VERSION 5.8 ;
BUSBITCHARS "[]" ;
DIVIDERCHAR "/" ;
UNITS
    DATABASE MICRONS 1000 ;
END UNITS

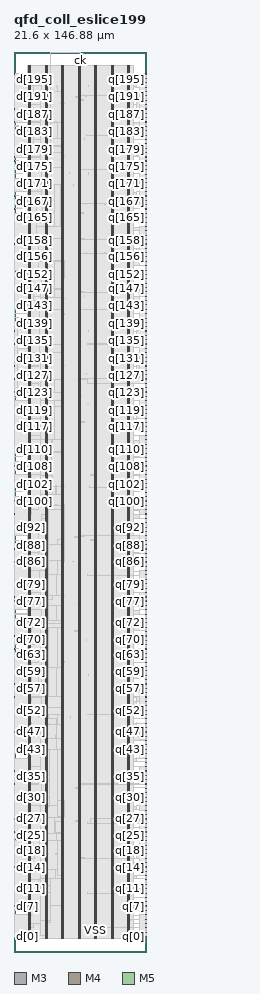
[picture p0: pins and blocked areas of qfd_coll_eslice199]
MACRO qfd_coll_eslice199
  FOREIGN qfd_coll_eslice199 0 0 ;
  CLASS BLOCK ;
  SIZE 21.6 BY 146.88 ;
  PIN ck
    DIRECTION INPUT ;
    USE SIGNAL ;
    PORT
      LAYER M3 ;
        RECT  10.8 146.842 10.818 146.88 ;
    END
    PORT
      LAYER M3 ;
        RECT  10.8 146.731 10.818 146.861 ;
    END
  END ck
  PIN d[0]
    DIRECTION INPUT ;
    USE SIGNAL ;
    PORT
      LAYER M4 ;
        RECT  0 2.496 0.084 2.52 ;
    END
  END d[0]
  PIN d[100]
    DIRECTION INPUT ;
    USE SIGNAL ;
    PORT
      LAYER M4 ;
        RECT  0 73.584 0.084 73.608 ;
    END
  END d[100]
  PIN d[101]
    DIRECTION INPUT ;
    USE SIGNAL ;
    PORT
      LAYER M4 ;
        RECT  0 74.304 0.084 74.328 ;
    END
  END d[101]
  PIN d[102]
    DIRECTION INPUT ;
    USE SIGNAL ;
    PORT
      LAYER M4 ;
        RECT  0 75.024 0.084 75.048 ;
    END
  END d[102]
  PIN d[103]
    DIRECTION INPUT ;
    USE SIGNAL ;
    PORT
      LAYER M4 ;
        RECT  0 75.744 0.084 75.768 ;
    END
  END d[103]
  PIN d[104]
    DIRECTION INPUT ;
    USE SIGNAL ;
    PORT
      LAYER M4 ;
        RECT  0 76.464 0.084 76.488 ;
    END
  END d[104]
  PIN d[105]
    DIRECTION INPUT ;
    USE SIGNAL ;
    PORT
      LAYER M4 ;
        RECT  0 77.136 0.084 77.16 ;
    END
  END d[105]
  PIN d[106]
    DIRECTION INPUT ;
    USE SIGNAL ;
    PORT
      LAYER M4 ;
        RECT  0 77.856 0.084 77.88 ;
    END
  END d[106]
  PIN d[107]
    DIRECTION INPUT ;
    USE SIGNAL ;
    PORT
      LAYER M4 ;
        RECT  0 78.576 0.084 78.6 ;
    END
  END d[107]
  PIN d[108]
    DIRECTION INPUT ;
    USE SIGNAL ;
    PORT
      LAYER M4 ;
        RECT  0 79.296 0.084 79.32 ;
    END
  END d[108]
  PIN d[109]
    DIRECTION INPUT ;
    USE SIGNAL ;
    PORT
      LAYER M4 ;
        RECT  0 80.016 0.084 80.04 ;
    END
  END d[109]
  PIN d[10]
    DIRECTION INPUT ;
    USE SIGNAL ;
    PORT
      LAYER M4 ;
        RECT  0 9.6 0.084 9.624 ;
    END
  END d[10]
  PIN d[110]
    DIRECTION INPUT ;
    USE SIGNAL ;
    PORT
      LAYER M4 ;
        RECT  0 80.688 0.084 80.712 ;
    END
  END d[110]
  PIN d[111]
    DIRECTION INPUT ;
    USE SIGNAL ;
    PORT
      LAYER M4 ;
        RECT  0 81.408 0.084 81.432 ;
    END
  END d[111]
  PIN d[112]
    DIRECTION INPUT ;
    USE SIGNAL ;
    PORT
      LAYER M4 ;
        RECT  0 82.128 0.084 82.152 ;
    END
  END d[112]
  PIN d[113]
    DIRECTION INPUT ;
    USE SIGNAL ;
    PORT
      LAYER M4 ;
        RECT  0 82.848 0.084 82.872 ;
    END
  END d[113]
  PIN d[114]
    DIRECTION INPUT ;
    USE SIGNAL ;
    PORT
      LAYER M4 ;
        RECT  0 83.568 0.084 83.592 ;
    END
  END d[114]
  PIN d[115]
    DIRECTION INPUT ;
    USE SIGNAL ;
    PORT
      LAYER M4 ;
        RECT  0 84.24 0.084 84.264 ;
    END
  END d[115]
  PIN d[116]
    DIRECTION INPUT ;
    USE SIGNAL ;
    PORT
      LAYER M4 ;
        RECT  0 84.96 0.084 84.984 ;
    END
  END d[116]
  PIN d[117]
    DIRECTION INPUT ;
    USE SIGNAL ;
    PORT
      LAYER M4 ;
        RECT  0 85.68 0.084 85.704 ;
    END
  END d[117]
  PIN d[118]
    DIRECTION INPUT ;
    USE SIGNAL ;
    PORT
      LAYER M4 ;
        RECT  0 86.4 0.084 86.424 ;
    END
  END d[118]
  PIN d[119]
    DIRECTION INPUT ;
    USE SIGNAL ;
    PORT
      LAYER M4 ;
        RECT  0 87.12 0.084 87.144 ;
    END
  END d[119]
  PIN d[11]
    DIRECTION INPUT ;
    USE SIGNAL ;
    PORT
      LAYER M4 ;
        RECT  0 10.32 0.084 10.344 ;
    END
  END d[11]
  PIN d[120]
    DIRECTION INPUT ;
    USE SIGNAL ;
    PORT
      LAYER M4 ;
        RECT  0 87.84 0.084 87.864 ;
    END
  END d[120]
  PIN d[121]
    DIRECTION INPUT ;
    USE SIGNAL ;
    PORT
      LAYER M4 ;
        RECT  0 88.512 0.084 88.536 ;
    END
  END d[121]
  PIN d[122]
    DIRECTION INPUT ;
    USE SIGNAL ;
    PORT
      LAYER M4 ;
        RECT  0 89.232 0.084 89.256 ;
    END
  END d[122]
  PIN d[123]
    DIRECTION INPUT ;
    USE SIGNAL ;
    PORT
      LAYER M4 ;
        RECT  0 89.952 0.084 89.976 ;
    END
  END d[123]
  PIN d[124]
    DIRECTION INPUT ;
    USE SIGNAL ;
    PORT
      LAYER M4 ;
        RECT  0 90.672 0.084 90.696 ;
    END
  END d[124]
  PIN d[125]
    DIRECTION INPUT ;
    USE SIGNAL ;
    PORT
      LAYER M4 ;
        RECT  0 91.392 0.084 91.416 ;
    END
  END d[125]
  PIN d[126]
    DIRECTION INPUT ;
    USE SIGNAL ;
    PORT
      LAYER M4 ;
        RECT  0 92.064 0.084 92.088 ;
    END
  END d[126]
  PIN d[127]
    DIRECTION INPUT ;
    USE SIGNAL ;
    PORT
      LAYER M4 ;
        RECT  0 92.784 0.084 92.808 ;
    END
  END d[127]
  PIN d[128]
    DIRECTION INPUT ;
    USE SIGNAL ;
    PORT
      LAYER M4 ;
        RECT  0 93.504 0.084 93.528 ;
    END
  END d[128]
  PIN d[129]
    DIRECTION INPUT ;
    USE SIGNAL ;
    PORT
      LAYER M4 ;
        RECT  0 94.224 0.084 94.248 ;
    END
  END d[129]
  PIN d[12]
    DIRECTION INPUT ;
    USE SIGNAL ;
    PORT
      LAYER M4 ;
        RECT  0 11.04 0.084 11.064 ;
    END
  END d[12]
  PIN d[130]
    DIRECTION INPUT ;
    USE SIGNAL ;
    PORT
      LAYER M4 ;
        RECT  0 94.944 0.084 94.968 ;
    END
  END d[130]
  PIN d[131]
    DIRECTION INPUT ;
    USE SIGNAL ;
    PORT
      LAYER M4 ;
        RECT  0 95.616 0.084 95.64 ;
    END
  END d[131]
  PIN d[132]
    DIRECTION INPUT ;
    USE SIGNAL ;
    PORT
      LAYER M4 ;
        RECT  0 96.336 0.084 96.36 ;
    END
  END d[132]
  PIN d[133]
    DIRECTION INPUT ;
    USE SIGNAL ;
    PORT
      LAYER M4 ;
        RECT  0 97.056 0.084 97.08 ;
    END
  END d[133]
  PIN d[134]
    DIRECTION INPUT ;
    USE SIGNAL ;
    PORT
      LAYER M4 ;
        RECT  0 97.776 0.084 97.8 ;
    END
  END d[134]
  PIN d[135]
    DIRECTION INPUT ;
    USE SIGNAL ;
    PORT
      LAYER M4 ;
        RECT  0 98.496 0.084 98.52 ;
    END
  END d[135]
  PIN d[136]
    DIRECTION INPUT ;
    USE SIGNAL ;
    PORT
      LAYER M4 ;
        RECT  0 99.216 0.084 99.24 ;
    END
  END d[136]
  PIN d[137]
    DIRECTION INPUT ;
    USE SIGNAL ;
    PORT
      LAYER M4 ;
        RECT  0 99.888 0.084 99.912 ;
    END
  END d[137]
  PIN d[138]
    DIRECTION INPUT ;
    USE SIGNAL ;
    PORT
      LAYER M4 ;
        RECT  0 100.608 0.084 100.632 ;
    END
  END d[138]
  PIN d[139]
    DIRECTION INPUT ;
    USE SIGNAL ;
    PORT
      LAYER M4 ;
        RECT  0 101.328 0.084 101.352 ;
    END
  END d[139]
  PIN d[13]
    DIRECTION INPUT ;
    USE SIGNAL ;
    PORT
      LAYER M4 ;
        RECT  0 11.76 0.084 11.784 ;
    END
  END d[13]
  PIN d[140]
    DIRECTION INPUT ;
    USE SIGNAL ;
    PORT
      LAYER M4 ;
        RECT  0 102.048 0.084 102.072 ;
    END
  END d[140]
  PIN d[141]
    DIRECTION INPUT ;
    USE SIGNAL ;
    PORT
      LAYER M4 ;
        RECT  0 102.768 0.084 102.792 ;
    END
  END d[141]
  PIN d[142]
    DIRECTION INPUT ;
    USE SIGNAL ;
    PORT
      LAYER M4 ;
        RECT  0 103.44 0.084 103.464 ;
    END
  END d[142]
  PIN d[143]
    DIRECTION INPUT ;
    USE SIGNAL ;
    PORT
      LAYER M4 ;
        RECT  0 104.16 0.084 104.184 ;
    END
  END d[143]
  PIN d[144]
    DIRECTION INPUT ;
    USE SIGNAL ;
    PORT
      LAYER M4 ;
        RECT  0 104.88 0.084 104.904 ;
    END
  END d[144]
  PIN d[145]
    DIRECTION INPUT ;
    USE SIGNAL ;
    PORT
      LAYER M4 ;
        RECT  0 105.6 0.084 105.624 ;
    END
  END d[145]
  PIN d[146]
    DIRECTION INPUT ;
    USE SIGNAL ;
    PORT
      LAYER M4 ;
        RECT  0 106.32 0.084 106.344 ;
    END
  END d[146]
  PIN d[147]
    DIRECTION INPUT ;
    USE SIGNAL ;
    PORT
      LAYER M4 ;
        RECT  0 106.992 0.084 107.016 ;
    END
  END d[147]
  PIN d[148]
    DIRECTION INPUT ;
    USE SIGNAL ;
    PORT
      LAYER M4 ;
        RECT  0 107.712 0.084 107.736 ;
    END
  END d[148]
  PIN d[149]
    DIRECTION INPUT ;
    USE SIGNAL ;
    PORT
      LAYER M4 ;
        RECT  0 108.432 0.084 108.456 ;
    END
  END d[149]
  PIN d[14]
    DIRECTION INPUT ;
    USE SIGNAL ;
    PORT
      LAYER M4 ;
        RECT  0 12.48 0.084 12.504 ;
    END
  END d[14]
  PIN d[150]
    DIRECTION INPUT ;
    USE SIGNAL ;
    PORT
      LAYER M4 ;
        RECT  0 109.152 0.084 109.176 ;
    END
  END d[150]
  PIN d[151]
    DIRECTION INPUT ;
    USE SIGNAL ;
    PORT
      LAYER M4 ;
        RECT  0 109.872 0.084 109.896 ;
    END
  END d[151]
  PIN d[152]
    DIRECTION INPUT ;
    USE SIGNAL ;
    PORT
      LAYER M4 ;
        RECT  0 110.592 0.084 110.616 ;
    END
  END d[152]
  PIN d[153]
    DIRECTION INPUT ;
    USE SIGNAL ;
    PORT
      LAYER M4 ;
        RECT  0 111.264 0.084 111.288 ;
    END
  END d[153]
  PIN d[154]
    DIRECTION INPUT ;
    USE SIGNAL ;
    PORT
      LAYER M4 ;
        RECT  0 111.984 0.084 112.008 ;
    END
  END d[154]
  PIN d[155]
    DIRECTION INPUT ;
    USE SIGNAL ;
    PORT
      LAYER M4 ;
        RECT  0 112.704 0.084 112.728 ;
    END
  END d[155]
  PIN d[156]
    DIRECTION INPUT ;
    USE SIGNAL ;
    PORT
      LAYER M4 ;
        RECT  0 113.424 0.084 113.448 ;
    END
  END d[156]
  PIN d[157]
    DIRECTION INPUT ;
    USE SIGNAL ;
    PORT
      LAYER M4 ;
        RECT  0 114.144 0.084 114.168 ;
    END
  END d[157]
  PIN d[158]
    DIRECTION INPUT ;
    USE SIGNAL ;
    PORT
      LAYER M4 ;
        RECT  0 114.816 0.084 114.84 ;
    END
  END d[158]
  PIN d[159]
    DIRECTION INPUT ;
    USE SIGNAL ;
    PORT
      LAYER M4 ;
        RECT  0 115.536 0.084 115.56 ;
    END
  END d[159]
  PIN d[15]
    DIRECTION INPUT ;
    USE SIGNAL ;
    PORT
      LAYER M4 ;
        RECT  0 13.152 0.084 13.176 ;
    END
  END d[15]
  PIN d[160]
    DIRECTION INPUT ;
    USE SIGNAL ;
    PORT
      LAYER M4 ;
        RECT  0 116.256 0.084 116.28 ;
    END
  END d[160]
  PIN d[161]
    DIRECTION INPUT ;
    USE SIGNAL ;
    PORT
      LAYER M4 ;
        RECT  0 116.976 0.084 117 ;
    END
  END d[161]
  PIN d[162]
    DIRECTION INPUT ;
    USE SIGNAL ;
    PORT
      LAYER M4 ;
        RECT  0 117.696 0.084 117.72 ;
    END
  END d[162]
  PIN d[163]
    DIRECTION INPUT ;
    USE SIGNAL ;
    PORT
      LAYER M4 ;
        RECT  0 118.368 0.084 118.392 ;
    END
  END d[163]
  PIN d[164]
    DIRECTION INPUT ;
    USE SIGNAL ;
    PORT
      LAYER M4 ;
        RECT  0 119.088 0.084 119.112 ;
    END
  END d[164]
  PIN d[165]
    DIRECTION INPUT ;
    USE SIGNAL ;
    PORT
      LAYER M4 ;
        RECT  0 119.808 0.084 119.832 ;
    END
  END d[165]
  PIN d[166]
    DIRECTION INPUT ;
    USE SIGNAL ;
    PORT
      LAYER M4 ;
        RECT  0 120.528 0.084 120.552 ;
    END
  END d[166]
  PIN d[167]
    DIRECTION INPUT ;
    USE SIGNAL ;
    PORT
      LAYER M4 ;
        RECT  0 121.248 0.084 121.272 ;
    END
  END d[167]
  PIN d[168]
    DIRECTION INPUT ;
    USE SIGNAL ;
    PORT
      LAYER M4 ;
        RECT  0 121.968 0.084 121.992 ;
    END
  END d[168]
  PIN d[169]
    DIRECTION INPUT ;
    USE SIGNAL ;
    PORT
      LAYER M4 ;
        RECT  0 122.64 0.084 122.664 ;
    END
  END d[169]
  PIN d[16]
    DIRECTION INPUT ;
    USE SIGNAL ;
    PORT
      LAYER M4 ;
        RECT  0 13.872 0.084 13.896 ;
    END
  END d[16]
  PIN d[170]
    DIRECTION INPUT ;
    USE SIGNAL ;
    PORT
      LAYER M4 ;
        RECT  0 123.36 0.084 123.384 ;
    END
  END d[170]
  PIN d[171]
    DIRECTION INPUT ;
    USE SIGNAL ;
    PORT
      LAYER M4 ;
        RECT  0 124.08 0.084 124.104 ;
    END
  END d[171]
  PIN d[172]
    DIRECTION INPUT ;
    USE SIGNAL ;
    PORT
      LAYER M4 ;
        RECT  0 124.8 0.084 124.824 ;
    END
  END d[172]
  PIN d[173]
    DIRECTION INPUT ;
    USE SIGNAL ;
    PORT
      LAYER M4 ;
        RECT  0 125.52 0.084 125.544 ;
    END
  END d[173]
  PIN d[174]
    DIRECTION INPUT ;
    USE SIGNAL ;
    PORT
      LAYER M4 ;
        RECT  0 126.192 0.084 126.216 ;
    END
  END d[174]
  PIN d[175]
    DIRECTION INPUT ;
    USE SIGNAL ;
    PORT
      LAYER M4 ;
        RECT  0 126.912 0.084 126.936 ;
    END
  END d[175]
  PIN d[176]
    DIRECTION INPUT ;
    USE SIGNAL ;
    PORT
      LAYER M4 ;
        RECT  0 127.632 0.084 127.656 ;
    END
  END d[176]
  PIN d[177]
    DIRECTION INPUT ;
    USE SIGNAL ;
    PORT
      LAYER M4 ;
        RECT  0 128.352 0.084 128.376 ;
    END
  END d[177]
  PIN d[178]
    DIRECTION INPUT ;
    USE SIGNAL ;
    PORT
      LAYER M4 ;
        RECT  0 129.072 0.084 129.096 ;
    END
  END d[178]
  PIN d[179]
    DIRECTION INPUT ;
    USE SIGNAL ;
    PORT
      LAYER M4 ;
        RECT  0 129.744 0.084 129.768 ;
    END
  END d[179]
  PIN d[17]
    DIRECTION INPUT ;
    USE SIGNAL ;
    PORT
      LAYER M4 ;
        RECT  0 14.592 0.084 14.616 ;
    END
  END d[17]
  PIN d[180]
    DIRECTION INPUT ;
    USE SIGNAL ;
    PORT
      LAYER M4 ;
        RECT  0 130.464 0.084 130.488 ;
    END
  END d[180]
  PIN d[181]
    DIRECTION INPUT ;
    USE SIGNAL ;
    PORT
      LAYER M4 ;
        RECT  0 131.184 0.084 131.208 ;
    END
  END d[181]
  PIN d[182]
    DIRECTION INPUT ;
    USE SIGNAL ;
    PORT
      LAYER M4 ;
        RECT  0 131.904 0.084 131.928 ;
    END
  END d[182]
  PIN d[183]
    DIRECTION INPUT ;
    USE SIGNAL ;
    PORT
      LAYER M4 ;
        RECT  0 132.624 0.084 132.648 ;
    END
  END d[183]
  PIN d[184]
    DIRECTION INPUT ;
    USE SIGNAL ;
    PORT
      LAYER M4 ;
        RECT  0 133.296 0.084 133.32 ;
    END
  END d[184]
  PIN d[185]
    DIRECTION INPUT ;
    USE SIGNAL ;
    PORT
      LAYER M4 ;
        RECT  0 134.016 0.084 134.04 ;
    END
  END d[185]
  PIN d[186]
    DIRECTION INPUT ;
    USE SIGNAL ;
    PORT
      LAYER M4 ;
        RECT  0 134.736 0.084 134.76 ;
    END
  END d[186]
  PIN d[187]
    DIRECTION INPUT ;
    USE SIGNAL ;
    PORT
      LAYER M4 ;
        RECT  0 135.456 0.084 135.48 ;
    END
  END d[187]
  PIN d[188]
    DIRECTION INPUT ;
    USE SIGNAL ;
    PORT
      LAYER M4 ;
        RECT  0 136.176 0.084 136.2 ;
    END
  END d[188]
  PIN d[189]
    DIRECTION INPUT ;
    USE SIGNAL ;
    PORT
      LAYER M4 ;
        RECT  0 136.896 0.084 136.92 ;
    END
  END d[189]
  PIN d[18]
    DIRECTION INPUT ;
    USE SIGNAL ;
    PORT
      LAYER M4 ;
        RECT  0 15.312 0.084 15.336 ;
    END
  END d[18]
  PIN d[190]
    DIRECTION INPUT ;
    USE SIGNAL ;
    PORT
      LAYER M4 ;
        RECT  0 137.568 0.084 137.592 ;
    END
  END d[190]
  PIN d[191]
    DIRECTION INPUT ;
    USE SIGNAL ;
    PORT
      LAYER M4 ;
        RECT  0 138.288 0.084 138.312 ;
    END
  END d[191]
  PIN d[192]
    DIRECTION INPUT ;
    USE SIGNAL ;
    PORT
      LAYER M4 ;
        RECT  0 139.008 0.084 139.032 ;
    END
  END d[192]
  PIN d[193]
    DIRECTION INPUT ;
    USE SIGNAL ;
    PORT
      LAYER M4 ;
        RECT  0 139.728 0.084 139.752 ;
    END
  END d[193]
  PIN d[194]
    DIRECTION INPUT ;
    USE SIGNAL ;
    PORT
      LAYER M4 ;
        RECT  0 140.448 0.084 140.472 ;
    END
  END d[194]
  PIN d[195]
    DIRECTION INPUT ;
    USE SIGNAL ;
    PORT
      LAYER M4 ;
        RECT  0 141.12 0.084 141.144 ;
    END
  END d[195]
  PIN d[196]
    DIRECTION INPUT ;
    USE SIGNAL ;
    PORT
      LAYER M4 ;
        RECT  0 141.84 0.084 141.864 ;
    END
  END d[196]
  PIN d[197]
    DIRECTION INPUT ;
    USE SIGNAL ;
    PORT
      LAYER M4 ;
        RECT  0 142.56 0.084 142.584 ;
    END
  END d[197]
  PIN d[198]
    DIRECTION INPUT ;
    USE SIGNAL ;
    PORT
      LAYER M4 ;
        RECT  0 143.28 0.084 143.304 ;
    END
  END d[198]
  PIN d[19]
    DIRECTION INPUT ;
    USE SIGNAL ;
    PORT
      LAYER M4 ;
        RECT  0 16.032 0.084 16.056 ;
    END
  END d[19]
  PIN d[1]
    DIRECTION INPUT ;
    USE SIGNAL ;
    PORT
      LAYER M4 ;
        RECT  0 3.216 0.084 3.24 ;
    END
  END d[1]
  PIN d[20]
    DIRECTION INPUT ;
    USE SIGNAL ;
    PORT
      LAYER M4 ;
        RECT  0 16.704 0.084 16.728 ;
    END
  END d[20]
  PIN d[21]
    DIRECTION INPUT ;
    USE SIGNAL ;
    PORT
      LAYER M4 ;
        RECT  0 17.424 0.084 17.448 ;
    END
  END d[21]
  PIN d[22]
    DIRECTION INPUT ;
    USE SIGNAL ;
    PORT
      LAYER M4 ;
        RECT  0 18.144 0.084 18.168 ;
    END
  END d[22]
  PIN d[23]
    DIRECTION INPUT ;
    USE SIGNAL ;
    PORT
      LAYER M4 ;
        RECT  0 18.864 0.084 18.888 ;
    END
  END d[23]
  PIN d[24]
    DIRECTION INPUT ;
    USE SIGNAL ;
    PORT
      LAYER M4 ;
        RECT  0 19.584 0.084 19.608 ;
    END
  END d[24]
  PIN d[25]
    DIRECTION INPUT ;
    USE SIGNAL ;
    PORT
      LAYER M4 ;
        RECT  0 20.256 0.084 20.28 ;
    END
  END d[25]
  PIN d[26]
    DIRECTION INPUT ;
    USE SIGNAL ;
    PORT
      LAYER M4 ;
        RECT  0 20.976 0.084 21 ;
    END
  END d[26]
  PIN d[27]
    DIRECTION INPUT ;
    USE SIGNAL ;
    PORT
      LAYER M4 ;
        RECT  0 21.696 0.084 21.72 ;
    END
  END d[27]
  PIN d[28]
    DIRECTION INPUT ;
    USE SIGNAL ;
    PORT
      LAYER M4 ;
        RECT  0 22.416 0.084 22.44 ;
    END
  END d[28]
  PIN d[29]
    DIRECTION INPUT ;
    USE SIGNAL ;
    PORT
      LAYER M4 ;
        RECT  0 23.136 0.084 23.16 ;
    END
  END d[29]
  PIN d[2]
    DIRECTION INPUT ;
    USE SIGNAL ;
    PORT
      LAYER M4 ;
        RECT  0 3.936 0.084 3.96 ;
    END
  END d[2]
  PIN d[30]
    DIRECTION INPUT ;
    USE SIGNAL ;
    PORT
      LAYER M4 ;
        RECT  0 23.856 0.084 23.88 ;
    END
  END d[30]
  PIN d[31]
    DIRECTION INPUT ;
    USE SIGNAL ;
    PORT
      LAYER M4 ;
        RECT  0 24.528 0.084 24.552 ;
    END
  END d[31]
  PIN d[32]
    DIRECTION INPUT ;
    USE SIGNAL ;
    PORT
      LAYER M4 ;
        RECT  0 25.248 0.084 25.272 ;
    END
  END d[32]
  PIN d[33]
    DIRECTION INPUT ;
    USE SIGNAL ;
    PORT
      LAYER M4 ;
        RECT  0 25.968 0.084 25.992 ;
    END
  END d[33]
  PIN d[34]
    DIRECTION INPUT ;
    USE SIGNAL ;
    PORT
      LAYER M4 ;
        RECT  0 26.688 0.084 26.712 ;
    END
  END d[34]
  PIN d[35]
    DIRECTION INPUT ;
    USE SIGNAL ;
    PORT
      LAYER M4 ;
        RECT  0 27.408 0.084 27.432 ;
    END
  END d[35]
  PIN d[36]
    DIRECTION INPUT ;
    USE SIGNAL ;
    PORT
      LAYER M4 ;
        RECT  0 28.08 0.084 28.104 ;
    END
  END d[36]
  PIN d[37]
    DIRECTION INPUT ;
    USE SIGNAL ;
    PORT
      LAYER M4 ;
        RECT  0 28.8 0.084 28.824 ;
    END
  END d[37]
  PIN d[38]
    DIRECTION INPUT ;
    USE SIGNAL ;
    PORT
      LAYER M4 ;
        RECT  0 29.52 0.084 29.544 ;
    END
  END d[38]
  PIN d[39]
    DIRECTION INPUT ;
    USE SIGNAL ;
    PORT
      LAYER M4 ;
        RECT  0 30.24 0.084 30.264 ;
    END
  END d[39]
  PIN d[3]
    DIRECTION INPUT ;
    USE SIGNAL ;
    PORT
      LAYER M4 ;
        RECT  0 4.656 0.084 4.68 ;
    END
  END d[3]
  PIN d[40]
    DIRECTION INPUT ;
    USE SIGNAL ;
    PORT
      LAYER M4 ;
        RECT  0 30.96 0.084 30.984 ;
    END
  END d[40]
  PIN d[41]
    DIRECTION INPUT ;
    USE SIGNAL ;
    PORT
      LAYER M4 ;
        RECT  0 31.632 0.084 31.656 ;
    END
  END d[41]
  PIN d[42]
    DIRECTION INPUT ;
    USE SIGNAL ;
    PORT
      LAYER M4 ;
        RECT  0 32.352 0.084 32.376 ;
    END
  END d[42]
  PIN d[43]
    DIRECTION INPUT ;
    USE SIGNAL ;
    PORT
      LAYER M4 ;
        RECT  0 33.072 0.084 33.096 ;
    END
  END d[43]
  PIN d[44]
    DIRECTION INPUT ;
    USE SIGNAL ;
    PORT
      LAYER M4 ;
        RECT  0 33.792 0.084 33.816 ;
    END
  END d[44]
  PIN d[45]
    DIRECTION INPUT ;
    USE SIGNAL ;
    PORT
      LAYER M4 ;
        RECT  0 34.512 0.084 34.536 ;
    END
  END d[45]
  PIN d[46]
    DIRECTION INPUT ;
    USE SIGNAL ;
    PORT
      LAYER M4 ;
        RECT  0 35.184 0.084 35.208 ;
    END
  END d[46]
  PIN d[47]
    DIRECTION INPUT ;
    USE SIGNAL ;
    PORT
      LAYER M4 ;
        RECT  0 35.904 0.084 35.928 ;
    END
  END d[47]
  PIN d[48]
    DIRECTION INPUT ;
    USE SIGNAL ;
    PORT
      LAYER M4 ;
        RECT  0 36.624 0.084 36.648 ;
    END
  END d[48]
  PIN d[49]
    DIRECTION INPUT ;
    USE SIGNAL ;
    PORT
      LAYER M4 ;
        RECT  0 37.344 0.084 37.368 ;
    END
  END d[49]
  PIN d[4]
    DIRECTION INPUT ;
    USE SIGNAL ;
    PORT
      LAYER M4 ;
        RECT  0 5.328 0.084 5.352 ;
    END
  END d[4]
  PIN d[50]
    DIRECTION INPUT ;
    USE SIGNAL ;
    PORT
      LAYER M4 ;
        RECT  0 38.064 0.084 38.088 ;
    END
  END d[50]
  PIN d[51]
    DIRECTION INPUT ;
    USE SIGNAL ;
    PORT
      LAYER M4 ;
        RECT  0 38.784 0.084 38.808 ;
    END
  END d[51]
  PIN d[52]
    DIRECTION INPUT ;
    USE SIGNAL ;
    PORT
      LAYER M4 ;
        RECT  0 39.456 0.084 39.48 ;
    END
  END d[52]
  PIN d[53]
    DIRECTION INPUT ;
    USE SIGNAL ;
    PORT
      LAYER M4 ;
        RECT  0 40.176 0.084 40.2 ;
    END
  END d[53]
  PIN d[54]
    DIRECTION INPUT ;
    USE SIGNAL ;
    PORT
      LAYER M4 ;
        RECT  0 40.896 0.084 40.92 ;
    END
  END d[54]
  PIN d[55]
    DIRECTION INPUT ;
    USE SIGNAL ;
    PORT
      LAYER M4 ;
        RECT  0 41.616 0.084 41.64 ;
    END
  END d[55]
  PIN d[56]
    DIRECTION INPUT ;
    USE SIGNAL ;
    PORT
      LAYER M4 ;
        RECT  0 42.336 0.084 42.36 ;
    END
  END d[56]
  PIN d[57]
    DIRECTION INPUT ;
    USE SIGNAL ;
    PORT
      LAYER M4 ;
        RECT  0 43.008 0.084 43.032 ;
    END
  END d[57]
  PIN d[58]
    DIRECTION INPUT ;
    USE SIGNAL ;
    PORT
      LAYER M4 ;
        RECT  0 43.728 0.084 43.752 ;
    END
  END d[58]
  PIN d[59]
    DIRECTION INPUT ;
    USE SIGNAL ;
    PORT
      LAYER M4 ;
        RECT  0 44.448 0.084 44.472 ;
    END
  END d[59]
  PIN d[5]
    DIRECTION INPUT ;
    USE SIGNAL ;
    PORT
      LAYER M4 ;
        RECT  0 6.048 0.084 6.072 ;
    END
  END d[5]
  PIN d[60]
    DIRECTION INPUT ;
    USE SIGNAL ;
    PORT
      LAYER M4 ;
        RECT  0 45.168 0.084 45.192 ;
    END
  END d[60]
  PIN d[61]
    DIRECTION INPUT ;
    USE SIGNAL ;
    PORT
      LAYER M4 ;
        RECT  0 45.888 0.084 45.912 ;
    END
  END d[61]
  PIN d[62]
    DIRECTION INPUT ;
    USE SIGNAL ;
    PORT
      LAYER M4 ;
        RECT  0 46.56 0.084 46.584 ;
    END
  END d[62]
  PIN d[63]
    DIRECTION INPUT ;
    USE SIGNAL ;
    PORT
      LAYER M4 ;
        RECT  0 47.28 0.084 47.304 ;
    END
  END d[63]
  PIN d[64]
    DIRECTION INPUT ;
    USE SIGNAL ;
    PORT
      LAYER M4 ;
        RECT  0 48 0.084 48.024 ;
    END
  END d[64]
  PIN d[65]
    DIRECTION INPUT ;
    USE SIGNAL ;
    PORT
      LAYER M4 ;
        RECT  0 48.72 0.084 48.744 ;
    END
  END d[65]
  PIN d[66]
    DIRECTION INPUT ;
    USE SIGNAL ;
    PORT
      LAYER M4 ;
        RECT  0 49.44 0.084 49.464 ;
    END
  END d[66]
  PIN d[67]
    DIRECTION INPUT ;
    USE SIGNAL ;
    PORT
      LAYER M4 ;
        RECT  0 50.16 0.084 50.184 ;
    END
  END d[67]
  PIN d[68]
    DIRECTION INPUT ;
    USE SIGNAL ;
    PORT
      LAYER M4 ;
        RECT  0 50.832 0.084 50.856 ;
    END
  END d[68]
  PIN d[69]
    DIRECTION INPUT ;
    USE SIGNAL ;
    PORT
      LAYER M4 ;
        RECT  0 51.552 0.084 51.576 ;
    END
  END d[69]
  PIN d[6]
    DIRECTION INPUT ;
    USE SIGNAL ;
    PORT
      LAYER M4 ;
        RECT  0 6.768 0.084 6.792 ;
    END
  END d[6]
  PIN d[70]
    DIRECTION INPUT ;
    USE SIGNAL ;
    PORT
      LAYER M4 ;
        RECT  0 52.272 0.084 52.296 ;
    END
  END d[70]
  PIN d[71]
    DIRECTION INPUT ;
    USE SIGNAL ;
    PORT
      LAYER M4 ;
        RECT  0 52.992 0.084 53.016 ;
    END
  END d[71]
  PIN d[72]
    DIRECTION INPUT ;
    USE SIGNAL ;
    PORT
      LAYER M4 ;
        RECT  0 53.712 0.084 53.736 ;
    END
  END d[72]
  PIN d[73]
    DIRECTION INPUT ;
    USE SIGNAL ;
    PORT
      LAYER M4 ;
        RECT  0 54.384 0.084 54.408 ;
    END
  END d[73]
  PIN d[74]
    DIRECTION INPUT ;
    USE SIGNAL ;
    PORT
      LAYER M4 ;
        RECT  0 55.104 0.084 55.128 ;
    END
  END d[74]
  PIN d[75]
    DIRECTION INPUT ;
    USE SIGNAL ;
    PORT
      LAYER M4 ;
        RECT  0 55.824 0.084 55.848 ;
    END
  END d[75]
  PIN d[76]
    DIRECTION INPUT ;
    USE SIGNAL ;
    PORT
      LAYER M4 ;
        RECT  0 56.544 0.084 56.568 ;
    END
  END d[76]
  PIN d[77]
    DIRECTION INPUT ;
    USE SIGNAL ;
    PORT
      LAYER M4 ;
        RECT  0 57.264 0.084 57.288 ;
    END
  END d[77]
  PIN d[78]
    DIRECTION INPUT ;
    USE SIGNAL ;
    PORT
      LAYER M4 ;
        RECT  0 57.936 0.084 57.96 ;
    END
  END d[78]
  PIN d[79]
    DIRECTION INPUT ;
    USE SIGNAL ;
    PORT
      LAYER M4 ;
        RECT  0 58.656 0.084 58.68 ;
    END
  END d[79]
  PIN d[7]
    DIRECTION INPUT ;
    USE SIGNAL ;
    PORT
      LAYER M4 ;
        RECT  0 7.488 0.084 7.512 ;
    END
  END d[7]
  PIN d[80]
    DIRECTION INPUT ;
    USE SIGNAL ;
    PORT
      LAYER M4 ;
        RECT  0 59.376 0.084 59.4 ;
    END
  END d[80]
  PIN d[81]
    DIRECTION INPUT ;
    USE SIGNAL ;
    PORT
      LAYER M4 ;
        RECT  0 60.096 0.084 60.12 ;
    END
  END d[81]
  PIN d[82]
    DIRECTION INPUT ;
    USE SIGNAL ;
    PORT
      LAYER M4 ;
        RECT  0 60.816 0.084 60.84 ;
    END
  END d[82]
  PIN d[83]
    DIRECTION INPUT ;
    USE SIGNAL ;
    PORT
      LAYER M4 ;
        RECT  0 61.536 0.084 61.56 ;
    END
  END d[83]
  PIN d[84]
    DIRECTION INPUT ;
    USE SIGNAL ;
    PORT
      LAYER M4 ;
        RECT  0 62.208 0.084 62.232 ;
    END
  END d[84]
  PIN d[85]
    DIRECTION INPUT ;
    USE SIGNAL ;
    PORT
      LAYER M4 ;
        RECT  0 62.928 0.084 62.952 ;
    END
  END d[85]
  PIN d[86]
    DIRECTION INPUT ;
    USE SIGNAL ;
    PORT
      LAYER M4 ;
        RECT  0 63.648 0.084 63.672 ;
    END
  END d[86]
  PIN d[87]
    DIRECTION INPUT ;
    USE SIGNAL ;
    PORT
      LAYER M4 ;
        RECT  0 64.368 0.084 64.392 ;
    END
  END d[87]
  PIN d[88]
    DIRECTION INPUT ;
    USE SIGNAL ;
    PORT
      LAYER M4 ;
        RECT  0 65.088 0.084 65.112 ;
    END
  END d[88]
  PIN d[89]
    DIRECTION INPUT ;
    USE SIGNAL ;
    PORT
      LAYER M4 ;
        RECT  0 65.76 0.084 65.784 ;
    END
  END d[89]
  PIN d[8]
    DIRECTION INPUT ;
    USE SIGNAL ;
    PORT
      LAYER M4 ;
        RECT  0 8.208 0.084 8.232 ;
    END
  END d[8]
  PIN d[90]
    DIRECTION INPUT ;
    USE SIGNAL ;
    PORT
      LAYER M4 ;
        RECT  0 66.48 0.084 66.504 ;
    END
  END d[90]
  PIN d[91]
    DIRECTION INPUT ;
    USE SIGNAL ;
    PORT
      LAYER M4 ;
        RECT  0 67.2 0.084 67.224 ;
    END
  END d[91]
  PIN d[92]
    DIRECTION INPUT ;
    USE SIGNAL ;
    PORT
      LAYER M4 ;
        RECT  0 67.92 0.084 67.944 ;
    END
  END d[92]
  PIN d[93]
    DIRECTION INPUT ;
    USE SIGNAL ;
    PORT
      LAYER M4 ;
        RECT  0 68.64 0.084 68.664 ;
    END
  END d[93]
  PIN d[94]
    DIRECTION INPUT ;
    USE SIGNAL ;
    PORT
      LAYER M4 ;
        RECT  0 69.312 0.084 69.336 ;
    END
  END d[94]
  PIN d[95]
    DIRECTION INPUT ;
    USE SIGNAL ;
    PORT
      LAYER M4 ;
        RECT  0 70.032 0.084 70.056 ;
    END
  END d[95]
  PIN d[96]
    DIRECTION INPUT ;
    USE SIGNAL ;
    PORT
      LAYER M4 ;
        RECT  0 70.752 0.084 70.776 ;
    END
  END d[96]
  PIN d[97]
    DIRECTION INPUT ;
    USE SIGNAL ;
    PORT
      LAYER M4 ;
        RECT  0 71.472 0.084 71.496 ;
    END
  END d[97]
  PIN d[98]
    DIRECTION INPUT ;
    USE SIGNAL ;
    PORT
      LAYER M4 ;
        RECT  0 72.192 0.084 72.216 ;
    END
  END d[98]
  PIN d[99]
    DIRECTION INPUT ;
    USE SIGNAL ;
    PORT
      LAYER M4 ;
        RECT  0 72.912 0.084 72.936 ;
    END
  END d[99]
  PIN d[9]
    DIRECTION INPUT ;
    USE SIGNAL ;
    PORT
      LAYER M4 ;
        RECT  0 8.88 0.084 8.904 ;
    END
  END d[9]
  PIN q[0]
    DIRECTION OUTPUT ;
    USE SIGNAL ;
    PORT
      LAYER M4 ;
        RECT  21.516 2.496 21.6 2.52 ;
    END
  END q[0]
  PIN q[100]
    DIRECTION OUTPUT ;
    USE SIGNAL ;
    PORT
      LAYER M4 ;
        RECT  21.516 73.584 21.6 73.608 ;
    END
  END q[100]
  PIN q[101]
    DIRECTION OUTPUT ;
    USE SIGNAL ;
    PORT
      LAYER M4 ;
        RECT  21.516 74.304 21.6 74.328 ;
    END
  END q[101]
  PIN q[102]
    DIRECTION OUTPUT ;
    USE SIGNAL ;
    PORT
      LAYER M4 ;
        RECT  21.516 75.024 21.6 75.048 ;
    END
  END q[102]
  PIN q[103]
    DIRECTION OUTPUT ;
    USE SIGNAL ;
    PORT
      LAYER M4 ;
        RECT  21.516 75.744 21.6 75.768 ;
    END
  END q[103]
  PIN q[104]
    DIRECTION OUTPUT ;
    USE SIGNAL ;
    PORT
      LAYER M4 ;
        RECT  21.516 76.464 21.6 76.488 ;
    END
  END q[104]
  PIN q[105]
    DIRECTION OUTPUT ;
    USE SIGNAL ;
    PORT
      LAYER M4 ;
        RECT  21.516 77.136 21.6 77.16 ;
    END
  END q[105]
  PIN q[106]
    DIRECTION OUTPUT ;
    USE SIGNAL ;
    PORT
      LAYER M4 ;
        RECT  21.516 77.856 21.6 77.88 ;
    END
  END q[106]
  PIN q[107]
    DIRECTION OUTPUT ;
    USE SIGNAL ;
    PORT
      LAYER M4 ;
        RECT  21.516 78.576 21.6 78.6 ;
    END
  END q[107]
  PIN q[108]
    DIRECTION OUTPUT ;
    USE SIGNAL ;
    PORT
      LAYER M4 ;
        RECT  21.516 79.296 21.6 79.32 ;
    END
  END q[108]
  PIN q[109]
    DIRECTION OUTPUT ;
    USE SIGNAL ;
    PORT
      LAYER M4 ;
        RECT  21.516 80.016 21.6 80.04 ;
    END
  END q[109]
  PIN q[10]
    DIRECTION OUTPUT ;
    USE SIGNAL ;
    PORT
      LAYER M4 ;
        RECT  21.516 9.6 21.6 9.624 ;
    END
  END q[10]
  PIN q[110]
    DIRECTION OUTPUT ;
    USE SIGNAL ;
    PORT
      LAYER M4 ;
        RECT  21.516 80.688 21.6 80.712 ;
    END
  END q[110]
  PIN q[111]
    DIRECTION OUTPUT ;
    USE SIGNAL ;
    PORT
      LAYER M4 ;
        RECT  21.516 81.408 21.6 81.432 ;
    END
  END q[111]
  PIN q[112]
    DIRECTION OUTPUT ;
    USE SIGNAL ;
    PORT
      LAYER M4 ;
        RECT  21.516 82.128 21.6 82.152 ;
    END
  END q[112]
  PIN q[113]
    DIRECTION OUTPUT ;
    USE SIGNAL ;
    PORT
      LAYER M4 ;
        RECT  21.516 82.848 21.6 82.872 ;
    END
  END q[113]
  PIN q[114]
    DIRECTION OUTPUT ;
    USE SIGNAL ;
    PORT
      LAYER M4 ;
        RECT  21.516 83.568 21.6 83.592 ;
    END
  END q[114]
  PIN q[115]
    DIRECTION OUTPUT ;
    USE SIGNAL ;
    PORT
      LAYER M4 ;
        RECT  21.516 84.24 21.6 84.264 ;
    END
  END q[115]
  PIN q[116]
    DIRECTION OUTPUT ;
    USE SIGNAL ;
    PORT
      LAYER M4 ;
        RECT  21.516 84.96 21.6 84.984 ;
    END
  END q[116]
  PIN q[117]
    DIRECTION OUTPUT ;
    USE SIGNAL ;
    PORT
      LAYER M4 ;
        RECT  21.516 85.68 21.6 85.704 ;
    END
  END q[117]
  PIN q[118]
    DIRECTION OUTPUT ;
    USE SIGNAL ;
    PORT
      LAYER M4 ;
        RECT  21.516 86.4 21.6 86.424 ;
    END
  END q[118]
  PIN q[119]
    DIRECTION OUTPUT ;
    USE SIGNAL ;
    PORT
      LAYER M4 ;
        RECT  21.516 87.12 21.6 87.144 ;
    END
  END q[119]
  PIN q[11]
    DIRECTION OUTPUT ;
    USE SIGNAL ;
    PORT
      LAYER M4 ;
        RECT  21.516 10.32 21.6 10.344 ;
    END
  END q[11]
  PIN q[120]
    DIRECTION OUTPUT ;
    USE SIGNAL ;
    PORT
      LAYER M4 ;
        RECT  21.516 87.84 21.6 87.864 ;
    END
  END q[120]
  PIN q[121]
    DIRECTION OUTPUT ;
    USE SIGNAL ;
    PORT
      LAYER M4 ;
        RECT  21.516 88.512 21.6 88.536 ;
    END
  END q[121]
  PIN q[122]
    DIRECTION OUTPUT ;
    USE SIGNAL ;
    PORT
      LAYER M4 ;
        RECT  21.516 89.232 21.6 89.256 ;
    END
  END q[122]
  PIN q[123]
    DIRECTION OUTPUT ;
    USE SIGNAL ;
    PORT
      LAYER M4 ;
        RECT  21.516 89.952 21.6 89.976 ;
    END
  END q[123]
  PIN q[124]
    DIRECTION OUTPUT ;
    USE SIGNAL ;
    PORT
      LAYER M4 ;
        RECT  21.516 90.672 21.6 90.696 ;
    END
  END q[124]
  PIN q[125]
    DIRECTION OUTPUT ;
    USE SIGNAL ;
    PORT
      LAYER M4 ;
        RECT  21.516 91.392 21.6 91.416 ;
    END
  END q[125]
  PIN q[126]
    DIRECTION OUTPUT ;
    USE SIGNAL ;
    PORT
      LAYER M4 ;
        RECT  21.516 92.064 21.6 92.088 ;
    END
  END q[126]
  PIN q[127]
    DIRECTION OUTPUT ;
    USE SIGNAL ;
    PORT
      LAYER M4 ;
        RECT  21.516 92.784 21.6 92.808 ;
    END
  END q[127]
  PIN q[128]
    DIRECTION OUTPUT ;
    USE SIGNAL ;
    PORT
      LAYER M4 ;
        RECT  21.516 93.504 21.6 93.528 ;
    END
  END q[128]
  PIN q[129]
    DIRECTION OUTPUT ;
    USE SIGNAL ;
    PORT
      LAYER M4 ;
        RECT  21.516 94.224 21.6 94.248 ;
    END
  END q[129]
  PIN q[12]
    DIRECTION OUTPUT ;
    USE SIGNAL ;
    PORT
      LAYER M4 ;
        RECT  21.516 11.04 21.6 11.064 ;
    END
  END q[12]
  PIN q[130]
    DIRECTION OUTPUT ;
    USE SIGNAL ;
    PORT
      LAYER M4 ;
        RECT  21.516 94.944 21.6 94.968 ;
    END
  END q[130]
  PIN q[131]
    DIRECTION OUTPUT ;
    USE SIGNAL ;
    PORT
      LAYER M4 ;
        RECT  21.516 95.616 21.6 95.64 ;
    END
  END q[131]
  PIN q[132]
    DIRECTION OUTPUT ;
    USE SIGNAL ;
    PORT
      LAYER M4 ;
        RECT  21.516 96.336 21.6 96.36 ;
    END
  END q[132]
  PIN q[133]
    DIRECTION OUTPUT ;
    USE SIGNAL ;
    PORT
      LAYER M4 ;
        RECT  21.516 97.056 21.6 97.08 ;
    END
  END q[133]
  PIN q[134]
    DIRECTION OUTPUT ;
    USE SIGNAL ;
    PORT
      LAYER M4 ;
        RECT  21.516 97.776 21.6 97.8 ;
    END
  END q[134]
  PIN q[135]
    DIRECTION OUTPUT ;
    USE SIGNAL ;
    PORT
      LAYER M4 ;
        RECT  21.516 98.496 21.6 98.52 ;
    END
  END q[135]
  PIN q[136]
    DIRECTION OUTPUT ;
    USE SIGNAL ;
    PORT
      LAYER M4 ;
        RECT  21.516 99.216 21.6 99.24 ;
    END
  END q[136]
  PIN q[137]
    DIRECTION OUTPUT ;
    USE SIGNAL ;
    PORT
      LAYER M4 ;
        RECT  21.516 99.888 21.6 99.912 ;
    END
  END q[137]
  PIN q[138]
    DIRECTION OUTPUT ;
    USE SIGNAL ;
    PORT
      LAYER M4 ;
        RECT  21.516 100.608 21.6 100.632 ;
    END
  END q[138]
  PIN q[139]
    DIRECTION OUTPUT ;
    USE SIGNAL ;
    PORT
      LAYER M4 ;
        RECT  21.516 101.328 21.6 101.352 ;
    END
  END q[139]
  PIN q[13]
    DIRECTION OUTPUT ;
    USE SIGNAL ;
    PORT
      LAYER M4 ;
        RECT  21.516 11.76 21.6 11.784 ;
    END
  END q[13]
  PIN q[140]
    DIRECTION OUTPUT ;
    USE SIGNAL ;
    PORT
      LAYER M4 ;
        RECT  21.516 102.048 21.6 102.072 ;
    END
  END q[140]
  PIN q[141]
    DIRECTION OUTPUT ;
    USE SIGNAL ;
    PORT
      LAYER M4 ;
        RECT  21.516 102.768 21.6 102.792 ;
    END
  END q[141]
  PIN q[142]
    DIRECTION OUTPUT ;
    USE SIGNAL ;
    PORT
      LAYER M4 ;
        RECT  21.516 103.44 21.6 103.464 ;
    END
  END q[142]
  PIN q[143]
    DIRECTION OUTPUT ;
    USE SIGNAL ;
    PORT
      LAYER M4 ;
        RECT  21.516 104.16 21.6 104.184 ;
    END
  END q[143]
  PIN q[144]
    DIRECTION OUTPUT ;
    USE SIGNAL ;
    PORT
      LAYER M4 ;
        RECT  21.516 104.88 21.6 104.904 ;
    END
  END q[144]
  PIN q[145]
    DIRECTION OUTPUT ;
    USE SIGNAL ;
    PORT
      LAYER M4 ;
        RECT  21.516 105.6 21.6 105.624 ;
    END
  END q[145]
  PIN q[146]
    DIRECTION OUTPUT ;
    USE SIGNAL ;
    PORT
      LAYER M4 ;
        RECT  21.516 106.32 21.6 106.344 ;
    END
  END q[146]
  PIN q[147]
    DIRECTION OUTPUT ;
    USE SIGNAL ;
    PORT
      LAYER M4 ;
        RECT  21.516 106.992 21.6 107.016 ;
    END
  END q[147]
  PIN q[148]
    DIRECTION OUTPUT ;
    USE SIGNAL ;
    PORT
      LAYER M4 ;
        RECT  21.516 107.712 21.6 107.736 ;
    END
  END q[148]
  PIN q[149]
    DIRECTION OUTPUT ;
    USE SIGNAL ;
    PORT
      LAYER M4 ;
        RECT  21.516 108.432 21.6 108.456 ;
    END
  END q[149]
  PIN q[14]
    DIRECTION OUTPUT ;
    USE SIGNAL ;
    PORT
      LAYER M4 ;
        RECT  21.516 12.48 21.6 12.504 ;
    END
  END q[14]
  PIN q[150]
    DIRECTION OUTPUT ;
    USE SIGNAL ;
    PORT
      LAYER M4 ;
        RECT  21.516 109.152 21.6 109.176 ;
    END
  END q[150]
  PIN q[151]
    DIRECTION OUTPUT ;
    USE SIGNAL ;
    PORT
      LAYER M4 ;
        RECT  21.516 109.872 21.6 109.896 ;
    END
  END q[151]
  PIN q[152]
    DIRECTION OUTPUT ;
    USE SIGNAL ;
    PORT
      LAYER M4 ;
        RECT  21.516 110.592 21.6 110.616 ;
    END
  END q[152]
  PIN q[153]
    DIRECTION OUTPUT ;
    USE SIGNAL ;
    PORT
      LAYER M4 ;
        RECT  21.516 111.264 21.6 111.288 ;
    END
  END q[153]
  PIN q[154]
    DIRECTION OUTPUT ;
    USE SIGNAL ;
    PORT
      LAYER M4 ;
        RECT  21.516 111.984 21.6 112.008 ;
    END
  END q[154]
  PIN q[155]
    DIRECTION OUTPUT ;
    USE SIGNAL ;
    PORT
      LAYER M4 ;
        RECT  21.516 112.704 21.6 112.728 ;
    END
  END q[155]
  PIN q[156]
    DIRECTION OUTPUT ;
    USE SIGNAL ;
    PORT
      LAYER M4 ;
        RECT  21.516 113.424 21.6 113.448 ;
    END
  END q[156]
  PIN q[157]
    DIRECTION OUTPUT ;
    USE SIGNAL ;
    PORT
      LAYER M4 ;
        RECT  21.516 114.144 21.6 114.168 ;
    END
  END q[157]
  PIN q[158]
    DIRECTION OUTPUT ;
    USE SIGNAL ;
    PORT
      LAYER M4 ;
        RECT  21.516 114.816 21.6 114.84 ;
    END
  END q[158]
  PIN q[159]
    DIRECTION OUTPUT ;
    USE SIGNAL ;
    PORT
      LAYER M4 ;
        RECT  21.516 115.536 21.6 115.56 ;
    END
  END q[159]
  PIN q[15]
    DIRECTION OUTPUT ;
    USE SIGNAL ;
    PORT
      LAYER M4 ;
        RECT  21.516 13.152 21.6 13.176 ;
    END
  END q[15]
  PIN q[160]
    DIRECTION OUTPUT ;
    USE SIGNAL ;
    PORT
      LAYER M4 ;
        RECT  21.516 116.256 21.6 116.28 ;
    END
  END q[160]
  PIN q[161]
    DIRECTION OUTPUT ;
    USE SIGNAL ;
    PORT
      LAYER M4 ;
        RECT  21.516 116.976 21.6 117 ;
    END
  END q[161]
  PIN q[162]
    DIRECTION OUTPUT ;
    USE SIGNAL ;
    PORT
      LAYER M4 ;
        RECT  21.516 117.696 21.6 117.72 ;
    END
  END q[162]
  PIN q[163]
    DIRECTION OUTPUT ;
    USE SIGNAL ;
    PORT
      LAYER M4 ;
        RECT  21.516 118.368 21.6 118.392 ;
    END
  END q[163]
  PIN q[164]
    DIRECTION OUTPUT ;
    USE SIGNAL ;
    PORT
      LAYER M4 ;
        RECT  21.516 119.088 21.6 119.112 ;
    END
  END q[164]
  PIN q[165]
    DIRECTION OUTPUT ;
    USE SIGNAL ;
    PORT
      LAYER M4 ;
        RECT  21.516 119.808 21.6 119.832 ;
    END
  END q[165]
  PIN q[166]
    DIRECTION OUTPUT ;
    USE SIGNAL ;
    PORT
      LAYER M4 ;
        RECT  21.516 120.528 21.6 120.552 ;
    END
  END q[166]
  PIN q[167]
    DIRECTION OUTPUT ;
    USE SIGNAL ;
    PORT
      LAYER M4 ;
        RECT  21.516 121.248 21.6 121.272 ;
    END
  END q[167]
  PIN q[168]
    DIRECTION OUTPUT ;
    USE SIGNAL ;
    PORT
      LAYER M4 ;
        RECT  21.516 121.968 21.6 121.992 ;
    END
  END q[168]
  PIN q[169]
    DIRECTION OUTPUT ;
    USE SIGNAL ;
    PORT
      LAYER M4 ;
        RECT  21.516 122.64 21.6 122.664 ;
    END
  END q[169]
  PIN q[16]
    DIRECTION OUTPUT ;
    USE SIGNAL ;
    PORT
      LAYER M4 ;
        RECT  21.516 13.872 21.6 13.896 ;
    END
  END q[16]
  PIN q[170]
    DIRECTION OUTPUT ;
    USE SIGNAL ;
    PORT
      LAYER M4 ;
        RECT  21.516 123.36 21.6 123.384 ;
    END
  END q[170]
  PIN q[171]
    DIRECTION OUTPUT ;
    USE SIGNAL ;
    PORT
      LAYER M4 ;
        RECT  21.516 124.08 21.6 124.104 ;
    END
  END q[171]
  PIN q[172]
    DIRECTION OUTPUT ;
    USE SIGNAL ;
    PORT
      LAYER M4 ;
        RECT  21.516 124.8 21.6 124.824 ;
    END
  END q[172]
  PIN q[173]
    DIRECTION OUTPUT ;
    USE SIGNAL ;
    PORT
      LAYER M4 ;
        RECT  21.516 125.52 21.6 125.544 ;
    END
  END q[173]
  PIN q[174]
    DIRECTION OUTPUT ;
    USE SIGNAL ;
    PORT
      LAYER M4 ;
        RECT  21.516 126.192 21.6 126.216 ;
    END
  END q[174]
  PIN q[175]
    DIRECTION OUTPUT ;
    USE SIGNAL ;
    PORT
      LAYER M4 ;
        RECT  21.516 126.912 21.6 126.936 ;
    END
  END q[175]
  PIN q[176]
    DIRECTION OUTPUT ;
    USE SIGNAL ;
    PORT
      LAYER M4 ;
        RECT  21.516 127.632 21.6 127.656 ;
    END
  END q[176]
  PIN q[177]
    DIRECTION OUTPUT ;
    USE SIGNAL ;
    PORT
      LAYER M4 ;
        RECT  21.516 128.352 21.6 128.376 ;
    END
  END q[177]
  PIN q[178]
    DIRECTION OUTPUT ;
    USE SIGNAL ;
    PORT
      LAYER M4 ;
        RECT  21.516 129.072 21.6 129.096 ;
    END
  END q[178]
  PIN q[179]
    DIRECTION OUTPUT ;
    USE SIGNAL ;
    PORT
      LAYER M4 ;
        RECT  21.516 129.744 21.6 129.768 ;
    END
  END q[179]
  PIN q[17]
    DIRECTION OUTPUT ;
    USE SIGNAL ;
    PORT
      LAYER M4 ;
        RECT  21.516 14.592 21.6 14.616 ;
    END
  END q[17]
  PIN q[180]
    DIRECTION OUTPUT ;
    USE SIGNAL ;
    PORT
      LAYER M4 ;
        RECT  21.516 130.464 21.6 130.488 ;
    END
  END q[180]
  PIN q[181]
    DIRECTION OUTPUT ;
    USE SIGNAL ;
    PORT
      LAYER M4 ;
        RECT  21.516 131.184 21.6 131.208 ;
    END
  END q[181]
  PIN q[182]
    DIRECTION OUTPUT ;
    USE SIGNAL ;
    PORT
      LAYER M4 ;
        RECT  21.516 131.904 21.6 131.928 ;
    END
  END q[182]
  PIN q[183]
    DIRECTION OUTPUT ;
    USE SIGNAL ;
    PORT
      LAYER M4 ;
        RECT  21.516 132.624 21.6 132.648 ;
    END
  END q[183]
  PIN q[184]
    DIRECTION OUTPUT ;
    USE SIGNAL ;
    PORT
      LAYER M4 ;
        RECT  21.516 133.296 21.6 133.32 ;
    END
  END q[184]
  PIN q[185]
    DIRECTION OUTPUT ;
    USE SIGNAL ;
    PORT
      LAYER M4 ;
        RECT  21.516 134.016 21.6 134.04 ;
    END
  END q[185]
  PIN q[186]
    DIRECTION OUTPUT ;
    USE SIGNAL ;
    PORT
      LAYER M4 ;
        RECT  21.516 134.736 21.6 134.76 ;
    END
  END q[186]
  PIN q[187]
    DIRECTION OUTPUT ;
    USE SIGNAL ;
    PORT
      LAYER M4 ;
        RECT  21.516 135.456 21.6 135.48 ;
    END
  END q[187]
  PIN q[188]
    DIRECTION OUTPUT ;
    USE SIGNAL ;
    PORT
      LAYER M4 ;
        RECT  21.516 136.176 21.6 136.2 ;
    END
  END q[188]
  PIN q[189]
    DIRECTION OUTPUT ;
    USE SIGNAL ;
    PORT
      LAYER M4 ;
        RECT  21.516 136.896 21.6 136.92 ;
    END
  END q[189]
  PIN q[18]
    DIRECTION OUTPUT ;
    USE SIGNAL ;
    PORT
      LAYER M4 ;
        RECT  21.516 15.312 21.6 15.336 ;
    END
  END q[18]
  PIN q[190]
    DIRECTION OUTPUT ;
    USE SIGNAL ;
    PORT
      LAYER M4 ;
        RECT  21.516 137.568 21.6 137.592 ;
    END
  END q[190]
  PIN q[191]
    DIRECTION OUTPUT ;
    USE SIGNAL ;
    PORT
      LAYER M4 ;
        RECT  21.516 138.288 21.6 138.312 ;
    END
  END q[191]
  PIN q[192]
    DIRECTION OUTPUT ;
    USE SIGNAL ;
    PORT
      LAYER M4 ;
        RECT  21.516 139.008 21.6 139.032 ;
    END
  END q[192]
  PIN q[193]
    DIRECTION OUTPUT ;
    USE SIGNAL ;
    PORT
      LAYER M4 ;
        RECT  21.516 139.728 21.6 139.752 ;
    END
  END q[193]
  PIN q[194]
    DIRECTION OUTPUT ;
    USE SIGNAL ;
    PORT
      LAYER M4 ;
        RECT  21.516 140.448 21.6 140.472 ;
    END
  END q[194]
  PIN q[195]
    DIRECTION OUTPUT ;
    USE SIGNAL ;
    PORT
      LAYER M4 ;
        RECT  21.516 141.12 21.6 141.144 ;
    END
  END q[195]
  PIN q[196]
    DIRECTION OUTPUT ;
    USE SIGNAL ;
    PORT
      LAYER M4 ;
        RECT  21.516 141.84 21.6 141.864 ;
    END
  END q[196]
  PIN q[197]
    DIRECTION OUTPUT ;
    USE SIGNAL ;
    PORT
      LAYER M4 ;
        RECT  21.516 142.56 21.6 142.584 ;
    END
  END q[197]
  PIN q[198]
    DIRECTION OUTPUT ;
    USE SIGNAL ;
    PORT
      LAYER M4 ;
        RECT  21.516 143.28 21.6 143.304 ;
    END
  END q[198]
  PIN q[19]
    DIRECTION OUTPUT ;
    USE SIGNAL ;
    PORT
      LAYER M4 ;
        RECT  21.516 16.032 21.6 16.056 ;
    END
  END q[19]
  PIN q[1]
    DIRECTION OUTPUT ;
    USE SIGNAL ;
    PORT
      LAYER M4 ;
        RECT  21.516 3.216 21.6 3.24 ;
    END
  END q[1]
  PIN q[20]
    DIRECTION OUTPUT ;
    USE SIGNAL ;
    PORT
      LAYER M4 ;
        RECT  21.516 16.704 21.6 16.728 ;
    END
  END q[20]
  PIN q[21]
    DIRECTION OUTPUT ;
    USE SIGNAL ;
    PORT
      LAYER M4 ;
        RECT  21.516 17.424 21.6 17.448 ;
    END
  END q[21]
  PIN q[22]
    DIRECTION OUTPUT ;
    USE SIGNAL ;
    PORT
      LAYER M4 ;
        RECT  21.516 18.144 21.6 18.168 ;
    END
  END q[22]
  PIN q[23]
    DIRECTION OUTPUT ;
    USE SIGNAL ;
    PORT
      LAYER M4 ;
        RECT  21.516 18.864 21.6 18.888 ;
    END
  END q[23]
  PIN q[24]
    DIRECTION OUTPUT ;
    USE SIGNAL ;
    PORT
      LAYER M4 ;
        RECT  21.516 19.584 21.6 19.608 ;
    END
  END q[24]
  PIN q[25]
    DIRECTION OUTPUT ;
    USE SIGNAL ;
    PORT
      LAYER M4 ;
        RECT  21.516 20.256 21.6 20.28 ;
    END
  END q[25]
  PIN q[26]
    DIRECTION OUTPUT ;
    USE SIGNAL ;
    PORT
      LAYER M4 ;
        RECT  21.516 20.976 21.6 21 ;
    END
  END q[26]
  PIN q[27]
    DIRECTION OUTPUT ;
    USE SIGNAL ;
    PORT
      LAYER M4 ;
        RECT  21.516 21.696 21.6 21.72 ;
    END
  END q[27]
  PIN q[28]
    DIRECTION OUTPUT ;
    USE SIGNAL ;
    PORT
      LAYER M4 ;
        RECT  21.516 22.416 21.6 22.44 ;
    END
  END q[28]
  PIN q[29]
    DIRECTION OUTPUT ;
    USE SIGNAL ;
    PORT
      LAYER M4 ;
        RECT  21.516 23.136 21.6 23.16 ;
    END
  END q[29]
  PIN q[2]
    DIRECTION OUTPUT ;
    USE SIGNAL ;
    PORT
      LAYER M4 ;
        RECT  21.516 3.936 21.6 3.96 ;
    END
  END q[2]
  PIN q[30]
    DIRECTION OUTPUT ;
    USE SIGNAL ;
    PORT
      LAYER M4 ;
        RECT  21.516 23.856 21.6 23.88 ;
    END
  END q[30]
  PIN q[31]
    DIRECTION OUTPUT ;
    USE SIGNAL ;
    PORT
      LAYER M4 ;
        RECT  21.516 24.528 21.6 24.552 ;
    END
  END q[31]
  PIN q[32]
    DIRECTION OUTPUT ;
    USE SIGNAL ;
    PORT
      LAYER M4 ;
        RECT  21.516 25.248 21.6 25.272 ;
    END
  END q[32]
  PIN q[33]
    DIRECTION OUTPUT ;
    USE SIGNAL ;
    PORT
      LAYER M4 ;
        RECT  21.516 25.968 21.6 25.992 ;
    END
  END q[33]
  PIN q[34]
    DIRECTION OUTPUT ;
    USE SIGNAL ;
    PORT
      LAYER M4 ;
        RECT  21.516 26.688 21.6 26.712 ;
    END
  END q[34]
  PIN q[35]
    DIRECTION OUTPUT ;
    USE SIGNAL ;
    PORT
      LAYER M4 ;
        RECT  21.516 27.408 21.6 27.432 ;
    END
  END q[35]
  PIN q[36]
    DIRECTION OUTPUT ;
    USE SIGNAL ;
    PORT
      LAYER M4 ;
        RECT  21.516 28.08 21.6 28.104 ;
    END
  END q[36]
  PIN q[37]
    DIRECTION OUTPUT ;
    USE SIGNAL ;
    PORT
      LAYER M4 ;
        RECT  21.516 28.8 21.6 28.824 ;
    END
  END q[37]
  PIN q[38]
    DIRECTION OUTPUT ;
    USE SIGNAL ;
    PORT
      LAYER M4 ;
        RECT  21.516 29.52 21.6 29.544 ;
    END
  END q[38]
  PIN q[39]
    DIRECTION OUTPUT ;
    USE SIGNAL ;
    PORT
      LAYER M4 ;
        RECT  21.516 30.24 21.6 30.264 ;
    END
  END q[39]
  PIN q[3]
    DIRECTION OUTPUT ;
    USE SIGNAL ;
    PORT
      LAYER M4 ;
        RECT  21.516 4.656 21.6 4.68 ;
    END
  END q[3]
  PIN q[40]
    DIRECTION OUTPUT ;
    USE SIGNAL ;
    PORT
      LAYER M4 ;
        RECT  21.516 30.96 21.6 30.984 ;
    END
  END q[40]
  PIN q[41]
    DIRECTION OUTPUT ;
    USE SIGNAL ;
    PORT
      LAYER M4 ;
        RECT  21.516 31.632 21.6 31.656 ;
    END
  END q[41]
  PIN q[42]
    DIRECTION OUTPUT ;
    USE SIGNAL ;
    PORT
      LAYER M4 ;
        RECT  21.516 32.352 21.6 32.376 ;
    END
  END q[42]
  PIN q[43]
    DIRECTION OUTPUT ;
    USE SIGNAL ;
    PORT
      LAYER M4 ;
        RECT  21.516 33.072 21.6 33.096 ;
    END
  END q[43]
  PIN q[44]
    DIRECTION OUTPUT ;
    USE SIGNAL ;
    PORT
      LAYER M4 ;
        RECT  21.516 33.792 21.6 33.816 ;
    END
  END q[44]
  PIN q[45]
    DIRECTION OUTPUT ;
    USE SIGNAL ;
    PORT
      LAYER M4 ;
        RECT  21.516 34.512 21.6 34.536 ;
    END
  END q[45]
  PIN q[46]
    DIRECTION OUTPUT ;
    USE SIGNAL ;
    PORT
      LAYER M4 ;
        RECT  21.516 35.184 21.6 35.208 ;
    END
  END q[46]
  PIN q[47]
    DIRECTION OUTPUT ;
    USE SIGNAL ;
    PORT
      LAYER M4 ;
        RECT  21.516 35.904 21.6 35.928 ;
    END
  END q[47]
  PIN q[48]
    DIRECTION OUTPUT ;
    USE SIGNAL ;
    PORT
      LAYER M4 ;
        RECT  21.516 36.624 21.6 36.648 ;
    END
  END q[48]
  PIN q[49]
    DIRECTION OUTPUT ;
    USE SIGNAL ;
    PORT
      LAYER M4 ;
        RECT  21.516 37.344 21.6 37.368 ;
    END
  END q[49]
  PIN q[4]
    DIRECTION OUTPUT ;
    USE SIGNAL ;
    PORT
      LAYER M4 ;
        RECT  21.516 5.328 21.6 5.352 ;
    END
  END q[4]
  PIN q[50]
    DIRECTION OUTPUT ;
    USE SIGNAL ;
    PORT
      LAYER M4 ;
        RECT  21.516 38.064 21.6 38.088 ;
    END
  END q[50]
  PIN q[51]
    DIRECTION OUTPUT ;
    USE SIGNAL ;
    PORT
      LAYER M4 ;
        RECT  21.516 38.784 21.6 38.808 ;
    END
  END q[51]
  PIN q[52]
    DIRECTION OUTPUT ;
    USE SIGNAL ;
    PORT
      LAYER M4 ;
        RECT  21.516 39.456 21.6 39.48 ;
    END
  END q[52]
  PIN q[53]
    DIRECTION OUTPUT ;
    USE SIGNAL ;
    PORT
      LAYER M4 ;
        RECT  21.516 40.176 21.6 40.2 ;
    END
  END q[53]
  PIN q[54]
    DIRECTION OUTPUT ;
    USE SIGNAL ;
    PORT
      LAYER M4 ;
        RECT  21.516 40.896 21.6 40.92 ;
    END
  END q[54]
  PIN q[55]
    DIRECTION OUTPUT ;
    USE SIGNAL ;
    PORT
      LAYER M4 ;
        RECT  21.516 41.616 21.6 41.64 ;
    END
  END q[55]
  PIN q[56]
    DIRECTION OUTPUT ;
    USE SIGNAL ;
    PORT
      LAYER M4 ;
        RECT  21.516 42.336 21.6 42.36 ;
    END
  END q[56]
  PIN q[57]
    DIRECTION OUTPUT ;
    USE SIGNAL ;
    PORT
      LAYER M4 ;
        RECT  21.516 43.008 21.6 43.032 ;
    END
  END q[57]
  PIN q[58]
    DIRECTION OUTPUT ;
    USE SIGNAL ;
    PORT
      LAYER M4 ;
        RECT  21.516 43.728 21.6 43.752 ;
    END
  END q[58]
  PIN q[59]
    DIRECTION OUTPUT ;
    USE SIGNAL ;
    PORT
      LAYER M4 ;
        RECT  21.516 44.448 21.6 44.472 ;
    END
  END q[59]
  PIN q[5]
    DIRECTION OUTPUT ;
    USE SIGNAL ;
    PORT
      LAYER M4 ;
        RECT  21.516 6.048 21.6 6.072 ;
    END
  END q[5]
  PIN q[60]
    DIRECTION OUTPUT ;
    USE SIGNAL ;
    PORT
      LAYER M4 ;
        RECT  21.516 45.168 21.6 45.192 ;
    END
  END q[60]
  PIN q[61]
    DIRECTION OUTPUT ;
    USE SIGNAL ;
    PORT
      LAYER M4 ;
        RECT  21.516 45.888 21.6 45.912 ;
    END
  END q[61]
  PIN q[62]
    DIRECTION OUTPUT ;
    USE SIGNAL ;
    PORT
      LAYER M4 ;
        RECT  21.516 46.56 21.6 46.584 ;
    END
  END q[62]
  PIN q[63]
    DIRECTION OUTPUT ;
    USE SIGNAL ;
    PORT
      LAYER M4 ;
        RECT  21.516 47.28 21.6 47.304 ;
    END
  END q[63]
  PIN q[64]
    DIRECTION OUTPUT ;
    USE SIGNAL ;
    PORT
      LAYER M4 ;
        RECT  21.516 48 21.6 48.024 ;
    END
  END q[64]
  PIN q[65]
    DIRECTION OUTPUT ;
    USE SIGNAL ;
    PORT
      LAYER M4 ;
        RECT  21.516 48.72 21.6 48.744 ;
    END
  END q[65]
  PIN q[66]
    DIRECTION OUTPUT ;
    USE SIGNAL ;
    PORT
      LAYER M4 ;
        RECT  21.516 49.44 21.6 49.464 ;
    END
  END q[66]
  PIN q[67]
    DIRECTION OUTPUT ;
    USE SIGNAL ;
    PORT
      LAYER M4 ;
        RECT  21.516 50.16 21.6 50.184 ;
    END
  END q[67]
  PIN q[68]
    DIRECTION OUTPUT ;
    USE SIGNAL ;
    PORT
      LAYER M4 ;
        RECT  21.516 50.832 21.6 50.856 ;
    END
  END q[68]
  PIN q[69]
    DIRECTION OUTPUT ;
    USE SIGNAL ;
    PORT
      LAYER M4 ;
        RECT  21.516 51.552 21.6 51.576 ;
    END
  END q[69]
  PIN q[6]
    DIRECTION OUTPUT ;
    USE SIGNAL ;
    PORT
      LAYER M4 ;
        RECT  21.516 6.768 21.6 6.792 ;
    END
  END q[6]
  PIN q[70]
    DIRECTION OUTPUT ;
    USE SIGNAL ;
    PORT
      LAYER M4 ;
        RECT  21.516 52.272 21.6 52.296 ;
    END
  END q[70]
  PIN q[71]
    DIRECTION OUTPUT ;
    USE SIGNAL ;
    PORT
      LAYER M4 ;
        RECT  21.516 52.992 21.6 53.016 ;
    END
  END q[71]
  PIN q[72]
    DIRECTION OUTPUT ;
    USE SIGNAL ;
    PORT
      LAYER M4 ;
        RECT  21.516 53.712 21.6 53.736 ;
    END
  END q[72]
  PIN q[73]
    DIRECTION OUTPUT ;
    USE SIGNAL ;
    PORT
      LAYER M4 ;
        RECT  21.516 54.384 21.6 54.408 ;
    END
  END q[73]
  PIN q[74]
    DIRECTION OUTPUT ;
    USE SIGNAL ;
    PORT
      LAYER M4 ;
        RECT  21.516 55.104 21.6 55.128 ;
    END
  END q[74]
  PIN q[75]
    DIRECTION OUTPUT ;
    USE SIGNAL ;
    PORT
      LAYER M4 ;
        RECT  21.516 55.824 21.6 55.848 ;
    END
  END q[75]
  PIN q[76]
    DIRECTION OUTPUT ;
    USE SIGNAL ;
    PORT
      LAYER M4 ;
        RECT  21.516 56.544 21.6 56.568 ;
    END
  END q[76]
  PIN q[77]
    DIRECTION OUTPUT ;
    USE SIGNAL ;
    PORT
      LAYER M4 ;
        RECT  21.516 57.264 21.6 57.288 ;
    END
  END q[77]
  PIN q[78]
    DIRECTION OUTPUT ;
    USE SIGNAL ;
    PORT
      LAYER M4 ;
        RECT  21.516 57.936 21.6 57.96 ;
    END
  END q[78]
  PIN q[79]
    DIRECTION OUTPUT ;
    USE SIGNAL ;
    PORT
      LAYER M4 ;
        RECT  21.516 58.656 21.6 58.68 ;
    END
  END q[79]
  PIN q[7]
    DIRECTION OUTPUT ;
    USE SIGNAL ;
    PORT
      LAYER M4 ;
        RECT  21.516 7.488 21.6 7.512 ;
    END
  END q[7]
  PIN q[80]
    DIRECTION OUTPUT ;
    USE SIGNAL ;
    PORT
      LAYER M4 ;
        RECT  21.516 59.376 21.6 59.4 ;
    END
  END q[80]
  PIN q[81]
    DIRECTION OUTPUT ;
    USE SIGNAL ;
    PORT
      LAYER M4 ;
        RECT  21.516 60.096 21.6 60.12 ;
    END
  END q[81]
  PIN q[82]
    DIRECTION OUTPUT ;
    USE SIGNAL ;
    PORT
      LAYER M4 ;
        RECT  21.516 60.816 21.6 60.84 ;
    END
  END q[82]
  PIN q[83]
    DIRECTION OUTPUT ;
    USE SIGNAL ;
    PORT
      LAYER M4 ;
        RECT  21.516 61.536 21.6 61.56 ;
    END
  END q[83]
  PIN q[84]
    DIRECTION OUTPUT ;
    USE SIGNAL ;
    PORT
      LAYER M4 ;
        RECT  21.516 62.208 21.6 62.232 ;
    END
  END q[84]
  PIN q[85]
    DIRECTION OUTPUT ;
    USE SIGNAL ;
    PORT
      LAYER M4 ;
        RECT  21.516 62.928 21.6 62.952 ;
    END
  END q[85]
  PIN q[86]
    DIRECTION OUTPUT ;
    USE SIGNAL ;
    PORT
      LAYER M4 ;
        RECT  21.516 63.648 21.6 63.672 ;
    END
  END q[86]
  PIN q[87]
    DIRECTION OUTPUT ;
    USE SIGNAL ;
    PORT
      LAYER M4 ;
        RECT  21.516 64.368 21.6 64.392 ;
    END
  END q[87]
  PIN q[88]
    DIRECTION OUTPUT ;
    USE SIGNAL ;
    PORT
      LAYER M4 ;
        RECT  21.516 65.088 21.6 65.112 ;
    END
  END q[88]
  PIN q[89]
    DIRECTION OUTPUT ;
    USE SIGNAL ;
    PORT
      LAYER M4 ;
        RECT  21.516 65.76 21.6 65.784 ;
    END
  END q[89]
  PIN q[8]
    DIRECTION OUTPUT ;
    USE SIGNAL ;
    PORT
      LAYER M4 ;
        RECT  21.516 8.208 21.6 8.232 ;
    END
  END q[8]
  PIN q[90]
    DIRECTION OUTPUT ;
    USE SIGNAL ;
    PORT
      LAYER M4 ;
        RECT  21.516 66.48 21.6 66.504 ;
    END
  END q[90]
  PIN q[91]
    DIRECTION OUTPUT ;
    USE SIGNAL ;
    PORT
      LAYER M4 ;
        RECT  21.516 67.2 21.6 67.224 ;
    END
  END q[91]
  PIN q[92]
    DIRECTION OUTPUT ;
    USE SIGNAL ;
    PORT
      LAYER M4 ;
        RECT  21.516 67.92 21.6 67.944 ;
    END
  END q[92]
  PIN q[93]
    DIRECTION OUTPUT ;
    USE SIGNAL ;
    PORT
      LAYER M4 ;
        RECT  21.516 68.64 21.6 68.664 ;
    END
  END q[93]
  PIN q[94]
    DIRECTION OUTPUT ;
    USE SIGNAL ;
    PORT
      LAYER M4 ;
        RECT  21.516 69.312 21.6 69.336 ;
    END
  END q[94]
  PIN q[95]
    DIRECTION OUTPUT ;
    USE SIGNAL ;
    PORT
      LAYER M4 ;
        RECT  21.516 70.032 21.6 70.056 ;
    END
  END q[95]
  PIN q[96]
    DIRECTION OUTPUT ;
    USE SIGNAL ;
    PORT
      LAYER M4 ;
        RECT  21.516 70.752 21.6 70.776 ;
    END
  END q[96]
  PIN q[97]
    DIRECTION OUTPUT ;
    USE SIGNAL ;
    PORT
      LAYER M4 ;
        RECT  21.516 71.472 21.6 71.496 ;
    END
  END q[97]
  PIN q[98]
    DIRECTION OUTPUT ;
    USE SIGNAL ;
    PORT
      LAYER M4 ;
        RECT  21.516 72.192 21.6 72.216 ;
    END
  END q[98]
  PIN q[99]
    DIRECTION OUTPUT ;
    USE SIGNAL ;
    PORT
      LAYER M4 ;
        RECT  21.516 72.912 21.6 72.936 ;
    END
  END q[99]
  PIN q[9]
    DIRECTION OUTPUT ;
    USE SIGNAL ;
    PORT
      LAYER M4 ;
        RECT  21.516 8.88 21.6 8.904 ;
    END
  END q[9]
  PIN VDD
    DIRECTION INOUT ;
    USE POWER ;
    PORT
      LAYER M5 ;
        RECT  18.792 2.151 18.912 144.729 ;
        RECT  16.092 2.151 16.212 144.729 ;
        RECT  13.392 2.151 13.512 144.729 ;
        RECT  10.692 2.151 10.812 144.729 ;
        RECT  7.992 2.151 8.112 144.729 ;
        RECT  5.292 2.151 5.412 144.729 ;
        RECT  2.592 2.151 2.712 144.729 ;
    END
  END VDD
  PIN VSS
    DIRECTION INOUT ;
    USE GROUND ;
    PORT
      LAYER M5 ;
        RECT  18.6 2.137 18.72 144.743 ;
        RECT  15.9 2.137 16.02 144.743 ;
        RECT  13.2 2.137 13.32 144.743 ;
        RECT  10.5 2.137 10.62 144.743 ;
        RECT  7.8 2.137 7.92 144.743 ;
        RECT  5.1 2.137 5.22 144.743 ;
        RECT  2.4 2.137 2.52 144.743 ;
    END
  END VSS
  # OT_OBS_CLOSED layer=M5 d_um=1.536 added=38
  OBS
    LAYER RVTN ;
     RECT  2.16 2.16 19.44 2.295 ;
     RECT  2.16 2.565 19.44 2.835 ;
     RECT  2.16 3.105 19.44 3.375 ;
     RECT  2.16 3.645 19.44 3.915 ;
     RECT  2.16 4.185 19.44 4.455 ;
     RECT  2.16 4.725 19.44 4.995 ;
     RECT  2.16 5.265 19.44 5.535 ;
     RECT  2.16 5.805 19.44 6.075 ;
     RECT  2.16 6.345 19.44 6.615 ;
     RECT  2.16 6.885 19.44 7.155 ;
     RECT  2.16 7.425 19.44 7.695 ;
     RECT  2.16 7.965 19.44 8.235 ;
     RECT  2.16 8.505 19.44 8.775 ;
     RECT  2.16 9.045 19.44 9.315 ;
     RECT  2.16 9.585 19.44 9.855 ;
     RECT  2.16 10.125 19.44 10.395 ;
     RECT  2.16 10.665 19.44 10.935 ;
     RECT  2.16 11.205 19.44 11.475 ;
     RECT  2.16 11.745 19.44 12.015 ;
     RECT  2.16 12.285 19.44 12.555 ;
     RECT  2.16 12.825 19.44 13.095 ;
     RECT  2.16 13.365 19.44 13.635 ;
     RECT  2.16 13.905 19.44 14.175 ;
     RECT  2.16 14.445 19.44 14.715 ;
     RECT  2.16 14.985 19.44 15.255 ;
     RECT  2.16 15.525 19.44 15.795 ;
     RECT  2.16 16.065 19.44 16.335 ;
     RECT  2.16 16.605 19.44 16.875 ;
     RECT  2.16 17.145 19.44 17.415 ;
     RECT  2.16 17.685 19.44 17.955 ;
     RECT  2.16 18.225 19.44 18.495 ;
     RECT  2.16 18.765 19.44 19.035 ;
     RECT  2.16 19.305 19.44 19.575 ;
     RECT  2.16 19.845 19.44 20.115 ;
     RECT  2.16 20.385 19.44 20.655 ;
     RECT  2.16 20.925 19.44 21.195 ;
     RECT  2.16 21.465 19.44 21.735 ;
     RECT  2.16 22.005 19.44 22.275 ;
     RECT  2.16 22.545 19.44 22.815 ;
     RECT  2.16 23.085 19.44 23.355 ;
     RECT  2.16 23.625 19.44 23.895 ;
     RECT  2.16 24.165 19.44 24.435 ;
     RECT  2.16 24.705 19.44 24.975 ;
     RECT  2.16 25.245 19.44 25.515 ;
     RECT  2.16 25.785 19.44 26.055 ;
     RECT  2.16 26.325 19.44 26.595 ;
     RECT  2.16 26.865 19.44 27.135 ;
     RECT  2.16 27.405 19.44 27.675 ;
     RECT  2.16 27.945 19.44 28.215 ;
     RECT  2.16 28.485 19.44 28.755 ;
     RECT  2.16 29.025 19.44 29.295 ;
     RECT  2.16 29.565 19.44 29.835 ;
     RECT  2.16 30.105 19.44 30.375 ;
     RECT  2.16 30.645 19.44 30.915 ;
     RECT  2.16 31.185 19.44 31.455 ;
     RECT  2.16 31.725 19.44 31.995 ;
     RECT  2.16 32.265 19.44 32.535 ;
     RECT  2.16 32.805 19.44 33.075 ;
     RECT  2.16 33.345 19.44 33.615 ;
     RECT  2.16 33.885 19.44 34.155 ;
     RECT  2.16 34.425 19.44 34.695 ;
     RECT  2.16 34.965 19.44 35.235 ;
     RECT  2.16 35.505 19.44 35.775 ;
     RECT  2.16 36.045 19.44 36.315 ;
     RECT  2.16 36.585 19.44 36.855 ;
     RECT  2.16 37.125 19.44 37.395 ;
     RECT  2.16 37.665 19.44 37.935 ;
     RECT  2.16 38.205 19.44 38.475 ;
     RECT  2.16 38.745 19.44 39.015 ;
     RECT  2.16 39.285 19.44 39.555 ;
     RECT  2.16 39.825 19.44 40.095 ;
     RECT  2.16 40.365 19.44 40.635 ;
     RECT  2.16 40.905 19.44 41.175 ;
     RECT  2.16 41.445 19.44 41.715 ;
     RECT  2.16 41.985 19.44 42.255 ;
     RECT  2.16 42.525 19.44 42.795 ;
     RECT  2.16 43.065 19.44 43.335 ;
     RECT  2.16 43.605 19.44 43.875 ;
     RECT  2.16 44.145 19.44 44.415 ;
     RECT  2.16 44.685 19.44 44.955 ;
     RECT  2.16 45.225 19.44 45.495 ;
     RECT  2.16 45.765 19.44 46.035 ;
     RECT  2.16 46.305 19.44 46.575 ;
     RECT  2.16 46.845 19.44 47.115 ;
     RECT  2.16 47.385 19.44 47.655 ;
     RECT  2.16 47.925 19.44 48.195 ;
     RECT  2.16 48.465 19.44 48.735 ;
     RECT  2.16 49.005 19.44 49.275 ;
     RECT  2.16 49.545 19.44 49.815 ;
     RECT  2.16 50.085 19.44 50.355 ;
     RECT  2.16 50.625 19.44 50.895 ;
     RECT  2.16 51.165 19.44 51.435 ;
     RECT  2.16 51.705 19.44 51.975 ;
     RECT  2.16 52.245 19.44 52.515 ;
     RECT  2.16 52.785 19.44 53.055 ;
     RECT  2.16 53.325 19.44 53.595 ;
     RECT  2.16 53.865 19.44 54.135 ;
     RECT  2.16 54.405 19.44 54.675 ;
     RECT  2.16 54.945 19.44 55.215 ;
     RECT  2.16 55.485 19.44 55.755 ;
     RECT  2.16 56.025 19.44 56.295 ;
     RECT  2.16 56.565 19.44 56.835 ;
     RECT  2.16 57.105 19.44 57.375 ;
     RECT  2.16 57.645 19.44 57.915 ;
     RECT  2.16 58.185 19.44 58.455 ;
     RECT  2.16 58.725 19.44 58.995 ;
     RECT  2.16 59.265 19.44 59.535 ;
     RECT  2.16 59.805 19.44 60.075 ;
     RECT  2.16 60.345 19.44 60.615 ;
     RECT  2.16 60.885 19.44 61.155 ;
     RECT  2.16 61.425 19.44 61.695 ;
     RECT  2.16 61.965 19.44 62.235 ;
     RECT  2.16 62.505 19.44 62.775 ;
     RECT  2.16 63.045 19.44 63.315 ;
     RECT  2.16 63.585 19.44 63.855 ;
     RECT  2.16 64.125 19.44 64.395 ;
     RECT  2.16 64.665 19.44 64.935 ;
     RECT  2.16 65.205 19.44 65.475 ;
     RECT  2.16 65.745 19.44 66.015 ;
     RECT  2.16 66.285 19.44 66.555 ;
     RECT  2.16 66.825 19.44 67.095 ;
     RECT  2.16 67.365 19.44 67.635 ;
     RECT  2.16 67.905 19.44 68.175 ;
     RECT  2.16 68.445 19.44 68.715 ;
     RECT  2.16 68.985 19.44 69.255 ;
     RECT  2.16 69.525 19.44 69.795 ;
     RECT  2.16 70.065 19.44 70.335 ;
     RECT  2.16 70.605 19.44 70.875 ;
     RECT  2.16 71.145 19.44 71.415 ;
     RECT  2.16 71.685 19.44 71.955 ;
     RECT  2.16 72.225 19.44 72.495 ;
     RECT  2.16 72.765 19.44 73.035 ;
     RECT  2.16 73.305 19.44 73.575 ;
     RECT  2.16 73.845 19.44 74.115 ;
     RECT  2.16 74.385 19.44 74.655 ;
     RECT  2.16 74.925 19.44 75.195 ;
     RECT  2.16 75.465 19.44 75.735 ;
     RECT  2.16 76.005 19.44 76.275 ;
     RECT  2.16 76.545 19.44 76.815 ;
     RECT  2.16 77.085 19.44 77.355 ;
     RECT  2.16 77.625 19.44 77.895 ;
     RECT  2.16 78.165 19.44 78.435 ;
     RECT  2.16 78.705 19.44 78.975 ;
     RECT  2.16 79.245 19.44 79.515 ;
     RECT  2.16 79.785 19.44 80.055 ;
     RECT  2.16 80.325 19.44 80.595 ;
     RECT  2.16 80.865 19.44 81.135 ;
     RECT  2.16 81.405 19.44 81.675 ;
     RECT  2.16 81.945 19.44 82.215 ;
     RECT  2.16 82.485 19.44 82.755 ;
     RECT  2.16 83.025 19.44 83.295 ;
     RECT  2.16 83.565 19.44 83.835 ;
     RECT  2.16 84.105 19.44 84.375 ;
     RECT  2.16 84.645 19.44 84.915 ;
     RECT  2.16 85.185 19.44 85.455 ;
     RECT  2.16 85.725 19.44 85.995 ;
     RECT  2.16 86.265 19.44 86.535 ;
     RECT  2.16 86.805 19.44 87.075 ;
     RECT  2.16 87.345 19.44 87.615 ;
     RECT  2.16 87.885 19.44 88.155 ;
     RECT  2.16 88.425 19.44 88.695 ;
     RECT  2.16 88.965 19.44 89.235 ;
     RECT  2.16 89.505 19.44 89.775 ;
     RECT  2.16 90.045 19.44 90.315 ;
     RECT  2.16 90.585 19.44 90.855 ;
     RECT  2.16 91.125 19.44 91.395 ;
     RECT  2.16 91.665 19.44 91.935 ;
     RECT  2.16 92.205 19.44 92.475 ;
     RECT  2.16 92.745 19.44 93.015 ;
     RECT  2.16 93.285 19.44 93.555 ;
     RECT  2.16 93.825 19.44 94.095 ;
     RECT  2.16 94.365 19.44 94.635 ;
     RECT  2.16 94.905 19.44 95.175 ;
     RECT  2.16 95.445 19.44 95.715 ;
     RECT  2.16 95.985 19.44 96.255 ;
     RECT  2.16 96.525 19.44 96.795 ;
     RECT  2.16 97.065 19.44 97.335 ;
     RECT  2.16 97.605 19.44 97.875 ;
     RECT  2.16 98.145 19.44 98.415 ;
     RECT  2.16 98.685 19.44 98.955 ;
     RECT  2.16 99.225 19.44 99.495 ;
     RECT  2.16 99.765 19.44 100.035 ;
     RECT  2.16 100.305 19.44 100.575 ;
     RECT  2.16 100.845 19.44 101.115 ;
     RECT  2.16 101.385 19.44 101.655 ;
     RECT  2.16 101.925 19.44 102.195 ;
     RECT  2.16 102.465 19.44 102.735 ;
     RECT  2.16 103.005 19.44 103.275 ;
     RECT  2.16 103.545 19.44 103.815 ;
     RECT  2.16 104.085 19.44 104.355 ;
     RECT  2.16 104.625 19.44 104.895 ;
     RECT  2.16 105.165 19.44 105.435 ;
     RECT  2.16 105.705 19.44 105.975 ;
     RECT  2.16 106.245 19.44 106.515 ;
     RECT  2.16 106.785 19.44 107.055 ;
     RECT  2.16 107.325 19.44 107.595 ;
     RECT  2.16 107.865 19.44 108.135 ;
     RECT  2.16 108.405 19.44 108.675 ;
     RECT  2.16 108.945 19.44 109.215 ;
     RECT  2.16 109.485 19.44 109.755 ;
     RECT  2.16 110.025 19.44 110.295 ;
     RECT  2.16 110.565 19.44 110.835 ;
     RECT  2.16 111.105 19.44 111.375 ;
     RECT  2.16 111.645 19.44 111.915 ;
     RECT  2.16 112.185 19.44 112.455 ;
     RECT  2.16 112.725 19.44 112.995 ;
     RECT  2.16 113.265 19.44 113.535 ;
     RECT  2.16 113.805 19.44 114.075 ;
     RECT  2.16 114.345 19.44 114.615 ;
     RECT  2.16 114.885 19.44 115.155 ;
     RECT  2.16 115.425 19.44 115.695 ;
     RECT  2.16 115.965 19.44 116.235 ;
     RECT  2.16 116.505 19.44 116.775 ;
     RECT  2.16 117.045 19.44 117.315 ;
     RECT  2.16 117.585 19.44 117.855 ;
     RECT  2.16 118.125 19.44 118.395 ;
     RECT  2.16 118.665 19.44 118.935 ;
     RECT  2.16 119.205 19.44 119.475 ;
     RECT  2.16 119.745 19.44 120.015 ;
     RECT  2.16 120.285 19.44 120.555 ;
     RECT  2.16 120.825 19.44 121.095 ;
     RECT  2.16 121.365 19.44 121.635 ;
     RECT  2.16 121.905 19.44 122.175 ;
     RECT  2.16 122.445 19.44 122.715 ;
     RECT  2.16 122.985 19.44 123.255 ;
     RECT  2.16 123.525 19.44 123.795 ;
     RECT  2.16 124.065 19.44 124.335 ;
     RECT  2.16 124.605 19.44 124.875 ;
     RECT  2.16 125.145 19.44 125.415 ;
     RECT  2.16 125.685 19.44 125.955 ;
     RECT  2.16 126.225 19.44 126.495 ;
     RECT  2.16 126.765 19.44 127.035 ;
     RECT  2.16 127.305 19.44 127.575 ;
     RECT  2.16 127.845 19.44 128.115 ;
     RECT  2.16 128.385 19.44 128.655 ;
     RECT  2.16 128.925 19.44 129.195 ;
     RECT  2.16 129.465 19.44 129.735 ;
     RECT  2.16 130.005 19.44 130.275 ;
     RECT  2.16 130.545 19.44 130.815 ;
     RECT  2.16 131.085 19.44 131.355 ;
     RECT  2.16 131.625 19.44 131.895 ;
     RECT  2.16 132.165 19.44 132.435 ;
     RECT  2.16 132.705 19.44 132.975 ;
     RECT  2.16 133.245 19.44 133.515 ;
     RECT  2.16 133.785 19.44 134.055 ;
     RECT  2.16 134.325 19.44 134.595 ;
     RECT  2.16 134.865 19.44 135.135 ;
     RECT  2.16 135.405 19.44 135.675 ;
     RECT  2.16 135.945 19.44 136.215 ;
     RECT  2.16 136.485 19.44 136.755 ;
     RECT  2.16 137.025 19.44 137.295 ;
     RECT  2.16 137.565 19.44 137.835 ;
     RECT  2.16 138.105 19.44 138.375 ;
     RECT  2.16 138.645 19.44 138.915 ;
     RECT  2.16 139.185 19.44 139.455 ;
     RECT  2.16 139.725 19.44 139.995 ;
     RECT  2.16 140.265 19.44 140.535 ;
     RECT  2.16 140.805 19.44 141.075 ;
     RECT  2.16 141.345 19.44 141.615 ;
     RECT  2.16 141.885 19.44 142.155 ;
     RECT  2.16 142.425 19.44 142.695 ;
     RECT  2.16 142.965 19.44 143.235 ;
     RECT  2.16 143.505 19.44 143.775 ;
     RECT  2.16 144.045 19.44 144.315 ;
     RECT  2.16 144.585 19.44 144.72 ;
    LAYER RVTP ;
     RECT  2.16 2.295 19.44 2.565 ;
     RECT  2.16 2.835 19.44 3.105 ;
     RECT  2.16 3.375 19.44 3.645 ;
     RECT  2.16 3.915 19.44 4.185 ;
     RECT  2.16 4.455 19.44 4.725 ;
     RECT  2.16 4.995 19.44 5.265 ;
     RECT  2.16 5.535 19.44 5.805 ;
     RECT  2.16 6.075 19.44 6.345 ;
     RECT  2.16 6.615 19.44 6.885 ;
     RECT  2.16 7.155 19.44 7.425 ;
     RECT  2.16 7.695 19.44 7.965 ;
     RECT  2.16 8.235 19.44 8.505 ;
     RECT  2.16 8.775 19.44 9.045 ;
     RECT  2.16 9.315 19.44 9.585 ;
     RECT  2.16 9.855 19.44 10.125 ;
     RECT  2.16 10.395 19.44 10.665 ;
     RECT  2.16 10.935 19.44 11.205 ;
     RECT  2.16 11.475 19.44 11.745 ;
     RECT  2.16 12.015 19.44 12.285 ;
     RECT  2.16 12.555 19.44 12.825 ;
     RECT  2.16 13.095 19.44 13.365 ;
     RECT  2.16 13.635 19.44 13.905 ;
     RECT  2.16 14.175 19.44 14.445 ;
     RECT  2.16 14.715 19.44 14.985 ;
     RECT  2.16 15.255 19.44 15.525 ;
     RECT  2.16 15.795 19.44 16.065 ;
     RECT  2.16 16.335 19.44 16.605 ;
     RECT  2.16 16.875 19.44 17.145 ;
     RECT  2.16 17.415 19.44 17.685 ;
     RECT  2.16 17.955 19.44 18.225 ;
     RECT  2.16 18.495 19.44 18.765 ;
     RECT  2.16 19.035 19.44 19.305 ;
     RECT  2.16 19.575 19.44 19.845 ;
     RECT  2.16 20.115 19.44 20.385 ;
     RECT  2.16 20.655 19.44 20.925 ;
     RECT  2.16 21.195 19.44 21.465 ;
     RECT  2.16 21.735 19.44 22.005 ;
     RECT  2.16 22.275 19.44 22.545 ;
     RECT  2.16 22.815 19.44 23.085 ;
     RECT  2.16 23.355 19.44 23.625 ;
     RECT  2.16 23.895 19.44 24.165 ;
     RECT  2.16 24.435 19.44 24.705 ;
     RECT  2.16 24.975 19.44 25.245 ;
     RECT  2.16 25.515 19.44 25.785 ;
     RECT  2.16 26.055 19.44 26.325 ;
     RECT  2.16 26.595 19.44 26.865 ;
     RECT  2.16 27.135 19.44 27.405 ;
     RECT  2.16 27.675 19.44 27.945 ;
     RECT  2.16 28.215 19.44 28.485 ;
     RECT  2.16 28.755 19.44 29.025 ;
     RECT  2.16 29.295 19.44 29.565 ;
     RECT  2.16 29.835 19.44 30.105 ;
     RECT  2.16 30.375 19.44 30.645 ;
     RECT  2.16 30.915 19.44 31.185 ;
     RECT  2.16 31.455 19.44 31.725 ;
     RECT  2.16 31.995 19.44 32.265 ;
     RECT  2.16 32.535 19.44 32.805 ;
     RECT  2.16 33.075 19.44 33.345 ;
     RECT  2.16 33.615 19.44 33.885 ;
     RECT  2.16 34.155 19.44 34.425 ;
     RECT  2.16 34.695 19.44 34.965 ;
     RECT  2.16 35.235 19.44 35.505 ;
     RECT  2.16 35.775 19.44 36.045 ;
     RECT  2.16 36.315 19.44 36.585 ;
     RECT  2.16 36.855 19.44 37.125 ;
     RECT  2.16 37.395 19.44 37.665 ;
     RECT  2.16 37.935 19.44 38.205 ;
     RECT  2.16 38.475 19.44 38.745 ;
     RECT  2.16 39.015 19.44 39.285 ;
     RECT  2.16 39.555 19.44 39.825 ;
     RECT  2.16 40.095 19.44 40.365 ;
     RECT  2.16 40.635 19.44 40.905 ;
     RECT  2.16 41.175 19.44 41.445 ;
     RECT  2.16 41.715 19.44 41.985 ;
     RECT  2.16 42.255 19.44 42.525 ;
     RECT  2.16 42.795 19.44 43.065 ;
     RECT  2.16 43.335 19.44 43.605 ;
     RECT  2.16 43.875 19.44 44.145 ;
     RECT  2.16 44.415 19.44 44.685 ;
     RECT  2.16 44.955 19.44 45.225 ;
     RECT  2.16 45.495 19.44 45.765 ;
     RECT  2.16 46.035 19.44 46.305 ;
     RECT  2.16 46.575 19.44 46.845 ;
     RECT  2.16 47.115 19.44 47.385 ;
     RECT  2.16 47.655 19.44 47.925 ;
     RECT  2.16 48.195 19.44 48.465 ;
     RECT  2.16 48.735 19.44 49.005 ;
     RECT  2.16 49.275 19.44 49.545 ;
     RECT  2.16 49.815 19.44 50.085 ;
     RECT  2.16 50.355 19.44 50.625 ;
     RECT  2.16 50.895 19.44 51.165 ;
     RECT  2.16 51.435 19.44 51.705 ;
     RECT  2.16 51.975 19.44 52.245 ;
     RECT  2.16 52.515 19.44 52.785 ;
     RECT  2.16 53.055 19.44 53.325 ;
     RECT  2.16 53.595 19.44 53.865 ;
     RECT  2.16 54.135 19.44 54.405 ;
     RECT  2.16 54.675 19.44 54.945 ;
     RECT  2.16 55.215 19.44 55.485 ;
     RECT  2.16 55.755 19.44 56.025 ;
     RECT  2.16 56.295 19.44 56.565 ;
     RECT  2.16 56.835 19.44 57.105 ;
     RECT  2.16 57.375 19.44 57.645 ;
     RECT  2.16 57.915 19.44 58.185 ;
     RECT  2.16 58.455 19.44 58.725 ;
     RECT  2.16 58.995 19.44 59.265 ;
     RECT  2.16 59.535 19.44 59.805 ;
     RECT  2.16 60.075 19.44 60.345 ;
     RECT  2.16 60.615 19.44 60.885 ;
     RECT  2.16 61.155 19.44 61.425 ;
     RECT  2.16 61.695 19.44 61.965 ;
     RECT  2.16 62.235 19.44 62.505 ;
     RECT  2.16 62.775 19.44 63.045 ;
     RECT  2.16 63.315 19.44 63.585 ;
     RECT  2.16 63.855 19.44 64.125 ;
     RECT  2.16 64.395 19.44 64.665 ;
     RECT  2.16 64.935 19.44 65.205 ;
     RECT  2.16 65.475 19.44 65.745 ;
     RECT  2.16 66.015 19.44 66.285 ;
     RECT  2.16 66.555 19.44 66.825 ;
     RECT  2.16 67.095 19.44 67.365 ;
     RECT  2.16 67.635 19.44 67.905 ;
     RECT  2.16 68.175 19.44 68.445 ;
     RECT  2.16 68.715 19.44 68.985 ;
     RECT  2.16 69.255 19.44 69.525 ;
     RECT  2.16 69.795 19.44 70.065 ;
     RECT  2.16 70.335 19.44 70.605 ;
     RECT  2.16 70.875 19.44 71.145 ;
     RECT  2.16 71.415 19.44 71.685 ;
     RECT  2.16 71.955 19.44 72.225 ;
     RECT  2.16 72.495 19.44 72.765 ;
     RECT  2.16 73.035 19.44 73.305 ;
     RECT  2.16 73.575 19.44 73.845 ;
     RECT  2.16 74.115 19.44 74.385 ;
     RECT  2.16 74.655 19.44 74.925 ;
     RECT  2.16 75.195 19.44 75.465 ;
     RECT  2.16 75.735 19.44 76.005 ;
     RECT  2.16 76.275 19.44 76.545 ;
     RECT  2.16 76.815 19.44 77.085 ;
     RECT  2.16 77.355 19.44 77.625 ;
     RECT  2.16 77.895 19.44 78.165 ;
     RECT  2.16 78.435 19.44 78.705 ;
     RECT  2.16 78.975 19.44 79.245 ;
     RECT  2.16 79.515 19.44 79.785 ;
     RECT  2.16 80.055 19.44 80.325 ;
     RECT  2.16 80.595 19.44 80.865 ;
     RECT  2.16 81.135 19.44 81.405 ;
     RECT  2.16 81.675 19.44 81.945 ;
     RECT  2.16 82.215 19.44 82.485 ;
     RECT  2.16 82.755 19.44 83.025 ;
     RECT  2.16 83.295 19.44 83.565 ;
     RECT  2.16 83.835 19.44 84.105 ;
     RECT  2.16 84.375 19.44 84.645 ;
     RECT  2.16 84.915 19.44 85.185 ;
     RECT  2.16 85.455 19.44 85.725 ;
     RECT  2.16 85.995 19.44 86.265 ;
     RECT  2.16 86.535 19.44 86.805 ;
     RECT  2.16 87.075 19.44 87.345 ;
     RECT  2.16 87.615 19.44 87.885 ;
     RECT  2.16 88.155 19.44 88.425 ;
     RECT  2.16 88.695 19.44 88.965 ;
     RECT  2.16 89.235 19.44 89.505 ;
     RECT  2.16 89.775 19.44 90.045 ;
     RECT  2.16 90.315 19.44 90.585 ;
     RECT  2.16 90.855 19.44 91.125 ;
     RECT  2.16 91.395 19.44 91.665 ;
     RECT  2.16 91.935 19.44 92.205 ;
     RECT  2.16 92.475 19.44 92.745 ;
     RECT  2.16 93.015 19.44 93.285 ;
     RECT  2.16 93.555 19.44 93.825 ;
     RECT  2.16 94.095 19.44 94.365 ;
     RECT  2.16 94.635 19.44 94.905 ;
     RECT  2.16 95.175 19.44 95.445 ;
     RECT  2.16 95.715 19.44 95.985 ;
     RECT  2.16 96.255 19.44 96.525 ;
     RECT  2.16 96.795 19.44 97.065 ;
     RECT  2.16 97.335 19.44 97.605 ;
     RECT  2.16 97.875 19.44 98.145 ;
     RECT  2.16 98.415 19.44 98.685 ;
     RECT  2.16 98.955 19.44 99.225 ;
     RECT  2.16 99.495 19.44 99.765 ;
     RECT  2.16 100.035 19.44 100.305 ;
     RECT  2.16 100.575 19.44 100.845 ;
     RECT  2.16 101.115 19.44 101.385 ;
     RECT  2.16 101.655 19.44 101.925 ;
     RECT  2.16 102.195 19.44 102.465 ;
     RECT  2.16 102.735 19.44 103.005 ;
     RECT  2.16 103.275 19.44 103.545 ;
     RECT  2.16 103.815 19.44 104.085 ;
     RECT  2.16 104.355 19.44 104.625 ;
     RECT  2.16 104.895 19.44 105.165 ;
     RECT  2.16 105.435 19.44 105.705 ;
     RECT  2.16 105.975 19.44 106.245 ;
     RECT  2.16 106.515 19.44 106.785 ;
     RECT  2.16 107.055 19.44 107.325 ;
     RECT  2.16 107.595 19.44 107.865 ;
     RECT  2.16 108.135 19.44 108.405 ;
     RECT  2.16 108.675 19.44 108.945 ;
     RECT  2.16 109.215 19.44 109.485 ;
     RECT  2.16 109.755 19.44 110.025 ;
     RECT  2.16 110.295 19.44 110.565 ;
     RECT  2.16 110.835 19.44 111.105 ;
     RECT  2.16 111.375 19.44 111.645 ;
     RECT  2.16 111.915 19.44 112.185 ;
     RECT  2.16 112.455 19.44 112.725 ;
     RECT  2.16 112.995 19.44 113.265 ;
     RECT  2.16 113.535 19.44 113.805 ;
     RECT  2.16 114.075 19.44 114.345 ;
     RECT  2.16 114.615 19.44 114.885 ;
     RECT  2.16 115.155 19.44 115.425 ;
     RECT  2.16 115.695 19.44 115.965 ;
     RECT  2.16 116.235 19.44 116.505 ;
     RECT  2.16 116.775 19.44 117.045 ;
     RECT  2.16 117.315 19.44 117.585 ;
     RECT  2.16 117.855 19.44 118.125 ;
     RECT  2.16 118.395 19.44 118.665 ;
     RECT  2.16 118.935 19.44 119.205 ;
     RECT  2.16 119.475 19.44 119.745 ;
     RECT  2.16 120.015 19.44 120.285 ;
     RECT  2.16 120.555 19.44 120.825 ;
     RECT  2.16 121.095 19.44 121.365 ;
     RECT  2.16 121.635 19.44 121.905 ;
     RECT  2.16 122.175 19.44 122.445 ;
     RECT  2.16 122.715 19.44 122.985 ;
     RECT  2.16 123.255 19.44 123.525 ;
     RECT  2.16 123.795 19.44 124.065 ;
     RECT  2.16 124.335 19.44 124.605 ;
     RECT  2.16 124.875 19.44 125.145 ;
     RECT  2.16 125.415 19.44 125.685 ;
     RECT  2.16 125.955 19.44 126.225 ;
     RECT  2.16 126.495 19.44 126.765 ;
     RECT  2.16 127.035 19.44 127.305 ;
     RECT  2.16 127.575 19.44 127.845 ;
     RECT  2.16 128.115 19.44 128.385 ;
     RECT  2.16 128.655 19.44 128.925 ;
     RECT  2.16 129.195 19.44 129.465 ;
     RECT  2.16 129.735 19.44 130.005 ;
     RECT  2.16 130.275 19.44 130.545 ;
     RECT  2.16 130.815 19.44 131.085 ;
     RECT  2.16 131.355 19.44 131.625 ;
     RECT  2.16 131.895 19.44 132.165 ;
     RECT  2.16 132.435 19.44 132.705 ;
     RECT  2.16 132.975 19.44 133.245 ;
     RECT  2.16 133.515 19.44 133.785 ;
     RECT  2.16 134.055 19.44 134.325 ;
     RECT  2.16 134.595 19.44 134.865 ;
     RECT  2.16 135.135 19.44 135.405 ;
     RECT  2.16 135.675 19.44 135.945 ;
     RECT  2.16 136.215 19.44 136.485 ;
     RECT  2.16 136.755 19.44 137.025 ;
     RECT  2.16 137.295 19.44 137.565 ;
     RECT  2.16 137.835 19.44 138.105 ;
     RECT  2.16 138.375 19.44 138.645 ;
     RECT  2.16 138.915 19.44 139.185 ;
     RECT  2.16 139.455 19.44 139.725 ;
     RECT  2.16 139.995 19.44 140.265 ;
     RECT  2.16 140.535 19.44 140.805 ;
     RECT  2.16 141.075 19.44 141.345 ;
     RECT  2.16 141.615 19.44 141.885 ;
     RECT  2.16 142.155 19.44 142.425 ;
     RECT  2.16 142.695 19.44 142.965 ;
     RECT  2.16 143.235 19.44 143.505 ;
     RECT  2.16 143.775 19.44 144.045 ;
     RECT  2.16 144.315 19.44 144.585 ;
    LAYER M1 ;
     RECT  2.16 2.151 19.44 144.729 ;
    LAYER M2 ;
     RECT  0.103 121.302 0.535 121.32 ;
     RECT  0.103 6.822 2.16 6.84 ;
     RECT  0.103 18.972 2.16 18.99 ;
     RECT  0.103 32.472 2.16 32.49 ;
     RECT  0.103 49.482 2.16 49.5 ;
     RECT  0.103 55.152 2.16 55.17 ;
     RECT  0.103 67.176 2.16 67.194 ;
     RECT  0.103 75.132 2.16 75.15 ;
     RECT  0.103 78.642 2.16 78.66 ;
     RECT  0.103 80.802 2.16 80.82 ;
     RECT  0.103 90.522 2.16 90.54 ;
     RECT  0.535 99.162 2.16 99.18 ;
     RECT  0.103 103.482 2.16 103.5 ;
     RECT  0.103 104.868 2.16 104.886 ;
     RECT  0.103 110.502 2.16 110.52 ;
     RECT  0.535 121.302 2.16 121.968 ;
     RECT  0.103 123.462 2.16 123.48 ;
     RECT  0.103 126.972 2.16 126.99 ;
     RECT  0.103 129.132 2.16 129.15 ;
     RECT  0.103 134.802 2.16 134.82 ;
     RECT  2.16 2.151 19.44 144.729 ;
     RECT  19.44 141.282 19.931 141.804 ;
     RECT  19.44 10.296 19.967 10.314 ;
     RECT  19.44 11.916 19.967 12.474 ;
     RECT  19.44 13.266 19.967 13.824 ;
     RECT  19.44 15.966 19.967 15.984 ;
     RECT  19.44 18.126 19.967 18.144 ;
     RECT  19.44 18.936 19.967 19.494 ;
     RECT  19.44 23.256 19.967 23.814 ;
     RECT  19.44 31.086 19.967 31.644 ;
     RECT  19.44 36.756 19.967 37.314 ;
     RECT  19.44 39.456 19.967 39.474 ;
     RECT  19.44 40.266 19.967 40.824 ;
     RECT  19.44 41.616 19.967 41.634 ;
     RECT  19.44 42.426 19.967 42.984 ;
     RECT  19.44 44.586 19.967 45.18 ;
     RECT  19.44 48.096 19.967 48.654 ;
     RECT  19.44 76.446 19.967 77.004 ;
     RECT  19.44 79.416 19.967 79.974 ;
     RECT  19.44 82.116 19.967 82.134 ;
     RECT  19.44 86.472 19.967 87.03 ;
     RECT  19.44 87.786 19.967 87.804 ;
     RECT  19.44 94.302 19.967 94.824 ;
     RECT  19.44 95.616 19.967 95.634 ;
     RECT  19.44 99.936 19.967 100.494 ;
     RECT  19.44 101.322 19.967 101.34 ;
     RECT  19.44 102.096 19.967 102.654 ;
     RECT  19.44 109.116 19.967 109.134 ;
     RECT  19.44 114.786 19.967 114.804 ;
     RECT  19.44 122.616 19.967 122.634 ;
     RECT  19.44 123.462 19.967 123.984 ;
     RECT  19.44 125.586 19.967 126.144 ;
     RECT  19.44 129.906 19.967 130.464 ;
     RECT  19.44 131.256 19.967 131.814 ;
     RECT  19.44 133.956 19.967 133.974 ;
     RECT  19.44 136.116 19.967 136.134 ;
     RECT  19.44 136.926 19.967 137.484 ;
     RECT  19.44 138.276 19.967 138.294 ;
     RECT  19.44 3.276 20.507 3.294 ;
     RECT  19.967 13.266 20.507 13.284 ;
     RECT  19.44 14.616 20.507 14.634 ;
     RECT  19.44 20.286 20.507 20.304 ;
     RECT  19.967 23.256 20.507 23.274 ;
     RECT  19.44 24.606 20.507 24.624 ;
     RECT  19.44 28.116 20.507 28.134 ;
     RECT  19.44 28.926 20.507 29.484 ;
     RECT  19.44 30.276 20.507 30.294 ;
     RECT  19.44 32.436 20.507 32.454 ;
     RECT  19.44 35.946 20.507 35.964 ;
     RECT  19.967 40.266 20.507 40.284 ;
     RECT  19.967 42.426 20.507 42.444 ;
     RECT  19.44 43.812 20.507 43.83 ;
     RECT  19.44 49.446 20.507 49.464 ;
     RECT  19.44 78.606 20.507 78.624 ;
     RECT  19.44 82.926 20.507 83.484 ;
     RECT  19.44 84.276 20.507 84.294 ;
     RECT  19.967 94.302 20.507 94.32 ;
     RECT  19.44 96.426 20.507 96.984 ;
     RECT  19.44 98.586 20.507 98.604 ;
     RECT  19.44 103.446 20.507 103.464 ;
     RECT  19.44 104.256 20.507 104.274 ;
     RECT  19.44 115.596 20.507 115.614 ;
     RECT  19.44 117.756 20.507 118.314 ;
     RECT  19.44 119.916 20.507 120.51 ;
     RECT  19.967 123.462 20.507 123.48 ;
     RECT  19.967 125.586 20.507 125.604 ;
     RECT  19.44 126.972 20.507 126.99 ;
     RECT  19.44 129.096 20.507 129.114 ;
     RECT  19.967 129.906 20.507 129.924 ;
     RECT  19.967 131.256 20.507 131.274 ;
     RECT  19.44 134.766 20.507 135.324 ;
     RECT  19.44 2.466 20.543 2.484 ;
     RECT  19.44 4.626 20.543 4.644 ;
     RECT  19.44 5.976 20.543 5.994 ;
     RECT  19.44 7.596 20.543 8.154 ;
     RECT  19.44 16.776 20.543 17.334 ;
     RECT  19.44 25.416 20.543 25.974 ;
     RECT  20.507 29.466 20.543 29.484 ;
     RECT  19.44 33.786 20.543 33.804 ;
     RECT  19.44 34.596 20.543 35.154 ;
     RECT  19.44 45.936 20.543 46.494 ;
     RECT  19.44 50.256 20.543 50.85 ;
     RECT  19.44 52.416 20.543 52.974 ;
     RECT  19.44 53.766 20.543 54.324 ;
     RECT  19.44 55.116 20.543 55.71 ;
     RECT  19.44 56.466 20.543 56.484 ;
     RECT  19.44 57.276 20.543 57.834 ;
     RECT  19.44 58.626 20.543 58.644 ;
     RECT  19.44 59.436 20.543 59.994 ;
     RECT  19.44 60.786 20.543 60.804 ;
     RECT  19.44 62.136 20.543 62.154 ;
     RECT  19.44 63.756 20.543 64.314 ;
     RECT  19.44 65.916 20.543 66.474 ;
     RECT  19.44 68.616 20.543 69.174 ;
     RECT  19.44 69.966 20.543 69.984 ;
     RECT  19.44 70.776 20.543 71.334 ;
     RECT  19.44 72.126 20.543 72.144 ;
     RECT  19.44 73.746 20.543 74.304 ;
     RECT  19.967 76.446 20.543 76.464 ;
     RECT  19.44 77.832 20.543 77.85 ;
     RECT  20.507 83.466 20.543 83.484 ;
     RECT  19.44 85.086 20.543 85.644 ;
     RECT  19.44 88.596 20.543 89.154 ;
     RECT  19.44 89.946 20.543 89.964 ;
     RECT  19.44 91.296 20.543 91.314 ;
     RECT  20.507 96.966 20.543 96.984 ;
     RECT  19.44 97.776 20.543 97.794 ;
     RECT  19.44 106.416 20.543 107.01 ;
     RECT  19.44 108.306 20.543 108.324 ;
     RECT  19.44 109.926 20.543 110.484 ;
     RECT  19.44 112.086 20.543 112.644 ;
     RECT  19.44 116.946 20.543 116.964 ;
     RECT  20.507 118.296 20.543 118.314 ;
     RECT  20.507 120.492 20.543 120.51 ;
     RECT  19.44 124.776 20.543 124.794 ;
     RECT  19.44 128.286 20.543 128.304 ;
     RECT  20.507 135.306 20.543 135.324 ;
     RECT  19.44 140.436 20.543 140.454 ;
     RECT  19.931 141.786 20.543 141.804 ;
     RECT  19.44 142.596 20.543 143.154 ;
     RECT  19.44 6.786 21.515 6.804 ;
     RECT  20.543 7.596 21.515 7.614 ;
     RECT  19.44 8.946 21.515 8.964 ;
     RECT  19.44 11.106 21.515 11.124 ;
     RECT  19.967 11.916 21.515 11.934 ;
     RECT  20.543 16.776 21.515 16.794 ;
     RECT  19.967 18.936 21.515 18.954 ;
     RECT  19.44 22.446 21.515 22.464 ;
     RECT  20.543 25.416 21.515 25.434 ;
     RECT  19.44 26.766 21.515 26.784 ;
     RECT  19.967 31.086 21.515 31.104 ;
     RECT  20.543 34.596 21.515 34.614 ;
     RECT  19.967 36.756 21.515 36.774 ;
     RECT  19.44 38.106 21.515 38.124 ;
     RECT  19.967 44.586 21.515 44.604 ;
     RECT  20.543 45.936 21.515 45.954 ;
     RECT  19.44 47.286 21.515 47.304 ;
     RECT  19.967 48.096 21.515 48.114 ;
     RECT  20.543 50.256 21.515 50.274 ;
     RECT  19.44 51.606 21.515 51.624 ;
     RECT  20.543 52.416 21.515 52.434 ;
     RECT  20.543 53.766 21.515 53.784 ;
     RECT  20.543 55.116 21.515 55.134 ;
     RECT  20.543 57.276 21.515 57.294 ;
     RECT  20.543 59.436 21.515 59.454 ;
     RECT  19.44 62.946 21.515 62.964 ;
     RECT  20.543 63.756 21.515 63.774 ;
     RECT  19.44 65.106 21.515 65.124 ;
     RECT  20.543 65.916 21.515 65.934 ;
     RECT  20.543 70.776 21.515 70.794 ;
     RECT  19.44 72.936 21.515 72.954 ;
     RECT  20.543 73.746 21.515 73.764 ;
     RECT  19.44 75.096 21.515 75.114 ;
     RECT  19.967 79.416 21.515 79.434 ;
     RECT  19.44 80.766 21.515 80.784 ;
     RECT  20.543 85.086 21.515 85.104 ;
     RECT  19.967 86.472 21.515 86.49 ;
     RECT  20.543 88.596 21.515 88.614 ;
     RECT  19.44 92.106 21.515 92.124 ;
     RECT  19.967 99.936 21.515 99.954 ;
     RECT  19.967 102.096 21.515 102.114 ;
     RECT  19.44 105.606 21.515 105.624 ;
     RECT  20.543 106.416 21.515 106.434 ;
     RECT  20.543 109.926 21.515 109.944 ;
     RECT  19.44 111.276 21.515 111.294 ;
     RECT  20.543 112.086 21.515 112.104 ;
     RECT  19.44 113.436 21.515 113.454 ;
     RECT  19.44 119.106 21.515 119.124 ;
     RECT  19.44 121.266 21.515 121.284 ;
     RECT  19.44 132.642 21.515 132.66 ;
     RECT  19.967 136.926 21.515 136.944 ;
     RECT  20.543 142.596 21.515 142.614 ;
    LAYER M3 ;
     RECT  2.415 2.143 2.505 2.413 ;
     RECT  5.115 2.143 5.205 2.413 ;
     RECT  7.815 2.143 7.905 2.413 ;
     RECT  10.515 2.143 10.605 2.413 ;
     RECT  13.215 2.143 13.305 2.413 ;
     RECT  15.915 2.143 16.005 2.413 ;
     RECT  18.615 2.143 18.705 2.413 ;
     RECT  20.52 2.461 20.538 2.525 ;
     RECT  2.415 2.413 2.697 2.641 ;
     RECT  2.415 2.641 3.258 2.717 ;
     RECT  2.415 2.717 2.697 3.211 ;
     RECT  20.484 3.211 20.502 3.299 ;
     RECT  2.304 3.211 2.697 3.335 ;
     RECT  5.115 2.413 5.397 3.343 ;
     RECT  4.5 3.343 5.397 3.389 ;
     RECT  2.415 3.335 2.697 3.931 ;
     RECT  12.06 3.931 12.078 4.109 ;
     RECT  2.415 3.931 3.114 4.145 ;
     RECT  5.115 3.389 5.397 4.225 ;
     RECT  4.68 4.225 5.397 4.301 ;
     RECT  3.996 4.648 4.014 4.685 ;
     RECT  20.52 4.621 20.538 4.685 ;
     RECT  5.115 4.301 5.397 4.765 ;
     RECT  5.115 4.765 5.994 5.117 ;
     RECT  5.115 5.117 5.397 5.131 ;
     RECT  18.615 2.413 18.897 5.161 ;
     RECT  2.415 4.145 2.697 5.305 ;
     RECT  2.304 5.305 2.697 5.357 ;
     RECT  18.615 5.161 18.954 5.357 ;
     RECT  2.415 5.357 2.697 6.037 ;
     RECT  2.415 6.037 2.826 6.077 ;
     RECT  20.52 5.971 20.538 6.077 ;
     RECT  4.536 5.131 5.397 6.221 ;
     RECT  5.115 6.221 5.397 6.808 ;
     RECT  0.108 6.763 0.126 6.845 ;
     RECT  5.115 6.808 5.778 6.845 ;
     RECT  2.415 6.077 2.697 7.483 ;
     RECT  2.304 7.483 2.697 7.529 ;
     RECT  21.492 6.763 21.51 7.619 ;
     RECT  4.032 7.483 4.05 7.655 ;
     RECT  7.056 7.627 7.074 7.664 ;
     RECT  2.415 7.529 2.697 8.167 ;
     RECT  2.415 8.167 2.826 8.237 ;
     RECT  20.52 8.131 20.538 8.237 ;
     RECT  4.32 8.311 4.338 8.381 ;
     RECT  2.415 8.237 2.697 8.875 ;
     RECT  5.115 6.845 5.397 8.923 ;
     RECT  5.115 8.923 5.634 8.969 ;
     RECT  21.492 8.875 21.51 8.969 ;
     RECT  2.304 8.875 2.697 9.005 ;
     RECT  5.115 8.969 5.397 9.739 ;
     RECT  11.952 9.595 11.97 9.779 ;
     RECT  4.248 9.595 4.266 9.815 ;
     RECT  5.115 9.739 5.778 10.327 ;
     RECT  19.944 10.291 19.962 10.349 ;
     RECT  3.996 10.315 4.014 10.355 ;
     RECT  5.115 10.327 5.958 10.829 ;
     RECT  2.415 9.005 2.697 11.035 ;
     RECT  2.304 11.035 2.697 11.165 ;
     RECT  2.415 11.165 2.697 11.275 ;
     RECT  2.415 11.275 3.258 11.315 ;
     RECT  21.492 11.035 21.51 11.939 ;
     RECT  5.115 10.829 5.397 11.947 ;
     RECT  4.176 11.755 4.194 11.975 ;
     RECT  5.115 11.947 5.598 11.984 ;
     RECT  2.415 11.315 2.697 12.475 ;
     RECT  19.944 12.451 19.962 12.509 ;
     RECT  2.304 12.475 2.697 12.515 ;
     RECT  6.84 11.947 6.858 12.623 ;
     RECT  5.115 11.984 5.397 13.147 ;
     RECT  20.484 13.147 20.502 13.289 ;
     RECT  5.115 13.147 5.49 13.405 ;
     RECT  5.115 13.405 5.994 13.469 ;
     RECT  2.415 12.515 2.697 13.837 ;
     RECT  2.415 13.837 2.826 13.901 ;
     RECT  19.944 13.801 19.962 13.901 ;
     RECT  4.32 13.981 4.338 14.045 ;
     RECT  2.415 13.901 2.697 14.587 ;
     RECT  20.484 14.587 20.502 14.639 ;
     RECT  2.304 14.587 2.697 14.675 ;
     RECT  5.115 13.469 5.397 14.677 ;
     RECT  4.5 14.677 5.397 14.717 ;
     RECT  2.415 14.675 2.697 15.307 ;
     RECT  10.515 2.413 10.797 15.307 ;
     RECT  10.515 15.307 11.43 15.449 ;
     RECT  5.115 14.717 5.397 15.451 ;
     RECT  2.415 15.307 3.402 15.485 ;
     RECT  4.608 15.451 5.397 15.491 ;
     RECT  6.84 15.961 6.858 15.979 ;
     RECT  5.115 15.491 5.397 15.997 ;
     RECT  6.84 15.979 7.074 16.025 ;
     RECT  5.115 15.997 5.562 16.061 ;
     RECT  19.944 15.961 19.962 16.061 ;
     RECT  6.84 16.025 6.858 16.133 ;
     RECT  2.415 15.485 2.697 16.699 ;
     RECT  4.32 16.747 4.338 16.771 ;
     RECT  4.14 16.771 4.338 16.799 ;
     RECT  21.492 16.699 21.51 16.799 ;
     RECT  4.14 16.799 4.158 17.453 ;
     RECT  20.52 17.311 20.538 17.453 ;
     RECT  2.304 16.699 2.697 17.483 ;
     RECT  5.115 16.061 5.397 18.139 ;
     RECT  19.944 18.121 19.962 18.173 ;
     RECT  4.464 18.139 5.397 18.185 ;
     RECT  6.84 18.187 6.858 18.293 ;
     RECT  21.492 18.859 21.51 18.959 ;
     RECT  7.815 2.413 8.097 18.967 ;
     RECT  0.108 18.859 0.126 18.995 ;
     RECT  4.212 18.811 4.23 19.195 ;
     RECT  5.115 18.185 5.397 19.195 ;
     RECT  6.408 19.201 6.426 19.381 ;
     RECT  7.416 18.967 8.097 19.381 ;
     RECT  6.408 19.381 8.097 19.421 ;
     RECT  6.408 19.421 6.714 19.499 ;
     RECT  2.415 17.483 2.697 19.579 ;
     RECT  19.944 19.471 19.962 19.613 ;
     RECT  4.212 19.195 5.397 19.805 ;
     RECT  5.115 19.805 5.397 19.915 ;
     RECT  6.408 19.499 6.426 19.949 ;
     RECT  4.248 19.805 4.266 19.955 ;
     RECT  5.115 19.915 5.634 20.309 ;
     RECT  20.484 20.251 20.502 20.309 ;
     RECT  2.304 19.579 2.697 20.345 ;
     RECT  2.415 20.345 2.697 20.971 ;
     RECT  11.952 20.971 11.97 21.119 ;
     RECT  6.696 21.091 6.714 21.149 ;
     RECT  2.415 20.971 2.862 21.155 ;
     RECT  4.284 21.163 4.302 21.2 ;
     RECT  5.115 20.309 5.397 21.259 ;
     RECT  10.515 15.449 10.797 21.271 ;
     RECT  6.372 21.157 6.39 21.293 ;
     RECT  4.608 21.259 5.397 21.299 ;
     RECT  3.78 21.271 3.798 21.389 ;
     RECT  10.008 21.271 10.797 21.389 ;
     RECT  7.815 19.421 8.097 21.505 ;
     RECT  13.215 2.413 13.497 21.631 ;
     RECT  7.38 21.505 8.097 21.667 ;
     RECT  7.38 21.667 8.154 21.695 ;
     RECT  12.528 21.631 13.497 21.725 ;
     RECT  6.408 21.883 6.426 21.929 ;
     RECT  7.815 21.695 8.154 22.157 ;
     RECT  2.415 21.155 2.697 22.411 ;
     RECT  21.492 22.411 21.51 22.469 ;
     RECT  4.32 22.621 4.338 22.685 ;
     RECT  20.484 23.131 20.502 23.279 ;
     RECT  2.304 22.411 2.697 23.315 ;
     RECT  5.115 21.299 5.397 23.317 ;
     RECT  4.5 23.317 5.397 23.357 ;
     RECT  5.115 23.357 5.397 23.827 ;
     RECT  4.14 23.827 4.158 23.885 ;
     RECT  5.115 23.827 5.778 23.885 ;
     RECT  19.944 23.791 19.962 23.885 ;
     RECT  20.484 24.523 20.502 24.629 ;
     RECT  7.815 22.157 8.097 24.637 ;
     RECT  0.108 24.523 0.126 24.653 ;
     RECT  7.815 24.637 8.154 24.701 ;
     RECT  6.84 24.601 6.858 24.773 ;
     RECT  2.415 23.315 2.697 25.243 ;
     RECT  4.32 25.099 4.338 25.439 ;
     RECT  21.492 25.243 21.51 25.439 ;
     RECT  20.52 25.951 20.538 25.997 ;
     RECT  2.304 25.243 2.697 26.015 ;
     RECT  5.115 23.885 5.397 26.131 ;
     RECT  10.515 21.389 10.797 26.671 ;
     RECT  5.115 26.131 5.634 26.761 ;
     RECT  5.115 26.761 5.706 26.779 ;
     RECT  6.696 26.671 6.714 26.789 ;
     RECT  9.972 26.671 10.797 26.789 ;
     RECT  21.492 26.683 21.51 26.789 ;
     RECT  5.115 26.779 5.778 26.827 ;
     RECT  5.115 26.827 5.922 26.897 ;
     RECT  5.115 26.897 5.778 27.341 ;
     RECT  6.552 27.307 6.57 27.365 ;
     RECT  3.996 27.337 4.014 27.437 ;
     RECT  11.664 27.301 11.682 27.437 ;
     RECT  2.415 26.015 2.697 28.075 ;
     RECT  2.304 28.075 2.697 28.175 ;
     RECT  20.484 28.075 20.502 28.949 ;
     RECT  2.412 28.175 2.697 28.985 ;
     RECT  4.32 27.979 4.338 29.029 ;
     RECT  5.115 27.341 5.397 29.029 ;
     RECT  4.32 29.029 5.397 29.069 ;
     RECT  4.464 29.069 5.397 29.549 ;
     RECT  20.52 29.461 20.538 29.549 ;
     RECT  5.115 29.549 5.397 29.605 ;
     RECT  5.115 29.605 5.778 29.645 ;
     RECT  2.415 28.985 2.697 30.235 ;
     RECT  5.115 29.645 5.397 30.283 ;
     RECT  20.484 30.235 20.502 30.299 ;
     RECT  5.004 30.283 5.397 30.335 ;
     RECT  7.056 30.283 7.074 30.335 ;
     RECT  21.492 30.955 21.51 31.109 ;
     RECT  4.32 31.261 4.338 31.325 ;
     RECT  5.115 30.335 5.397 31.579 ;
     RECT  5.115 31.579 5.634 31.649 ;
     RECT  19.944 31.621 19.962 31.661 ;
     RECT  2.304 30.235 2.697 31.685 ;
     RECT  20.484 32.347 20.502 32.459 ;
     RECT  0.108 32.347 0.126 32.495 ;
     RECT  15.915 2.413 16.197 32.971 ;
     RECT  6.624 32.575 6.642 33.053 ;
     RECT  3.996 33.007 4.014 33.101 ;
     RECT  15.915 32.971 16.542 33.101 ;
     RECT  2.415 31.685 2.697 33.787 ;
     RECT  20.52 33.781 20.538 33.821 ;
     RECT  4.32 33.961 4.338 34.013 ;
     RECT  21.492 34.507 21.51 34.619 ;
     RECT  2.304 33.787 2.697 34.655 ;
     RECT  5.115 31.649 5.397 34.735 ;
     RECT  5.115 34.735 5.598 34.781 ;
     RECT  3.996 35.167 4.014 35.213 ;
     RECT  20.52 35.131 20.538 35.213 ;
     RECT  6.84 34.747 6.858 35.309 ;
     RECT  2.415 34.655 2.697 35.941 ;
     RECT  20.484 35.899 20.502 35.969 ;
     RECT  2.415 35.941 2.79 35.981 ;
     RECT  7.056 36.085 7.074 36.125 ;
     RECT  2.415 35.981 2.697 36.619 ;
     RECT  4.32 36.475 4.338 36.751 ;
     RECT  4.248 36.751 4.338 36.779 ;
     RECT  21.492 36.619 21.51 36.779 ;
     RECT  2.34 36.619 2.697 36.815 ;
     RECT  4.248 36.779 4.266 36.851 ;
     RECT  5.115 34.781 5.397 37.051 ;
     RECT  5.115 37.051 5.634 37.319 ;
     RECT  2.415 36.815 2.697 37.327 ;
     RECT  2.415 37.327 2.826 37.373 ;
     RECT  19.944 37.291 19.962 37.373 ;
     RECT  2.415 37.373 2.697 38.059 ;
     RECT  5.115 37.319 5.397 38.101 ;
     RECT  21.492 38.059 21.51 38.129 ;
     RECT  5.115 38.101 5.562 38.141 ;
     RECT  7.815 24.701 8.097 38.155 ;
     RECT  2.304 38.059 2.697 38.165 ;
     RECT  7.092 38.155 8.097 38.201 ;
     RECT  9.144 38.173 9.162 38.399 ;
     RECT  3.996 38.281 4.014 38.515 ;
     RECT  5.115 38.141 5.397 38.515 ;
     RECT  3.996 38.515 5.397 38.765 ;
     RECT  6.516 38.677 6.534 38.765 ;
     RECT  3.996 38.765 4.014 38.813 ;
     RECT  11.952 38.713 11.97 38.813 ;
     RECT  2.415 38.165 2.697 39.451 ;
     RECT  19.944 39.445 19.962 39.485 ;
     RECT  2.304 39.451 2.697 39.515 ;
     RECT  2.412 39.515 2.697 39.631 ;
     RECT  5.115 38.765 5.397 39.883 ;
     RECT  2.412 39.631 3.258 39.917 ;
     RECT  20.484 40.171 20.502 40.289 ;
     RECT  2.412 39.917 2.697 40.325 ;
     RECT  4.5 39.883 5.397 40.445 ;
     RECT  6.3 40.795 6.318 40.865 ;
     RECT  2.415 40.325 2.697 40.891 ;
     RECT  2.415 40.891 2.79 40.937 ;
     RECT  2.415 40.937 2.697 41.611 ;
     RECT  5.115 40.445 5.397 41.611 ;
     RECT  7.815 38.201 8.097 41.611 ;
     RECT  19.944 40.801 19.962 41.645 ;
     RECT  5.004 41.611 5.397 41.675 ;
     RECT  7.704 41.611 8.097 41.675 ;
     RECT  20.484 42.331 20.502 42.449 ;
     RECT  2.304 41.611 2.697 42.485 ;
     RECT  2.415 42.485 2.697 42.601 ;
     RECT  2.415 42.601 3.258 42.653 ;
     RECT  2.415 42.653 2.826 43.037 ;
     RECT  19.944 42.961 19.962 43.037 ;
     RECT  5.115 41.675 5.397 43.141 ;
     RECT  4.536 43.141 5.397 43.181 ;
     RECT  2.415 43.037 2.697 43.681 ;
     RECT  2.304 43.681 2.697 43.757 ;
     RECT  5.115 43.181 5.397 43.807 ;
     RECT  4.356 43.675 4.374 43.835 ;
     RECT  20.484 43.723 20.502 43.835 ;
     RECT  5.115 43.807 5.778 43.853 ;
     RECT  21.492 44.443 21.51 44.609 ;
     RECT  3.996 44.443 4.014 44.645 ;
     RECT  7.056 44.587 7.074 44.645 ;
     RECT  2.415 43.757 2.697 45.157 ;
     RECT  19.944 45.157 19.962 45.197 ;
     RECT  2.415 45.157 2.826 45.301 ;
     RECT  12.096 45.157 12.114 45.329 ;
     RECT  2.415 45.301 3.258 45.341 ;
     RECT  2.415 45.341 2.697 45.883 ;
     RECT  21.492 45.883 21.51 45.959 ;
     RECT  2.304 45.883 2.697 45.995 ;
     RECT  5.115 43.853 5.397 46.111 ;
     RECT  4.536 46.111 5.397 46.157 ;
     RECT  6.84 46.459 6.858 46.535 ;
     RECT  2.415 45.995 2.697 46.543 ;
     RECT  2.415 46.543 2.826 46.589 ;
     RECT  20.52 46.471 20.538 46.589 ;
     RECT  2.415 46.589 2.79 47.219 ;
     RECT  7.815 41.675 8.097 47.317 ;
     RECT  3.996 47.179 4.014 47.345 ;
     RECT  7.815 47.317 8.154 47.357 ;
     RECT  2.415 47.219 2.697 47.995 ;
     RECT  2.304 47.995 2.697 48.091 ;
     RECT  21.492 47.272 21.51 48.119 ;
     RECT  2.304 48.091 2.862 48.155 ;
     RECT  2.415 48.155 2.862 48.271 ;
     RECT  2.415 48.271 3.258 48.317 ;
     RECT  2.415 48.317 2.79 48.749 ;
     RECT  19.944 48.631 19.962 48.749 ;
     RECT  5.115 46.157 5.397 48.775 ;
     RECT  4.5 48.775 5.397 48.845 ;
     RECT  20.484 49.432 20.502 49.469 ;
     RECT  5.115 48.845 5.397 49.477 ;
     RECT  0.108 49.435 0.126 49.505 ;
     RECT  5.115 49.477 5.778 49.517 ;
     RECT  2.415 48.749 2.697 50.152 ;
     RECT  5.115 49.517 5.397 50.155 ;
     RECT  2.304 50.152 2.697 50.189 ;
     RECT  7.815 47.357 8.097 50.251 ;
     RECT  21.492 50.155 21.51 50.279 ;
     RECT  5.004 50.155 5.397 50.315 ;
     RECT  7.272 50.251 8.097 50.315 ;
     RECT  2.415 50.189 2.697 50.821 ;
     RECT  2.415 50.821 2.826 50.861 ;
     RECT  20.52 50.821 20.538 50.861 ;
     RECT  11.88 50.827 11.898 50.999 ;
     RECT  4.32 50.965 4.338 51.005 ;
     RECT  2.415 50.861 2.697 51.547 ;
     RECT  5.115 50.315 5.397 51.595 ;
     RECT  2.304 51.547 2.697 51.665 ;
     RECT  2.415 51.665 2.697 52.267 ;
     RECT  10.515 26.789 10.797 52.321 ;
     RECT  6.588 52.321 6.606 52.439 ;
     RECT  9.9 52.321 10.797 52.439 ;
     RECT  21.492 51.547 21.51 52.439 ;
     RECT  2.415 52.267 2.862 52.475 ;
     RECT  5.115 51.595 5.634 52.987 ;
     RECT  20.52 52.951 20.538 53.021 ;
     RECT  5.115 52.987 5.994 53.024 ;
     RECT  2.415 52.475 2.697 53.671 ;
     RECT  4.32 53.563 4.338 53.671 ;
     RECT  5.115 53.024 5.397 53.671 ;
     RECT  2.415 53.671 2.826 53.707 ;
     RECT  21.492 53.707 21.51 53.789 ;
     RECT  2.304 53.707 2.826 53.825 ;
     RECT  7.815 50.315 8.097 53.941 ;
     RECT  6.768 53.941 8.097 53.995 ;
     RECT  6.732 53.995 8.097 54.059 ;
     RECT  6.768 54.059 8.097 54.125 ;
     RECT  2.415 53.825 2.826 54.139 ;
     RECT  2.415 54.139 3.474 54.329 ;
     RECT  2.415 54.329 2.826 54.413 ;
     RECT  20.52 54.301 20.538 54.413 ;
     RECT  4.32 53.671 5.397 54.608 ;
     RECT  6.84 54.125 8.097 54.608 ;
     RECT  4.068 54.667 4.086 54.707 ;
     RECT  21.492 55.099 21.51 55.139 ;
     RECT  0.108 55.099 0.126 55.175 ;
     RECT  6.84 54.608 6.858 55.325 ;
     RECT  4.14 56.443 4.158 56.489 ;
     RECT  6.84 56.443 6.858 56.489 ;
     RECT  2.415 54.413 2.697 56.497 ;
     RECT  20.52 55.687 20.538 56.573 ;
     RECT  5.115 54.608 5.397 56.632 ;
     RECT  2.412 56.497 2.697 56.635 ;
     RECT  2.412 56.635 3.258 56.641 ;
     RECT  10.515 52.439 10.797 56.641 ;
     RECT  4.428 56.632 5.397 56.669 ;
     RECT  2.412 56.641 3.402 56.759 ;
     RECT  10.404 56.641 10.797 56.759 ;
     RECT  2.412 56.759 2.697 57.259 ;
     RECT  21.492 57.259 21.51 57.299 ;
     RECT  2.304 57.259 2.697 57.335 ;
     RECT  5.115 56.669 5.397 57.451 ;
     RECT  5.115 57.451 5.634 57.595 ;
     RECT  5.115 57.595 6.318 57.629 ;
     RECT  2.415 57.335 2.697 57.919 ;
     RECT  2.415 57.919 2.826 57.965 ;
     RECT  7.74 54.608 8.097 58.123 ;
     RECT  6.3 57.629 6.318 58.157 ;
     RECT  7.74 58.123 8.154 58.157 ;
     RECT  7.815 58.157 8.154 58.685 ;
     RECT  20.52 57.811 20.538 58.685 ;
     RECT  2.415 57.965 2.697 59.371 ;
     RECT  21.492 59.371 21.51 59.459 ;
     RECT  2.304 59.371 2.697 59.495 ;
     RECT  4.32 59.275 4.338 59.611 ;
     RECT  4.104 59.611 4.338 59.639 ;
     RECT  4.104 59.639 4.122 60.221 ;
     RECT  2.415 59.495 2.697 60.808 ;
     RECT  20.52 59.971 20.538 60.845 ;
     RECT  6.84 60.907 6.858 60.953 ;
     RECT  14.724 61.387 14.85 61.517 ;
     RECT  2.304 60.808 2.697 61.565 ;
     RECT  21.492 61.387 21.51 61.565 ;
     RECT  11.952 61.387 11.97 61.619 ;
     RECT  3.996 61.483 4.014 61.655 ;
     RECT  7.056 61.579 7.074 61.655 ;
     RECT  4.284 62.155 4.302 62.203 ;
     RECT  5.115 57.629 5.397 62.203 ;
     RECT  4.284 62.203 5.397 62.231 ;
     RECT  20.52 62.131 20.538 62.237 ;
     RECT  2.415 61.565 2.697 62.851 ;
     RECT  2.415 62.851 2.79 62.923 ;
     RECT  2.304 62.923 2.79 62.969 ;
     RECT  4.536 62.231 5.397 63.085 ;
     RECT  4.5 63.085 5.397 63.149 ;
     RECT  2.304 62.969 2.697 63.689 ;
     RECT  9.612 63.661 9.63 63.779 ;
     RECT  12.168 63.661 12.186 63.779 ;
     RECT  21.492 62.923 21.51 63.779 ;
     RECT  7.815 58.685 8.097 63.787 ;
     RECT  4.284 63.643 4.302 63.815 ;
     RECT  6.84 63.787 6.858 63.923 ;
     RECT  7.815 63.787 8.154 64.397 ;
     RECT  20.52 64.291 20.538 64.397 ;
     RECT  2.415 63.689 2.697 65.083 ;
     RECT  4.284 65.245 4.302 65.309 ;
     RECT  21.492 65.083 21.51 65.939 ;
     RECT  2.304 65.083 2.697 65.975 ;
     RECT  3.456 66.085 3.474 66.125 ;
     RECT  5.115 63.149 5.397 66.487 ;
     RECT  20.52 66.451 20.538 66.509 ;
     RECT  4.068 66.475 4.086 66.515 ;
     RECT  5.115 66.487 5.778 66.557 ;
     RECT  13.215 21.725 13.497 67.171 ;
     RECT  18.615 5.357 18.897 67.171 ;
     RECT  0.108 67.171 0.126 67.229 ;
     RECT  18.615 67.171 18.99 67.229 ;
     RECT  12.528 67.171 13.497 67.289 ;
     RECT  3.996 67.171 4.014 67.325 ;
     RECT  7.056 67.291 7.074 67.331 ;
     RECT  10.515 56.759 10.797 67.711 ;
     RECT  2.415 65.975 2.697 67.771 ;
     RECT  9.792 67.711 10.797 67.801 ;
     RECT  2.415 67.771 3.366 67.829 ;
     RECT  4.284 67.711 4.302 67.829 ;
     RECT  9.792 67.801 11.43 67.829 ;
     RECT  10.515 67.829 11.43 67.949 ;
     RECT  2.415 67.829 2.697 68.635 ;
     RECT  2.304 68.635 2.697 68.675 ;
     RECT  5.115 66.557 5.397 68.791 ;
     RECT  4.536 68.791 5.397 68.861 ;
     RECT  5.112 68.861 5.397 69.341 ;
     RECT  7.815 64.397 8.097 69.997 ;
     RECT  7.815 69.997 8.154 70.061 ;
     RECT  20.52 68.611 20.538 70.061 ;
     RECT  5.115 69.341 5.397 70.699 ;
     RECT  2.415 68.675 2.697 70.747 ;
     RECT  21.492 70.747 21.51 70.799 ;
     RECT  2.304 70.747 2.697 70.835 ;
     RECT  4.536 70.699 5.397 71.339 ;
     RECT  2.415 70.835 2.697 71.455 ;
     RECT  2.415 71.455 2.826 71.501 ;
     RECT  5.115 71.339 5.397 72.157 ;
     RECT  5.115 72.157 5.778 72.221 ;
     RECT  20.52 71.311 20.538 72.221 ;
     RECT  5.115 72.221 5.67 72.841 ;
     RECT  7.815 70.061 8.097 72.841 ;
     RECT  0.108 72.811 0.126 72.941 ;
     RECT  5.04 72.841 5.67 72.959 ;
     RECT  6.84 72.811 6.858 72.959 ;
     RECT  7.815 72.841 8.298 72.959 ;
     RECT  3.996 72.184 4.014 72.995 ;
     RECT  7.815 72.959 8.154 72.995 ;
     RECT  2.415 71.501 2.697 73.579 ;
     RECT  21.492 72.907 21.51 73.769 ;
     RECT  2.304 73.579 2.697 73.921 ;
     RECT  2.304 73.921 3.258 73.997 ;
     RECT  20.52 74.281 20.538 74.333 ;
     RECT  2.304 73.997 2.697 74.345 ;
     RECT  5.115 72.959 5.397 74.461 ;
     RECT  5.115 74.461 5.706 74.717 ;
     RECT  21.492 75.019 21.51 75.119 ;
     RECT  0.108 75.019 0.126 75.155 ;
     RECT  12.384 75.739 12.402 75.929 ;
     RECT  7.815 72.995 8.097 75.937 ;
     RECT  4.284 75.739 4.302 75.965 ;
     RECT  7.815 75.937 8.154 76.013 ;
     RECT  6.84 74.683 6.858 76.073 ;
     RECT  20.52 76.441 20.538 76.493 ;
     RECT  4.32 76.411 4.338 76.939 ;
     RECT  5.115 74.717 5.397 76.939 ;
     RECT  4.32 76.939 5.397 76.973 ;
     RECT  4.572 76.973 5.397 77.045 ;
     RECT  2.415 74.345 2.697 77.125 ;
     RECT  2.415 77.125 2.826 77.165 ;
     RECT  19.944 76.981 19.962 77.165 ;
     RECT  5.115 77.045 5.397 77.803 ;
     RECT  13.215 67.289 13.497 77.827 ;
     RECT  4.248 77.827 4.266 77.885 ;
     RECT  20.52 77.827 20.538 77.885 ;
     RECT  12.528 77.827 13.497 77.999 ;
     RECT  20.484 78.571 20.502 78.629 ;
     RECT  0.108 78.571 0.126 78.665 ;
     RECT  5.115 77.803 5.994 78.665 ;
     RECT  21.492 79.291 21.51 79.439 ;
     RECT  2.415 77.165 2.697 79.987 ;
     RECT  2.415 79.987 2.826 80.045 ;
     RECT  19.944 79.951 19.962 80.045 ;
     RECT  4.32 79.243 4.338 80.095 ;
     RECT  5.115 78.665 5.397 80.095 ;
     RECT  4.32 80.095 5.397 80.141 ;
     RECT  5.115 80.141 5.397 80.779 ;
     RECT  21.492 80.683 21.51 80.789 ;
     RECT  0.108 80.683 0.126 80.825 ;
     RECT  5.115 80.779 5.778 80.825 ;
     RECT  3.996 81.403 4.014 81.635 ;
     RECT  7.056 81.595 7.074 81.635 ;
     RECT  2.415 80.045 2.697 82.123 ;
     RECT  19.944 82.111 19.962 82.157 ;
     RECT  4.32 82.291 4.338 82.349 ;
     RECT  20.484 82.843 20.502 82.949 ;
     RECT  2.304 82.123 2.697 82.985 ;
     RECT  5.115 80.825 5.397 83.101 ;
     RECT  5.115 83.101 5.634 83.179 ;
     RECT  5.115 83.179 6.318 83.213 ;
     RECT  20.52 83.461 20.538 83.597 ;
     RECT  6.3 83.213 6.318 83.645 ;
     RECT  2.415 82.985 2.697 84.235 ;
     RECT  5.115 83.213 5.397 84.283 ;
     RECT  20.484 84.235 20.502 84.299 ;
     RECT  5.004 84.283 5.397 84.335 ;
     RECT  7.056 84.307 7.074 84.365 ;
     RECT  4.32 85.051 4.338 85.109 ;
     RECT  21.492 84.955 21.51 85.109 ;
     RECT  20.52 85.621 20.538 85.709 ;
     RECT  5.115 84.335 5.397 85.801 ;
     RECT  5.115 85.801 5.634 86.011 ;
     RECT  2.304 84.235 2.697 86.459 ;
     RECT  10.515 67.949 10.797 86.467 ;
     RECT  4.284 86.443 4.302 86.495 ;
     RECT  21.492 86.395 21.51 86.495 ;
     RECT  5.115 86.011 5.778 86.621 ;
     RECT  10.515 86.467 11.466 86.639 ;
     RECT  6.588 86.923 6.606 86.999 ;
     RECT  5.115 86.621 5.598 87.149 ;
     RECT  4.32 87.781 4.338 87.821 ;
     RECT  2.415 86.459 2.697 87.835 ;
     RECT  19.944 87.007 19.962 87.869 ;
     RECT  5.115 87.149 5.397 88.591 ;
     RECT  21.492 88.507 21.51 88.619 ;
     RECT  2.304 87.835 2.697 88.655 ;
     RECT  5.115 88.591 5.634 88.795 ;
     RECT  4.32 88.795 5.634 88.889 ;
     RECT  4.32 88.889 4.338 88.891 ;
     RECT  4.284 88.891 4.338 88.931 ;
     RECT  6.516 88.861 6.534 89.035 ;
     RECT  6.516 89.035 6.822 89.075 ;
     RECT  6.516 89.075 6.534 89.195 ;
     RECT  5.115 88.889 5.634 89.311 ;
     RECT  5.115 89.311 5.994 89.429 ;
     RECT  12.06 89.311 12.078 89.429 ;
     RECT  4.32 88.931 4.338 89.453 ;
     RECT  5.115 89.429 5.814 89.465 ;
     RECT  6.984 89.941 7.002 89.977 ;
     RECT  20.52 89.131 20.538 89.981 ;
     RECT  6.984 89.977 7.074 90.077 ;
     RECT  6.984 90.077 7.002 90.113 ;
     RECT  2.415 88.655 2.697 90.517 ;
     RECT  10.515 86.639 10.797 90.589 ;
     RECT  2.415 90.517 2.862 90.605 ;
     RECT  10.515 90.589 10.998 90.653 ;
     RECT  0.108 90.517 0.126 90.701 ;
     RECT  6.804 90.811 6.822 90.895 ;
     RECT  6.552 90.895 6.822 90.941 ;
     RECT  4.284 91.051 4.302 91.091 ;
     RECT  5.115 89.465 5.397 91.147 ;
     RECT  6.804 90.941 6.822 91.243 ;
     RECT  2.415 90.605 2.697 91.387 ;
     RECT  20.52 91.291 20.538 91.421 ;
     RECT  2.304 91.387 2.697 91.463 ;
     RECT  6.804 91.243 6.858 91.589 ;
     RECT  4.536 91.147 5.397 92.045 ;
     RECT  2.415 91.463 2.697 92.101 ;
     RECT  21.492 92.059 21.51 92.129 ;
     RECT  2.415 92.101 2.79 92.141 ;
     RECT  6.84 91.589 6.858 92.245 ;
     RECT  6.84 92.245 7.074 92.273 ;
     RECT  11.952 92.779 11.97 92.939 ;
     RECT  3.996 92.107 4.014 92.975 ;
     RECT  10.515 90.653 10.797 93.361 ;
     RECT  10.332 93.361 10.797 93.451 ;
     RECT  10.332 93.451 11.43 93.479 ;
     RECT  7.056 92.273 7.074 93.485 ;
     RECT  2.415 92.141 2.697 93.487 ;
     RECT  4.284 93.451 4.302 93.515 ;
     RECT  10.515 93.479 11.43 93.533 ;
     RECT  5.115 92.045 5.397 94.171 ;
     RECT  2.415 93.487 2.826 94.219 ;
     RECT  2.304 94.219 2.826 94.289 ;
     RECT  20.484 94.219 20.502 94.325 ;
     RECT  11.88 94.297 11.898 94.469 ;
     RECT  5.115 94.171 5.778 94.639 ;
     RECT  6.804 94.507 6.822 94.667 ;
     RECT  5.115 94.639 5.886 94.865 ;
     RECT  19.944 94.801 19.962 95.645 ;
     RECT  7.815 76.013 8.097 95.647 ;
     RECT  3.996 95.611 4.014 95.675 ;
     RECT  7.815 95.647 8.154 95.693 ;
     RECT  4.32 96.379 4.338 96.449 ;
     RECT  20.484 96.331 20.502 96.449 ;
     RECT  2.304 94.289 2.697 96.485 ;
     RECT  4.032 97.051 4.05 97.133 ;
     RECT  2.415 96.485 2.697 97.771 ;
     RECT  5.115 94.865 5.397 97.771 ;
     RECT  20.52 96.961 20.538 97.805 ;
     RECT  2.304 97.771 2.697 97.835 ;
     RECT  4.68 97.771 5.397 97.835 ;
     RECT  2.415 97.835 2.697 98.581 ;
     RECT  20.484 98.491 20.502 98.609 ;
     RECT  2.415 98.581 2.79 98.621 ;
     RECT  3.996 98.587 4.014 98.645 ;
     RECT  7.056 98.725 7.074 98.765 ;
     RECT  4.068 99.157 4.086 99.197 ;
     RECT  0.54 99.157 0.558 99.245 ;
     RECT  11.952 99.121 11.97 99.245 ;
     RECT  2.415 98.621 2.697 99.883 ;
     RECT  21.492 99.883 21.51 99.959 ;
     RECT  2.304 99.883 2.697 99.995 ;
     RECT  5.115 97.835 5.397 100.111 ;
     RECT  5.115 100.111 5.634 100.267 ;
     RECT  5.115 100.267 6.318 100.301 ;
     RECT  3.996 100.603 4.014 100.643 ;
     RECT  6.3 100.301 6.318 100.685 ;
     RECT  19.944 100.471 19.962 101.357 ;
     RECT  7.056 101.419 7.074 101.459 ;
     RECT  12.096 101.317 12.114 101.489 ;
     RECT  2.415 99.995 2.697 102.043 ;
     RECT  2.304 102.043 2.697 102.091 ;
     RECT  21.492 102.043 21.51 102.119 ;
     RECT  2.304 102.091 2.862 102.271 ;
     RECT  2.304 102.271 3.258 102.317 ;
     RECT  19.944 102.631 19.962 102.797 ;
     RECT  2.304 102.317 2.697 102.803 ;
     RECT  0.108 103.435 0.126 103.505 ;
     RECT  6.84 103.579 6.858 103.619 ;
     RECT  7.815 95.693 8.097 104.107 ;
     RECT  2.415 102.803 2.697 104.152 ;
     RECT  2.304 104.152 2.697 104.189 ;
     RECT  20.484 103.432 20.502 104.279 ;
     RECT  3.996 104.155 4.014 104.315 ;
     RECT  7.815 104.107 8.154 104.315 ;
     RECT  2.415 104.189 2.697 104.779 ;
     RECT  2.415 104.779 3.258 104.819 ;
     RECT  2.415 104.819 3.186 104.891 ;
     RECT  0.108 104.863 0.126 104.909 ;
     RECT  11.736 104.863 11.754 104.909 ;
     RECT  2.415 104.891 2.697 105.595 ;
     RECT  5.115 100.301 5.397 105.781 ;
     RECT  5.115 105.781 5.634 105.979 ;
     RECT  2.304 105.595 2.697 106.349 ;
     RECT  21.492 105.592 21.51 106.439 ;
     RECT  4.248 106.315 4.266 106.475 ;
     RECT  5.115 105.979 5.778 106.475 ;
     RECT  7.815 104.315 8.097 106.699 ;
     RECT  7.815 106.699 8.154 107.015 ;
     RECT  20.52 106.981 20.538 107.021 ;
     RECT  11.556 106.987 11.574 107.159 ;
     RECT  10.515 93.533 10.797 107.563 ;
     RECT  2.415 106.349 2.697 107.611 ;
     RECT  14.724 107.563 14.85 107.693 ;
     RECT  0.108 107.611 0.126 107.741 ;
     RECT  21.492 107.563 21.51 107.741 ;
     RECT  5.115 106.475 5.397 107.755 ;
     RECT  4.32 107.752 4.338 107.789 ;
     RECT  10.515 107.563 11.358 107.789 ;
     RECT  2.415 107.611 3.186 107.825 ;
     RECT  5.115 107.755 5.562 108.059 ;
     RECT  6.84 108.187 6.858 108.239 ;
     RECT  2.415 107.825 2.697 108.427 ;
     RECT  20.52 108.301 20.538 108.461 ;
     RECT  2.304 108.427 2.697 108.473 ;
     RECT  2.415 108.473 2.697 109.141 ;
     RECT  2.415 109.141 2.826 109.181 ;
     RECT  19.944 109.111 19.962 109.181 ;
     RECT  5.115 108.059 5.397 109.255 ;
     RECT  5.115 109.255 5.778 109.421 ;
     RECT  21.492 109.867 21.51 109.949 ;
     RECT  7.815 107.015 8.097 109.957 ;
     RECT  7.815 109.957 8.154 109.997 ;
     RECT  2.415 109.181 2.79 110.497 ;
     RECT  2.415 110.497 3.186 110.573 ;
     RECT  0.108 110.497 0.126 110.621 ;
     RECT  20.52 110.461 20.538 110.621 ;
     RECT  2.415 110.573 2.697 111.259 ;
     RECT  5.115 109.421 5.397 111.445 ;
     RECT  4.536 111.445 5.397 111.485 ;
     RECT  21.492 111.259 21.51 112.109 ;
     RECT  2.304 111.259 2.697 112.145 ;
     RECT  5.115 111.485 5.397 112.225 ;
     RECT  5.115 112.225 5.778 112.301 ;
     RECT  3.996 112.693 4.014 112.733 ;
     RECT  20.52 112.621 20.538 112.733 ;
     RECT  7.815 109.997 8.097 112.747 ;
     RECT  7.815 112.747 8.154 112.793 ;
     RECT  2.415 112.145 2.697 113.419 ;
     RECT  2.304 113.419 2.697 113.495 ;
     RECT  4.32 113.605 4.338 113.645 ;
     RECT  3.924 113.995 3.942 114.035 ;
     RECT  11.772 113.971 11.79 114.077 ;
     RECT  14.724 114.043 14.85 114.173 ;
     RECT  21.492 113.419 21.51 114.173 ;
     RECT  2.415 113.495 2.697 114.808 ;
     RECT  19.944 114.781 19.962 114.845 ;
     RECT  5.115 112.301 5.397 114.925 ;
     RECT  4.68 114.925 5.397 114.989 ;
     RECT  2.304 114.808 2.697 115.565 ;
     RECT  20.484 115.531 20.502 115.619 ;
     RECT  3.996 115.483 4.014 115.655 ;
     RECT  7.056 115.579 7.074 115.655 ;
     RECT  2.415 115.565 2.697 116.251 ;
     RECT  10.515 107.789 10.797 116.251 ;
     RECT  2.415 116.251 2.898 116.395 ;
     RECT  10.515 116.251 11.43 116.429 ;
     RECT  2.415 116.395 3.258 116.435 ;
     RECT  2.415 116.435 2.898 116.465 ;
     RECT  2.415 116.465 2.697 116.968 ;
     RECT  20.52 116.941 20.538 117.005 ;
     RECT  5.115 114.989 5.397 117.121 ;
     RECT  4.536 117.121 5.397 117.197 ;
     RECT  5.115 117.197 5.397 117.739 ;
     RECT  20.484 117.691 20.502 117.779 ;
     RECT  2.304 116.968 2.697 117.815 ;
     RECT  5.115 117.739 5.778 117.815 ;
     RECT  7.056 118.315 7.074 118.355 ;
     RECT  20.52 118.291 20.538 118.397 ;
     RECT  3.996 118.363 4.014 118.4 ;
     RECT  2.415 117.815 2.697 119.083 ;
     RECT  21.492 119.083 21.51 119.129 ;
     RECT  20.484 119.803 20.502 119.939 ;
     RECT  2.304 119.083 2.697 119.975 ;
     RECT  4.32 119.083 4.338 120.091 ;
     RECT  5.115 117.815 5.397 120.091 ;
     RECT  4.32 120.091 5.397 120.119 ;
     RECT  4.536 120.119 5.397 120.317 ;
     RECT  10.515 116.429 10.797 120.487 ;
     RECT  2.415 119.975 2.697 120.517 ;
     RECT  2.415 120.517 2.826 120.557 ;
     RECT  20.52 120.487 20.538 120.557 ;
     RECT  4.68 120.317 5.397 120.653 ;
     RECT  10.515 120.487 11.358 120.659 ;
     RECT  21.492 121.243 21.51 121.289 ;
     RECT  5.115 120.653 5.397 121.291 ;
     RECT  0.108 121.243 0.126 121.325 ;
     RECT  5.115 121.291 5.994 121.331 ;
     RECT  3.672 121.771 3.69 121.829 ;
     RECT  0.54 121.945 0.558 121.997 ;
     RECT  11.628 121.945 11.646 122.141 ;
     RECT  14.724 121.963 14.85 122.141 ;
     RECT  2.415 120.557 2.697 122.635 ;
     RECT  5.115 121.331 5.397 122.635 ;
     RECT  19.944 122.611 19.962 122.669 ;
     RECT  2.304 122.635 2.697 122.675 ;
     RECT  4.5 122.635 5.397 122.675 ;
     RECT  0.108 123.355 0.126 123.485 ;
     RECT  20.484 123.355 20.502 123.485 ;
     RECT  5.115 122.675 5.397 123.565 ;
     RECT  5.115 123.565 5.778 123.629 ;
     RECT  7.815 112.793 8.097 123.979 ;
     RECT  7.596 123.979 8.097 124.025 ;
     RECT  19.944 123.961 19.962 124.109 ;
     RECT  4.284 124.069 4.302 124.219 ;
     RECT  5.115 123.629 5.397 124.219 ;
     RECT  2.415 122.675 2.697 124.795 ;
     RECT  4.284 124.219 5.397 124.795 ;
     RECT  20.52 124.771 20.538 124.829 ;
     RECT  2.412 124.795 2.697 124.835 ;
     RECT  4.14 124.795 5.397 125.035 ;
     RECT  3.816 125.035 5.397 125.075 ;
     RECT  9.648 124.951 9.666 125.249 ;
     RECT  6.912 125.311 6.93 125.357 ;
     RECT  6.624 125.371 6.858 125.483 ;
     RECT  2.415 124.835 2.697 125.581 ;
     RECT  20.484 125.515 20.502 125.609 ;
     RECT  2.415 125.581 2.862 125.789 ;
     RECT  4.32 125.075 5.397 125.981 ;
     RECT  6.84 125.483 6.858 126.185 ;
     RECT  3.996 126.157 4.014 126.221 ;
     RECT  19.944 126.121 19.962 126.221 ;
     RECT  5.115 125.981 5.397 126.379 ;
     RECT  5.115 126.379 6.102 126.689 ;
     RECT  0.108 126.907 0.126 126.995 ;
     RECT  20.484 126.907 20.502 126.995 ;
     RECT  7.056 126.571 7.074 127.099 ;
     RECT  7.815 124.025 8.097 127.099 ;
     RECT  7.056 127.099 8.097 127.139 ;
     RECT  12.096 126.967 12.114 127.139 ;
     RECT  6.264 126.931 6.282 127.229 ;
     RECT  9.108 127.075 9.126 127.229 ;
     RECT  7.056 127.139 7.074 127.421 ;
     RECT  2.415 125.789 2.697 127.627 ;
     RECT  10.515 120.659 10.797 127.627 ;
     RECT  10.515 127.627 11.25 127.769 ;
     RECT  2.304 127.627 2.697 127.805 ;
     RECT  4.32 127.921 4.338 127.997 ;
     RECT  5.115 126.689 5.397 128.251 ;
     RECT  4.536 128.251 5.397 128.309 ;
     RECT  2.415 127.805 2.697 128.344 ;
     RECT  2.415 128.344 2.79 128.381 ;
     RECT  20.52 128.281 20.538 128.381 ;
     RECT  0.108 129.067 0.126 129.155 ;
     RECT  6.84 129.235 6.858 129.293 ;
     RECT  20.484 129.067 20.502 129.929 ;
     RECT  7.815 127.139 8.097 129.931 ;
     RECT  7.815 129.931 8.154 129.971 ;
     RECT  2.415 128.381 2.697 130.351 ;
     RECT  5.115 128.309 5.397 130.351 ;
     RECT  4.464 130.351 5.397 130.411 ;
     RECT  2.415 130.351 2.898 130.469 ;
     RECT  4.32 130.411 5.397 130.469 ;
     RECT  19.944 130.441 19.962 130.493 ;
     RECT  2.415 130.469 2.697 131.179 ;
     RECT  20.484 131.179 20.502 131.279 ;
     RECT  2.304 131.179 2.697 131.315 ;
     RECT  5.115 130.469 5.397 131.431 ;
     RECT  5.115 131.431 5.634 131.501 ;
     RECT  19.944 131.791 19.962 131.933 ;
     RECT  4.14 131.899 4.158 131.963 ;
     RECT  21.492 132.619 21.51 132.665 ;
     RECT  6.948 131.659 6.966 132.745 ;
     RECT  6.948 132.745 7.074 132.773 ;
     RECT  7.056 132.773 7.074 132.797 ;
     RECT  11.556 132.637 11.574 132.809 ;
     RECT  2.415 131.315 2.697 133.291 ;
     RECT  11.88 133.291 11.898 133.439 ;
     RECT  2.415 133.291 3.114 133.475 ;
     RECT  4.32 133.387 4.338 133.987 ;
     RECT  5.115 131.501 5.397 133.987 ;
     RECT  4.32 133.987 5.397 134.015 ;
     RECT  2.415 133.475 2.754 134.045 ;
     RECT  19.944 133.951 19.962 134.045 ;
     RECT  4.5 134.015 5.397 134.525 ;
     RECT  20.484 134.731 20.502 134.789 ;
     RECT  0.108 134.731 0.126 134.825 ;
     RECT  5.115 134.525 5.397 134.905 ;
     RECT  5.115 134.905 5.778 134.957 ;
     RECT  7.815 129.971 8.097 135.307 ;
     RECT  7.632 135.307 8.097 135.365 ;
     RECT  5.115 134.957 5.706 135.485 ;
     RECT  20.52 135.301 20.538 135.485 ;
     RECT  6.84 135.301 6.858 135.509 ;
     RECT  4.32 136.075 4.338 136.111 ;
     RECT  4.248 136.111 4.338 136.139 ;
     RECT  19.944 136.111 19.962 136.205 ;
     RECT  4.248 136.139 4.266 136.211 ;
     RECT  2.415 134.045 2.697 136.891 ;
     RECT  5.115 135.485 5.397 136.891 ;
     RECT  4.536 136.891 5.397 136.949 ;
     RECT  21.492 136.891 21.51 136.949 ;
     RECT  2.304 136.891 2.697 136.985 ;
     RECT  2.415 136.985 2.697 137.563 ;
     RECT  2.415 137.563 2.754 137.633 ;
     RECT  6.3 137.605 6.318 137.645 ;
     RECT  2.415 137.633 2.697 138.271 ;
     RECT  5.115 136.949 5.397 138.283 ;
     RECT  19.944 137.461 19.962 138.317 ;
     RECT  5.004 138.283 5.397 138.335 ;
     RECT  7.815 135.365 8.097 138.415 ;
     RECT  7.815 138.415 8.154 138.461 ;
     RECT  10.515 127.769 10.797 138.991 ;
     RECT  18.615 67.229 18.897 138.991 ;
     RECT  18.615 138.991 18.99 139.037 ;
     RECT  10.515 138.991 11.358 139.109 ;
     RECT  2.304 138.271 2.697 139.261 ;
     RECT  2.304 139.261 3.258 139.325 ;
     RECT  5.115 138.335 5.397 139.531 ;
     RECT  10.515 139.109 10.797 139.531 ;
     RECT  2.304 139.325 3.114 139.649 ;
     RECT  5.115 139.531 5.454 139.649 ;
     RECT  6.228 139.531 6.246 139.649 ;
     RECT  9.972 139.531 10.797 139.649 ;
     RECT  11.736 139.621 11.754 139.757 ;
     RECT  2.304 139.649 2.697 140.477 ;
     RECT  20.52 140.431 20.538 140.477 ;
     RECT  4.14 140.443 4.158 140.495 ;
     RECT  6.84 140.443 7.074 140.495 ;
     RECT  7.056 140.495 7.074 141.241 ;
     RECT  3.996 141.115 4.014 141.305 ;
     RECT  6.984 141.241 7.074 141.305 ;
     RECT  19.908 141.115 19.926 141.305 ;
     RECT  2.415 140.477 2.697 141.355 ;
     RECT  6.984 141.305 7.002 141.413 ;
     RECT  12.096 141.277 12.114 141.449 ;
     RECT  2.415 141.355 3.258 141.809 ;
     RECT  20.52 141.781 20.538 141.869 ;
     RECT  5.115 139.649 5.397 142.507 ;
     RECT  2.415 141.809 2.697 142.555 ;
     RECT  4.536 142.507 5.397 142.619 ;
     RECT  21.492 142.555 21.51 142.619 ;
     RECT  2.304 142.555 2.697 142.655 ;
     RECT  2.415 142.655 2.697 143.269 ;
     RECT  2.415 143.269 2.826 143.309 ;
     RECT  20.52 143.131 20.538 143.309 ;
     RECT  2.415 143.309 2.697 144.467 ;
     RECT  5.115 142.619 5.397 144.467 ;
     RECT  7.815 138.461 8.097 144.467 ;
     RECT  10.515 139.649 10.797 144.467 ;
     RECT  13.215 77.999 13.497 144.467 ;
     RECT  15.915 33.101 16.197 144.467 ;
     RECT  18.615 139.037 18.897 144.467 ;
     RECT  2.415 144.467 2.505 144.737 ;
     RECT  5.115 144.467 5.205 144.737 ;
     RECT  7.815 144.467 7.905 144.737 ;
     RECT  10.515 144.467 10.605 144.737 ;
     RECT  13.215 144.467 13.305 144.737 ;
     RECT  15.915 144.467 16.005 144.737 ;
     RECT  18.615 144.467 18.705 144.737 ;
    LAYER M4 ;
     RECT  0.084 2.496 0.137 2.52 ;
     RECT  0.06 2.52 0.137 3.216 ;
     RECT  0.084 3.216 0.137 3.24 ;
     RECT  0.06 3.24 0.137 3.936 ;
     RECT  0.084 3.936 0.137 3.96 ;
     RECT  0.06 3.96 0.137 4.656 ;
     RECT  0.084 4.656 0.137 4.68 ;
     RECT  0.06 4.68 0.137 5.328 ;
     RECT  0.084 5.328 0.137 5.352 ;
     RECT  0.06 5.352 0.137 6.048 ;
     RECT  0.084 6.048 0.137 6.072 ;
     RECT  0.06 6.072 0.137 6.768 ;
     RECT  0.084 6.768 0.137 6.792 ;
     RECT  0.06 6.792 0.137 7.488 ;
     RECT  0.084 7.488 0.137 7.512 ;
     RECT  0.06 7.512 0.137 8.208 ;
     RECT  0.084 8.208 0.137 8.232 ;
     RECT  0.06 8.232 0.137 8.88 ;
     RECT  0.084 8.88 0.137 8.904 ;
     RECT  0.06 8.904 0.137 9.6 ;
     RECT  0.084 9.6 0.137 9.624 ;
     RECT  0.06 9.624 0.137 10.32 ;
     RECT  0.084 10.32 0.137 10.344 ;
     RECT  0.06 10.344 0.137 11.04 ;
     RECT  0.084 11.04 0.137 11.064 ;
     RECT  0.06 11.064 0.137 11.76 ;
     RECT  0.084 11.76 0.137 11.784 ;
     RECT  0.06 11.784 0.137 12.48 ;
     RECT  0.084 12.48 0.137 12.504 ;
     RECT  0.06 12.504 0.137 13.152 ;
     RECT  0.084 13.152 0.137 13.176 ;
     RECT  0.06 13.176 0.137 13.872 ;
     RECT  0.084 13.872 0.137 13.896 ;
     RECT  0.06 13.896 0.137 14.592 ;
     RECT  0.084 14.592 0.137 14.616 ;
     RECT  0.06 14.616 0.137 15.312 ;
     RECT  0.084 15.312 0.137 15.336 ;
     RECT  0.06 15.336 0.137 16.032 ;
     RECT  0.084 16.032 0.137 16.056 ;
     RECT  0.06 16.056 0.137 16.704 ;
     RECT  0.084 16.704 0.137 16.728 ;
     RECT  0.06 16.728 0.137 17.424 ;
     RECT  0.084 17.424 0.137 17.448 ;
     RECT  0.06 17.448 0.137 18.144 ;
     RECT  0.084 18.144 0.137 18.168 ;
     RECT  0.06 18.168 0.137 18.864 ;
     RECT  0.084 18.864 0.137 18.888 ;
     RECT  0.06 18.888 0.137 19.584 ;
     RECT  0.084 19.584 0.137 19.608 ;
     RECT  0.06 19.608 0.137 20.256 ;
     RECT  0.084 20.256 0.137 20.28 ;
     RECT  0.06 20.28 0.137 20.976 ;
     RECT  0.084 20.976 0.137 21 ;
     RECT  0.06 21 0.137 21.696 ;
     RECT  0.084 21.696 0.137 21.72 ;
     RECT  0.06 21.72 0.137 22.416 ;
     RECT  0.084 22.416 0.137 22.44 ;
     RECT  0.06 22.44 0.137 23.136 ;
     RECT  0.084 23.136 0.137 23.16 ;
     RECT  0.06 23.16 0.137 23.856 ;
     RECT  0.084 23.856 0.137 23.88 ;
     RECT  0.06 23.88 0.137 24.528 ;
     RECT  0.084 24.528 0.137 24.552 ;
     RECT  0.06 24.552 0.137 25.248 ;
     RECT  0.084 25.248 0.137 25.272 ;
     RECT  0.06 25.272 0.137 25.968 ;
     RECT  0.084 25.968 0.137 25.992 ;
     RECT  0.06 25.992 0.137 26.688 ;
     RECT  0.084 26.688 0.137 26.712 ;
     RECT  0.06 26.712 0.137 27.408 ;
     RECT  0.084 27.408 0.137 27.432 ;
     RECT  0.06 27.432 0.137 28.08 ;
     RECT  0.084 28.08 0.137 28.104 ;
     RECT  0.06 28.104 0.137 28.8 ;
     RECT  0.084 28.8 0.137 28.824 ;
     RECT  0.06 28.824 0.137 29.52 ;
     RECT  0.084 29.52 0.137 29.544 ;
     RECT  0.06 29.544 0.137 30.24 ;
     RECT  0.084 30.24 0.137 30.264 ;
     RECT  0.06 30.264 0.137 30.96 ;
     RECT  0.084 30.96 0.137 30.984 ;
     RECT  0.06 30.984 0.137 31.632 ;
     RECT  0.084 31.632 0.137 31.656 ;
     RECT  0.06 31.656 0.137 32.352 ;
     RECT  0.084 32.352 0.137 32.376 ;
     RECT  0.06 32.376 0.137 33.072 ;
     RECT  0.084 33.072 0.137 33.096 ;
     RECT  0.06 33.096 0.137 33.792 ;
     RECT  0.084 33.792 0.137 33.816 ;
     RECT  0.06 33.816 0.137 34.512 ;
     RECT  0.084 34.512 0.137 34.536 ;
     RECT  0.06 34.536 0.137 35.184 ;
     RECT  0.084 35.184 0.137 35.208 ;
     RECT  0.06 35.208 0.137 35.904 ;
     RECT  0.084 35.904 0.137 35.928 ;
     RECT  0.06 35.928 0.137 36.624 ;
     RECT  0.084 36.624 0.137 36.648 ;
     RECT  0.06 36.648 0.137 37.344 ;
     RECT  0.084 37.344 0.137 37.368 ;
     RECT  0.06 37.368 0.137 38.064 ;
     RECT  0.084 38.064 0.137 38.088 ;
     RECT  0.06 38.088 0.137 38.784 ;
     RECT  0.084 38.784 0.137 38.808 ;
     RECT  0.06 38.808 0.137 39.456 ;
     RECT  0.084 39.456 0.137 39.48 ;
     RECT  0.06 39.48 0.137 40.176 ;
     RECT  0.084 40.176 0.137 40.2 ;
     RECT  0.06 40.2 0.137 40.896 ;
     RECT  0.084 40.896 0.137 40.92 ;
     RECT  0.06 40.92 0.137 41.616 ;
     RECT  0.084 41.616 0.137 41.64 ;
     RECT  0.06 41.64 0.137 42.336 ;
     RECT  0.084 42.336 0.137 42.36 ;
     RECT  0.06 42.36 0.137 43.008 ;
     RECT  0.084 43.008 0.137 43.032 ;
     RECT  0.06 43.032 0.137 43.728 ;
     RECT  0.084 43.728 0.137 43.752 ;
     RECT  0.06 43.752 0.137 44.448 ;
     RECT  0.084 44.448 0.137 44.472 ;
     RECT  0.06 44.472 0.137 45.168 ;
     RECT  0.084 45.168 0.137 45.192 ;
     RECT  0.06 45.192 0.137 45.888 ;
     RECT  0.084 45.888 0.137 45.912 ;
     RECT  0.06 45.912 0.137 46.56 ;
     RECT  0.084 46.56 0.137 46.584 ;
     RECT  0.06 46.584 0.137 47.28 ;
     RECT  0.084 47.28 0.137 47.304 ;
     RECT  0.06 47.304 0.137 48 ;
     RECT  0.084 48 0.137 48.024 ;
     RECT  0.06 48.024 0.137 48.72 ;
     RECT  0.084 48.72 0.137 48.744 ;
     RECT  0.06 48.744 0.137 49.44 ;
     RECT  0.084 49.44 0.137 49.464 ;
     RECT  0.06 49.464 0.137 50.16 ;
     RECT  0.084 50.16 0.137 50.184 ;
     RECT  0.06 50.184 0.137 50.832 ;
     RECT  0.084 50.832 0.137 50.856 ;
     RECT  0.06 50.856 0.137 51.552 ;
     RECT  0.084 51.552 0.137 51.576 ;
     RECT  0.06 51.576 0.137 52.272 ;
     RECT  0.084 52.272 0.137 52.296 ;
     RECT  0.06 52.296 0.137 52.992 ;
     RECT  0.084 52.992 0.137 53.016 ;
     RECT  0.06 53.016 0.137 53.712 ;
     RECT  0.084 53.712 0.137 53.736 ;
     RECT  0.06 53.736 0.137 54.384 ;
     RECT  0.084 54.384 0.137 54.408 ;
     RECT  0.06 54.408 0.137 55.104 ;
     RECT  0.084 55.104 0.137 55.128 ;
     RECT  0.06 55.128 0.137 55.824 ;
     RECT  0.084 55.824 0.137 55.848 ;
     RECT  0.06 55.848 0.137 56.544 ;
     RECT  0.084 56.544 0.137 56.568 ;
     RECT  0.06 56.568 0.137 57.264 ;
     RECT  0.084 57.264 0.137 57.288 ;
     RECT  0.06 57.288 0.137 57.936 ;
     RECT  0.084 57.936 0.137 57.96 ;
     RECT  0.06 57.96 0.137 58.656 ;
     RECT  0.084 58.656 0.137 58.68 ;
     RECT  0.06 58.68 0.137 59.376 ;
     RECT  0.084 59.376 0.137 59.4 ;
     RECT  0.06 59.4 0.137 60.096 ;
     RECT  0.084 60.096 0.137 60.12 ;
     RECT  0.06 60.12 0.137 60.816 ;
     RECT  0.084 60.816 0.137 60.84 ;
     RECT  0.06 60.84 0.137 61.536 ;
     RECT  0.084 61.536 0.137 61.56 ;
     RECT  0.06 61.56 0.137 62.208 ;
     RECT  0.084 62.208 0.137 62.232 ;
     RECT  0.06 62.232 0.137 62.928 ;
     RECT  0.084 62.928 0.137 62.952 ;
     RECT  0.06 62.952 0.137 63.648 ;
     RECT  0.084 63.648 0.137 63.672 ;
     RECT  0.06 63.672 0.137 64.368 ;
     RECT  0.084 64.368 0.137 64.392 ;
     RECT  0.06 64.392 0.137 65.088 ;
     RECT  0.084 65.088 0.137 65.112 ;
     RECT  0.06 65.112 0.137 65.76 ;
     RECT  0.084 65.76 0.137 65.784 ;
     RECT  0.06 65.784 0.137 66.48 ;
     RECT  0.084 66.48 0.137 66.504 ;
     RECT  0.06 66.504 0.137 67.2 ;
     RECT  0.084 67.2 0.137 67.224 ;
     RECT  0.06 67.224 0.137 67.92 ;
     RECT  0.084 67.92 0.137 67.944 ;
     RECT  0.06 67.944 0.137 68.64 ;
     RECT  0.084 68.64 0.137 68.664 ;
     RECT  0.06 68.664 0.137 69.312 ;
     RECT  0.084 69.312 0.137 69.336 ;
     RECT  0.06 69.336 0.137 70.032 ;
     RECT  0.084 70.032 0.137 70.056 ;
     RECT  0.06 70.056 0.137 70.752 ;
     RECT  0.084 70.752 0.137 70.776 ;
     RECT  0.06 70.776 0.137 71.472 ;
     RECT  0.084 71.472 0.137 71.496 ;
     RECT  0.06 71.496 0.137 72.192 ;
     RECT  0.084 72.192 0.137 72.216 ;
     RECT  0.06 72.216 0.137 72.912 ;
     RECT  0.084 72.912 0.137 72.936 ;
     RECT  0.06 72.936 0.137 73.584 ;
     RECT  0.084 73.584 0.137 73.608 ;
     RECT  0.06 73.608 0.137 74.304 ;
     RECT  0.084 74.304 0.137 74.328 ;
     RECT  0.06 74.328 0.137 75.024 ;
     RECT  0.084 75.024 0.137 75.048 ;
     RECT  0.06 75.048 0.137 75.744 ;
     RECT  0.084 75.744 0.137 75.768 ;
     RECT  0.06 75.768 0.137 76.464 ;
     RECT  0.084 76.464 0.137 76.488 ;
     RECT  0.06 76.488 0.137 77.136 ;
     RECT  0.084 77.136 0.137 77.16 ;
     RECT  0.06 77.16 0.137 77.856 ;
     RECT  0.084 77.856 0.137 77.88 ;
     RECT  0.06 77.88 0.137 78.576 ;
     RECT  0.084 78.576 0.137 78.6 ;
     RECT  0.06 78.6 0.137 79.296 ;
     RECT  0.084 79.296 0.137 79.32 ;
     RECT  0.06 79.32 0.137 80.016 ;
     RECT  0.084 80.016 0.137 80.04 ;
     RECT  0.06 80.04 0.137 80.688 ;
     RECT  0.084 80.688 0.137 80.712 ;
     RECT  0.06 80.712 0.137 81.408 ;
     RECT  0.084 81.408 0.137 81.432 ;
     RECT  0.06 81.432 0.137 82.128 ;
     RECT  0.084 82.128 0.137 82.152 ;
     RECT  0.06 82.152 0.137 82.848 ;
     RECT  0.084 82.848 0.137 82.872 ;
     RECT  0.06 82.872 0.137 83.568 ;
     RECT  0.084 83.568 0.137 83.592 ;
     RECT  0.06 83.592 0.137 84.24 ;
     RECT  0.084 84.24 0.137 84.264 ;
     RECT  0.06 84.264 0.137 84.96 ;
     RECT  0.084 84.96 0.137 84.984 ;
     RECT  0.06 84.984 0.137 85.68 ;
     RECT  0.084 85.68 0.137 85.704 ;
     RECT  0.06 85.704 0.137 86.4 ;
     RECT  0.084 86.4 0.137 86.424 ;
     RECT  0.06 86.424 0.137 87.12 ;
     RECT  0.084 87.12 0.137 87.144 ;
     RECT  0.06 87.144 0.137 87.84 ;
     RECT  0.084 87.84 0.137 87.864 ;
     RECT  0.06 87.864 0.137 88.512 ;
     RECT  0.084 88.512 0.137 88.536 ;
     RECT  0.06 88.536 0.137 89.232 ;
     RECT  0.084 89.232 0.137 89.256 ;
     RECT  0.06 89.256 0.137 89.952 ;
     RECT  0.084 89.952 0.137 89.976 ;
     RECT  0.06 89.976 0.137 90.672 ;
     RECT  0.084 90.672 0.137 90.696 ;
     RECT  0.06 90.696 0.137 91.392 ;
     RECT  0.084 91.392 0.137 91.416 ;
     RECT  0.06 91.416 0.137 92.064 ;
     RECT  0.084 92.064 0.137 92.088 ;
     RECT  0.06 92.088 0.137 92.784 ;
     RECT  0.084 92.784 0.137 92.808 ;
     RECT  0.06 92.808 0.137 93.504 ;
     RECT  0.084 93.504 0.137 93.528 ;
     RECT  0.06 93.528 0.137 94.224 ;
     RECT  0.084 94.224 0.137 94.248 ;
     RECT  0.06 94.248 0.137 94.944 ;
     RECT  0.084 94.944 0.137 94.968 ;
     RECT  0.06 94.968 0.137 95.616 ;
     RECT  0.084 95.616 0.137 95.64 ;
     RECT  0.06 95.64 0.137 96.336 ;
     RECT  0.084 96.336 0.137 96.36 ;
     RECT  0.06 96.36 0.137 97.056 ;
     RECT  0.084 97.056 0.137 97.08 ;
     RECT  0.06 97.08 0.137 97.776 ;
     RECT  0.084 97.776 0.137 97.8 ;
     RECT  0.06 97.8 0.137 98.496 ;
     RECT  0.084 98.496 0.137 98.52 ;
     RECT  0.06 98.52 0.137 99.216 ;
     RECT  0.084 99.216 0.137 99.24 ;
     RECT  0.06 99.24 0.137 99.888 ;
     RECT  0.084 99.888 0.137 99.912 ;
     RECT  0.06 99.912 0.137 100.608 ;
     RECT  0.084 100.608 0.137 100.632 ;
     RECT  0.06 100.632 0.137 101.328 ;
     RECT  0.084 101.328 0.137 101.352 ;
     RECT  0.06 101.352 0.137 102.048 ;
     RECT  0.084 102.048 0.137 102.072 ;
     RECT  0.06 102.072 0.137 102.768 ;
     RECT  0.084 102.768 0.137 102.792 ;
     RECT  0.06 102.792 0.137 103.44 ;
     RECT  0.084 103.44 0.137 103.464 ;
     RECT  0.06 103.464 0.137 104.16 ;
     RECT  0.084 104.16 0.137 104.184 ;
     RECT  0.06 104.184 0.137 104.88 ;
     RECT  0.084 104.88 0.137 104.904 ;
     RECT  0.06 104.904 0.137 105.6 ;
     RECT  0.084 105.6 0.137 105.624 ;
     RECT  0.06 105.624 0.137 106.32 ;
     RECT  0.084 106.32 0.137 106.344 ;
     RECT  0.06 106.344 0.137 106.992 ;
     RECT  0.084 106.992 0.137 107.016 ;
     RECT  0.06 107.016 0.137 107.712 ;
     RECT  0.084 107.712 0.137 107.736 ;
     RECT  0.06 107.736 0.137 108.432 ;
     RECT  0.084 108.432 0.137 108.456 ;
     RECT  0.06 108.456 0.137 109.152 ;
     RECT  0.084 109.152 0.137 109.176 ;
     RECT  0.06 109.176 0.137 109.872 ;
     RECT  0.084 109.872 0.137 109.896 ;
     RECT  0.06 109.896 0.137 110.592 ;
     RECT  0.084 110.592 0.137 110.616 ;
     RECT  0.06 110.616 0.137 111.264 ;
     RECT  0.084 111.264 0.137 111.288 ;
     RECT  0.06 111.288 0.137 111.984 ;
     RECT  0.084 111.984 0.137 112.008 ;
     RECT  0.06 112.008 0.137 112.704 ;
     RECT  0.084 112.704 0.137 112.728 ;
     RECT  0.06 112.728 0.137 113.424 ;
     RECT  0.084 113.424 0.137 113.448 ;
     RECT  0.06 113.448 0.137 114.144 ;
     RECT  0.084 114.144 0.137 114.168 ;
     RECT  0.06 114.168 0.137 114.816 ;
     RECT  0.084 114.816 0.137 114.84 ;
     RECT  0.06 114.84 0.137 115.536 ;
     RECT  0.084 115.536 0.137 115.56 ;
     RECT  0.06 115.56 0.137 116.256 ;
     RECT  0.084 116.256 0.137 116.28 ;
     RECT  0.06 116.28 0.137 116.976 ;
     RECT  0.084 116.976 0.137 117 ;
     RECT  0.06 117 0.137 117.696 ;
     RECT  0.084 117.696 0.137 117.72 ;
     RECT  0.06 117.72 0.137 118.368 ;
     RECT  0.084 118.368 0.137 118.392 ;
     RECT  0.06 118.392 0.137 119.088 ;
     RECT  0.084 119.088 0.137 119.112 ;
     RECT  0.06 119.112 0.137 119.808 ;
     RECT  0.084 119.808 0.137 119.832 ;
     RECT  0.06 119.832 0.137 120.528 ;
     RECT  0.084 120.528 0.137 120.552 ;
     RECT  0.06 120.552 0.137 121.248 ;
     RECT  0.084 121.248 0.137 121.272 ;
     RECT  0.06 121.272 0.137 121.968 ;
     RECT  0.084 121.968 0.137 121.992 ;
     RECT  0.06 121.992 0.137 122.64 ;
     RECT  0.084 122.64 0.137 122.664 ;
     RECT  0.06 122.664 0.137 123.36 ;
     RECT  0.084 123.36 0.137 123.384 ;
     RECT  0.06 123.384 0.137 124.08 ;
     RECT  0.084 124.08 0.137 124.104 ;
     RECT  0.06 124.104 0.137 124.8 ;
     RECT  0.084 124.8 0.137 124.824 ;
     RECT  0.06 124.824 0.137 125.52 ;
     RECT  0.084 125.52 0.137 125.544 ;
     RECT  0.06 125.544 0.137 126.192 ;
     RECT  0.084 126.192 0.137 126.216 ;
     RECT  0.06 126.216 0.137 126.912 ;
     RECT  0.084 126.912 0.137 126.936 ;
     RECT  0.06 126.936 0.137 127.632 ;
     RECT  0.084 127.632 0.137 127.656 ;
     RECT  0.06 127.656 0.137 128.352 ;
     RECT  0.084 128.352 0.137 128.376 ;
     RECT  0.06 128.376 0.137 129.072 ;
     RECT  0.084 129.072 0.137 129.096 ;
     RECT  0.06 129.096 0.137 129.744 ;
     RECT  0.084 129.744 0.137 129.768 ;
     RECT  0.06 129.768 0.137 130.464 ;
     RECT  0.084 130.464 0.137 130.488 ;
     RECT  0.06 130.488 0.137 131.184 ;
     RECT  0.084 131.184 0.137 131.208 ;
     RECT  0.06 131.208 0.137 131.904 ;
     RECT  0.084 131.904 0.137 131.928 ;
     RECT  0.06 131.928 0.137 132.624 ;
     RECT  0.084 132.624 0.137 132.648 ;
     RECT  0.06 132.648 0.137 133.296 ;
     RECT  0.084 133.296 0.137 133.32 ;
     RECT  0.06 133.32 0.137 134.016 ;
     RECT  0.084 134.016 0.137 134.04 ;
     RECT  0.06 134.04 0.137 134.736 ;
     RECT  0.084 134.736 0.137 134.76 ;
     RECT  0.06 134.76 0.137 135.456 ;
     RECT  0.084 135.456 0.137 135.48 ;
     RECT  0.06 135.48 0.137 136.176 ;
     RECT  0.084 136.176 0.137 136.2 ;
     RECT  0.06 136.2 0.137 136.896 ;
     RECT  0.084 136.896 0.137 136.92 ;
     RECT  0.06 136.92 0.137 137.568 ;
     RECT  0.084 137.568 0.137 137.592 ;
     RECT  0.06 137.592 0.137 138.288 ;
     RECT  0.084 138.288 0.137 138.312 ;
     RECT  0.06 138.312 0.137 139.008 ;
     RECT  0.084 139.008 0.137 139.032 ;
     RECT  0.06 139.032 0.137 139.728 ;
     RECT  0.084 139.728 0.137 139.752 ;
     RECT  0.06 139.752 0.137 140.448 ;
     RECT  0.084 140.448 0.137 140.472 ;
     RECT  0.06 140.472 0.137 141.12 ;
     RECT  0.084 141.12 0.137 141.144 ;
     RECT  0.06 141.144 0.137 141.84 ;
     RECT  0.084 141.84 0.137 141.864 ;
     RECT  0.06 141.864 0.137 142.56 ;
     RECT  0.084 142.56 0.137 142.584 ;
     RECT  0.06 142.584 0.137 143.28 ;
     RECT  0.084 143.28 0.137 143.304 ;
     RECT  0.137 91.392 0.569 102.792 ;
     RECT  0.137 121.968 0.569 122.664 ;
     RECT  0.137 2.496 2.408 6.072 ;
     RECT  0.137 7.488 2.408 18.168 ;
     RECT  0.137 19.584 2.408 31.656 ;
     RECT  0.137 33.072 2.408 48.744 ;
     RECT  0.137 50.16 2.408 54.408 ;
     RECT  0.137 55.824 2.408 66.504 ;
     RECT  0.137 67.92 2.408 74.328 ;
     RECT  0.137 75.744 2.408 77.88 ;
     RECT  0.137 79.296 2.408 80.04 ;
     RECT  0.137 81.408 2.408 89.976 ;
     RECT  0.569 91.392 2.408 98.52 ;
     RECT  0.569 99.888 2.408 102.792 ;
     RECT  0.137 104.16 2.408 104.184 ;
     RECT  0.137 105.6 2.408 109.896 ;
     RECT  0.137 111.264 2.408 120.552 ;
     RECT  0.569 122.64 2.408 122.664 ;
     RECT  0.137 124.08 2.408 126.216 ;
     RECT  0.137 127.632 2.408 128.376 ;
     RECT  0.137 129.744 2.408 134.04 ;
     RECT  0.137 135.456 2.408 143.304 ;
     RECT  2.408 2.148 2.512 144.732 ;
     RECT  2.512 2.418 2.704 144.462 ;
     RECT  2.704 131.904 2.765 134.04 ;
     RECT  2.704 137.568 2.765 138.312 ;
     RECT  2.704 40.896 2.801 41.64 ;
     RECT  2.704 48.288 2.801 48.744 ;
     RECT  2.704 128.352 2.801 128.376 ;
     RECT  2.704 6.048 2.837 6.072 ;
     RECT  2.704 7.488 2.837 8.232 ;
     RECT  2.704 13.152 2.837 13.896 ;
     RECT  2.704 37.344 2.837 37.368 ;
     RECT  2.704 42.624 2.837 45.336 ;
     RECT  2.704 46.56 2.837 47.208 ;
     RECT  2.704 50.16 2.837 50.856 ;
     RECT  2.704 54.144 2.837 54.408 ;
     RECT  2.704 57.936 2.837 58.68 ;
     RECT  2.704 71.472 2.837 72.84 ;
     RECT  2.704 77.136 2.837 77.88 ;
     RECT  2.704 80.016 2.837 80.04 ;
     RECT  2.704 92.112 2.837 93.528 ;
     RECT  2.704 109.152 2.837 110.568 ;
     RECT  2.704 120.528 2.837 120.552 ;
     RECT  2.704 143.28 2.837 143.304 ;
     RECT  2.704 20.976 2.873 21.72 ;
     RECT  2.704 52.272 2.873 53.016 ;
     RECT  2.704 3.936 3.125 4.68 ;
     RECT  2.765 131.904 3.125 133.32 ;
     RECT  2.704 106.32 3.197 107.64 ;
     RECT  2.704 140.448 3.269 141.384 ;
     RECT  2.704 15.312 3.413 16.056 ;
     RECT  2.704 121.776 3.685 121.8 ;
     RECT  3.685 121.776 3.731 122.664 ;
     RECT  2.704 124.08 3.805 124.104 ;
     RECT  2.837 109.824 3.971 110.568 ;
     RECT  3.884 114 3.971 114.024 ;
     RECT  2.704 115.488 3.971 116.424 ;
     RECT  2.704 63.648 3.973 64.392 ;
     RECT  2.704 66.096 3.973 66.504 ;
     RECT  3.973 63.648 4.019 66.504 ;
     RECT  2.704 67.776 4.019 67.8 ;
     RECT  2.704 9.6 4.025 11.784 ;
     RECT  2.704 27.408 4.025 27.432 ;
     RECT  2.704 33.072 4.025 33.096 ;
     RECT  2.704 35.184 4.025 35.976 ;
     RECT  2.704 38.784 4.025 38.808 ;
     RECT  2.837 43.68 4.025 45.336 ;
     RECT  2.837 47.184 4.025 47.208 ;
     RECT  2.704 61.488 4.025 61.512 ;
     RECT  2.837 72.192 4.025 72.84 ;
     RECT  2.704 81.408 4.025 81.432 ;
     RECT  2.837 92.112 4.025 92.808 ;
     RECT  2.704 95.616 4.025 95.64 ;
     RECT  2.704 98.592 4.025 98.616 ;
     RECT  2.704 100.608 4.025 102.312 ;
     RECT  2.704 104.16 4.025 104.808 ;
     RECT  2.704 112.704 4.025 112.728 ;
     RECT  3.971 115.488 4.025 115.512 ;
     RECT  2.704 118.368 4.025 118.392 ;
     RECT  2.704 126.192 4.025 126.216 ;
     RECT  3.269 140.448 4.025 141.144 ;
     RECT  2.837 54.144 4.057 54.168 ;
     RECT  2.837 7.488 4.061 7.512 ;
     RECT  4.019 66.48 4.097 66.504 ;
     RECT  2.704 97.056 4.117 97.08 ;
     RECT  2.704 18.144 4.129 18.168 ;
     RECT  4.129 17.424 4.157 18.168 ;
     RECT  4.157 17.424 4.201 18.84 ;
     RECT  4.025 101.328 4.213 102.312 ;
     RECT  4.201 17.424 4.22 19.8 ;
     RECT  2.704 129.744 4.245 129.768 ;
     RECT  2.704 29.52 4.248 30.312 ;
     RECT  2.704 89.232 4.248 90.6 ;
     RECT  2.873 21.696 4.261 21.72 ;
     RECT  3.125 131.904 4.261 132.648 ;
     RECT  2.837 13.152 4.268 13.176 ;
     RECT  3.413 16.032 4.268 16.056 ;
     RECT  4.22 17.424 4.268 19.944 ;
     RECT  4.261 21.264 4.268 21.72 ;
     RECT  2.837 50.16 4.268 50.184 ;
     RECT  2.704 75.744 4.268 75.768 ;
     RECT  2.704 83.568 4.268 84.312 ;
     RECT  2.704 86.448 4.268 87.144 ;
     RECT  4.117 97.056 4.268 97.8 ;
     RECT  4.268 75.744 4.271 76.44 ;
     RECT  2.837 77.856 4.271 77.88 ;
     RECT  4.268 21.264 4.273 22.68 ;
     RECT  4.248 88.8 4.273 90.6 ;
     RECT  2.704 23.856 4.309 24.648 ;
     RECT  4.025 35.952 4.309 35.976 ;
     RECT  2.801 48.288 4.309 48.312 ;
     RECT  2.873 52.992 4.309 53.016 ;
     RECT  4.057 54.144 4.309 54.696 ;
     RECT  2.837 58.656 4.309 58.68 ;
     RECT  4.076 60.192 4.309 60.216 ;
     RECT  4.248 80.112 4.309 80.136 ;
     RECT  4.273 88.8 4.309 91.08 ;
     RECT  3.197 106.32 4.309 107.016 ;
     RECT  2.704 135.456 4.309 135.48 ;
     RECT  4.268 127.968 4.357 127.992 ;
     RECT  4.117 62.16 4.453 62.184 ;
     RECT  4.019 63.648 4.453 65.304 ;
     RECT  2.704 2.688 4.46 2.712 ;
     RECT  4.268 13.152 4.46 14.04 ;
     RECT  4.273 21.168 4.46 22.68 ;
     RECT  4.309 23.856 4.46 25.128 ;
     RECT  2.704 39.888 4.46 39.912 ;
     RECT  3.125 4.656 4.481 4.68 ;
     RECT  3.805 124.08 4.489 125.064 ;
     RECT  4.309 135.456 4.489 136.104 ;
     RECT  4.46 2.688 4.501 3.384 ;
     RECT  4.481 4.656 4.501 5.16 ;
     RECT  4.46 13.152 4.501 14.712 ;
     RECT  4.268 16.032 4.501 19.944 ;
     RECT  2.837 42.624 4.501 42.648 ;
     RECT  4.025 43.68 4.501 43.704 ;
     RECT  4.025 45.312 4.501 45.336 ;
     RECT  4.309 106.32 4.501 107.784 ;
     RECT  4.489 134.496 4.501 136.104 ;
     RECT  2.704 70.032 4.525 70.056 ;
     RECT  3.973 68.832 4.549 68.856 ;
     RECT  4.525 70.032 4.549 70.728 ;
     RECT  4.501 2.688 5.108 5.16 ;
     RECT  4.501 6.192 5.108 6.216 ;
     RECT  4.268 8.352 5.108 8.376 ;
     RECT  4.025 9.6 5.108 9.624 ;
     RECT  4.025 11.28 5.108 11.784 ;
     RECT  4.501 13.152 5.108 19.944 ;
     RECT  4.46 21.168 5.108 25.128 ;
     RECT  4.309 27.984 5.108 28.008 ;
     RECT  4.248 29.04 5.108 30.312 ;
     RECT  4.268 31.296 5.108 31.32 ;
     RECT  4.268 33.984 5.108 34.008 ;
     RECT  4.309 35.952 5.108 36.504 ;
     RECT  4.357 38.736 5.108 38.76 ;
     RECT  4.46 39.888 5.108 40.44 ;
     RECT  2.801 41.616 5.108 41.64 ;
     RECT  4.501 42.624 5.108 43.704 ;
     RECT  4.501 45.312 5.108 46.152 ;
     RECT  4.309 48.288 5.108 48.84 ;
     RECT  4.268 50.16 5.108 51 ;
     RECT  4.309 52.992 5.108 54.696 ;
     RECT  2.704 55.824 5.108 56.664 ;
     RECT  4.309 58.656 5.108 60.216 ;
     RECT  4.453 62.16 5.108 65.304 ;
     RECT  4.549 68.832 5.108 70.728 ;
     RECT  2.704 73.968 5.108 73.992 ;
     RECT  4.271 75.744 5.108 77.88 ;
     RECT  4.309 79.248 5.108 80.136 ;
     RECT  4.268 82.32 5.108 82.344 ;
     RECT  4.268 83.568 5.108 85.08 ;
     RECT  4.268 86.448 5.108 87.816 ;
     RECT  4.309 88.8 5.108 92.04 ;
     RECT  4.268 93.456 5.108 93.48 ;
     RECT  4.268 96.384 5.108 97.8 ;
     RECT  4.057 99.168 5.108 99.192 ;
     RECT  4.213 101.328 5.108 102.696 ;
     RECT  4.025 104.784 5.108 104.808 ;
     RECT  4.501 106.32 5.108 108.456 ;
     RECT  3.971 109.824 5.108 109.848 ;
     RECT  4.501 111.456 5.108 111.48 ;
     RECT  4.309 113.616 5.108 113.64 ;
     RECT  4.501 114.96 5.108 114.984 ;
     RECT  4.501 117.168 5.108 117.192 ;
     RECT  4.309 119.088 5.108 119.112 ;
     RECT  4.652 120.624 5.108 120.648 ;
     RECT  3.731 122.64 5.108 122.664 ;
     RECT  4.489 124.08 5.108 125.976 ;
     RECT  4.357 127.968 5.108 128.28 ;
     RECT  4.245 129.744 5.108 130.44 ;
     RECT  4.261 131.904 5.108 133.416 ;
     RECT  4.501 134.496 5.108 136.92 ;
     RECT  2.765 138.288 5.108 138.312 ;
     RECT  2.704 139.296 5.108 139.32 ;
     RECT  4.025 140.448 5.108 140.472 ;
     RECT  4.481 142.512 5.108 142.536 ;
     RECT  5.108 2.148 5.212 144.732 ;
     RECT  5.212 2.418 5.404 144.462 ;
     RECT  5.404 13.152 5.501 13.464 ;
     RECT  5.404 143.088 5.555 143.112 ;
     RECT  5.404 16.032 5.573 16.056 ;
     RECT  5.404 86.016 5.609 87.144 ;
     RECT  5.404 38.112 5.617 38.136 ;
     RECT  5.404 107.76 5.617 107.784 ;
     RECT  5.404 134.928 5.717 135.48 ;
     RECT  5.609 86.016 5.789 86.952 ;
     RECT  5.404 23.856 5.795 24.696 ;
     RECT  5.404 26.16 5.795 27.336 ;
     RECT  5.404 29.616 5.795 30.312 ;
     RECT  5.404 31.584 5.795 31.608 ;
     RECT  5.404 112.272 5.795 112.296 ;
     RECT  5.404 117.744 5.795 117.768 ;
     RECT  5.404 123.6 5.795 123.624 ;
     RECT  5.717 134.928 5.795 134.952 ;
     RECT  5.404 139.488 5.795 139.512 ;
     RECT  5.404 88.608 5.825 89.448 ;
     RECT  5.795 26.784 5.833 27.336 ;
     RECT  5.404 109.392 5.833 109.416 ;
     RECT  5.833 26.832 5.933 27.336 ;
     RECT  5.404 6.816 5.987 7.656 ;
     RECT  5.404 8.928 5.987 9.768 ;
     RECT  5.404 72.192 5.987 72.936 ;
     RECT  5.404 5.088 6.005 5.112 ;
     RECT  5.404 121.296 6.005 121.32 ;
     RECT  5.404 10.8 6.013 10.824 ;
     RECT  5.404 77.808 6.083 78.648 ;
     RECT  5.404 80.784 6.083 81.624 ;
     RECT  5.404 131.472 6.131 131.496 ;
     RECT  5.404 52.992 6.275 53.016 ;
     RECT  6.083 77.808 6.275 77.832 ;
     RECT  5.404 57.6 6.329 58.152 ;
     RECT  5.404 83.184 6.329 83.64 ;
     RECT  5.404 100.272 6.329 100.68 ;
     RECT  5.404 137.616 6.329 137.64 ;
     RECT  5.404 19.92 6.397 19.944 ;
     RECT  5.404 21.168 6.397 21.288 ;
     RECT  6.397 19.344 6.437 19.944 ;
     RECT  5.404 40.8 6.517 40.824 ;
     RECT  5.404 91.056 6.517 91.08 ;
     RECT  5.404 124.8 6.517 124.824 ;
     RECT  6.517 40.8 6.563 41.64 ;
     RECT  6.517 124.8 6.563 125.4 ;
     RECT  6.329 83.616 6.565 83.64 ;
     RECT  5.933 27.312 6.581 27.336 ;
     RECT  6.505 38.736 6.589 38.76 ;
     RECT  6.565 83.616 6.611 84.36 ;
     RECT  5.789 86.592 6.611 86.952 ;
     RECT  5.825 88.608 6.611 89.064 ;
     RECT  6.611 86.928 6.652 86.952 ;
     RECT  6.397 21.168 6.661 21.912 ;
     RECT  6.437 19.344 6.707 19.416 ;
     RECT  6.661 21.12 6.707 21.912 ;
     RECT  6.707 21.12 6.748 21.288 ;
     RECT  5.404 54 6.761 54.696 ;
     RECT  6.764 94.512 6.805 94.536 ;
     RECT  5.404 11.952 6.829 11.976 ;
     RECT  5.501 13.44 6.829 13.464 ;
     RECT  5.404 34.752 6.829 34.776 ;
     RECT  6.761 54.096 6.829 54.696 ;
     RECT  6.517 90.816 6.829 91.08 ;
     RECT  6.563 125.328 6.829 125.4 ;
     RECT  5.404 126.384 6.829 126.6 ;
     RECT  6.611 89.04 6.833 89.064 ;
     RECT  6.829 90.816 6.833 91.272 ;
     RECT  6.829 60.912 6.853 60.936 ;
     RECT  6.329 100.656 6.853 100.68 ;
     RECT  6.829 103.584 6.853 103.608 ;
     RECT  6.829 125.328 6.949 126.6 ;
     RECT  6.829 129.264 6.949 129.288 ;
     RECT  6.829 34.752 6.997 35.304 ;
     RECT  5.404 37.056 6.997 37.08 ;
     RECT  5.404 43.824 6.997 43.848 ;
     RECT  5.404 66.528 7.045 66.552 ;
     RECT  6.829 46.464 7.189 46.488 ;
     RECT  5.404 49.488 7.189 49.512 ;
     RECT  5.404 105.984 7.381 106.008 ;
     RECT  5.987 7.632 7.808 7.656 ;
     RECT  6.829 11.952 7.808 13.464 ;
     RECT  7.004 15.984 7.808 16.008 ;
     RECT  6.829 18.192 7.808 18.216 ;
     RECT  6.707 19.392 7.808 19.416 ;
     RECT  6.748 21.264 7.808 21.288 ;
     RECT  5.795 24.672 7.808 24.696 ;
     RECT  5.795 30.288 7.808 30.312 ;
     RECT  5.404 33.024 7.808 33.048 ;
     RECT  6.997 34.752 7.808 37.08 ;
     RECT  7.052 38.16 7.808 38.184 ;
     RECT  6.563 41.616 7.808 41.64 ;
     RECT  6.997 43.824 7.808 44.616 ;
     RECT  7.189 46.464 7.808 47.352 ;
     RECT  7.189 49.488 7.808 50.28 ;
     RECT  5.404 51.6 7.808 51.624 ;
     RECT  6.829 54.096 7.808 55.32 ;
     RECT  6.829 56.448 7.808 56.472 ;
     RECT  6.329 58.128 7.808 58.152 ;
     RECT  6.853 60.912 7.808 61.608 ;
     RECT  6.829 63.792 7.808 63.816 ;
     RECT  7.045 66.528 7.808 67.32 ;
     RECT  5.987 72.192 7.808 72.84 ;
     RECT  5.404 74.688 7.808 74.712 ;
     RECT  5.404 75.984 7.808 76.008 ;
     RECT  6.083 81.6 7.808 81.624 ;
     RECT  6.611 84.336 7.808 84.36 ;
     RECT  6.997 90.048 7.808 90.072 ;
     RECT  6.833 91.248 7.808 91.272 ;
     RECT  7.045 93.456 7.808 93.48 ;
     RECT  6.805 94.512 7.808 94.632 ;
     RECT  7.045 95.664 7.808 95.688 ;
     RECT  6.853 98.736 7.808 98.76 ;
     RECT  6.853 100.656 7.808 101.448 ;
     RECT  6.853 103.584 7.808 104.136 ;
     RECT  7.381 105.984 7.808 106.728 ;
     RECT  6.517 108.096 7.808 108.312 ;
     RECT  7.429 112.752 7.808 112.776 ;
     RECT  7.045 115.584 7.808 115.608 ;
     RECT  7.045 118.32 7.808 118.344 ;
     RECT  7.58 123.984 7.808 124.008 ;
     RECT  6.949 125.328 7.808 127.416 ;
     RECT  6.949 129.264 7.808 129.96 ;
     RECT  6.937 131.664 7.808 131.688 ;
     RECT  7.004 132.768 7.808 132.792 ;
     RECT  7.045 135.312 7.808 135.336 ;
     RECT  7.669 138.432 7.808 138.456 ;
     RECT  6.829 140.448 7.808 140.472 ;
     RECT  7.808 2.148 7.912 144.732 ;
     RECT  7.912 2.418 8.104 144.462 ;
     RECT  8.104 47.328 8.165 47.352 ;
     RECT  8.104 58.128 8.165 58.152 ;
     RECT  8.104 63.792 8.165 64.392 ;
     RECT  8.104 75.984 8.165 76.008 ;
     RECT  8.104 95.664 8.165 95.688 ;
     RECT  8.104 104.112 8.165 104.136 ;
     RECT  8.104 106.704 8.165 106.728 ;
     RECT  8.104 129.936 8.165 129.96 ;
     RECT  8.104 138.432 8.165 138.456 ;
     RECT  8.104 22.128 8.243 22.152 ;
     RECT  8.104 24.672 8.243 24.696 ;
     RECT  8.165 64.368 8.243 64.392 ;
     RECT  8.104 66.528 8.243 67.32 ;
     RECT  8.104 70.032 8.243 70.056 ;
     RECT  8.104 72.192 8.243 72.984 ;
     RECT  8.104 109.968 8.243 109.992 ;
     RECT  8.104 112.752 8.243 112.776 ;
     RECT  10.508 2.148 10.612 144.732 ;
     RECT  10.612 2.418 10.804 144.462 ;
     RECT  5.941 146.736 10.829 146.76 ;
     RECT  10.804 93.504 11.941 93.528 ;
     RECT  11.941 20.976 12.517 21 ;
     RECT  12.049 3.936 13.208 3.96 ;
     RECT  11.941 9.6 13.208 9.624 ;
     RECT  10.804 15.312 13.208 15.336 ;
     RECT  12.517 20.976 13.208 21.72 ;
     RECT  10.804 27.408 13.208 27.432 ;
     RECT  11.941 38.784 13.208 38.808 ;
     RECT  11.941 61.392 13.208 61.416 ;
     RECT  10.804 67.92 13.208 67.944 ;
     RECT  12.373 75.744 13.208 75.768 ;
     RECT  11.941 92.784 13.208 93.528 ;
     RECT  11.941 99.216 13.208 99.24 ;
     RECT  10.804 104.88 13.208 104.904 ;
     RECT  10.804 107.568 13.208 107.592 ;
     RECT  10.804 114.048 13.208 114.072 ;
     RECT  10.804 116.256 13.208 116.28 ;
     RECT  10.804 122.112 13.208 122.136 ;
     RECT  10.804 127.632 13.208 127.656 ;
     RECT  11.869 133.296 13.208 133.32 ;
     RECT  10.804 139.728 13.208 139.752 ;
     RECT  13.208 2.148 13.312 144.732 ;
     RECT  13.312 2.418 13.504 144.462 ;
     RECT  13.504 61.392 14.713 61.416 ;
     RECT  13.504 107.568 14.713 107.592 ;
     RECT  13.504 114.048 14.713 114.072 ;
     RECT  13.504 122.112 14.713 122.136 ;
     RECT  14.713 61.392 14.861 61.512 ;
     RECT  14.713 107.568 14.861 107.688 ;
     RECT  14.713 114.048 14.861 114.168 ;
     RECT  14.713 121.968 14.861 122.136 ;
     RECT  13.504 3.936 15.908 3.96 ;
     RECT  13.504 9.6 15.908 9.624 ;
     RECT  13.504 15.312 15.908 15.336 ;
     RECT  13.504 20.976 15.908 21.72 ;
     RECT  13.504 27.408 15.908 27.432 ;
     RECT  13.504 38.784 15.908 38.808 ;
     RECT  14.861 61.392 15.908 61.416 ;
     RECT  13.504 67.92 15.908 67.944 ;
     RECT  13.504 75.744 15.908 75.768 ;
     RECT  13.504 92.784 15.908 93.528 ;
     RECT  13.504 99.216 15.908 99.24 ;
     RECT  13.504 104.88 15.908 104.904 ;
     RECT  14.861 107.568 15.908 107.592 ;
     RECT  14.861 114.048 15.908 114.072 ;
     RECT  13.504 116.256 15.908 116.28 ;
     RECT  14.861 122.112 15.908 122.136 ;
     RECT  13.504 127.632 15.908 127.656 ;
     RECT  13.504 133.296 15.908 133.32 ;
     RECT  13.504 139.728 15.908 139.752 ;
     RECT  15.908 2.148 16.012 144.732 ;
     RECT  16.012 2.418 16.204 144.462 ;
     RECT  16.204 3.936 18.608 3.96 ;
     RECT  16.204 9.6 18.608 9.624 ;
     RECT  16.204 15.312 18.608 15.336 ;
     RECT  16.204 20.976 18.608 21.72 ;
     RECT  16.204 27.408 18.608 27.432 ;
     RECT  16.204 33.072 18.608 33.096 ;
     RECT  16.204 38.784 18.608 38.808 ;
     RECT  16.204 61.392 18.608 61.416 ;
     RECT  16.204 67.92 18.608 67.944 ;
     RECT  16.204 75.744 18.608 75.768 ;
     RECT  16.204 92.784 18.608 93.528 ;
     RECT  16.204 99.216 18.608 99.24 ;
     RECT  16.204 104.88 18.608 104.904 ;
     RECT  16.204 107.568 18.608 107.592 ;
     RECT  16.204 114.048 18.608 114.072 ;
     RECT  16.204 116.256 18.608 116.28 ;
     RECT  16.204 122.112 18.608 122.136 ;
     RECT  16.204 127.632 18.608 127.656 ;
     RECT  16.204 133.296 18.608 133.32 ;
     RECT  16.204 139.728 18.608 139.752 ;
     RECT  18.608 2.148 18.712 144.732 ;
     RECT  18.712 2.418 18.904 144.462 ;
     RECT  18.904 9.6 19.933 9.624 ;
     RECT  18.904 15.312 19.933 15.336 ;
     RECT  18.904 38.784 19.933 38.808 ;
     RECT  18.904 81.408 19.933 81.432 ;
     RECT  18.904 114.048 19.933 114.072 ;
     RECT  18.904 121.968 19.933 121.992 ;
     RECT  18.904 133.296 19.933 133.32 ;
     RECT  18.904 139.008 19.933 139.752 ;
     RECT  18.904 3.936 20.473 3.96 ;
     RECT  19.933 12.48 20.473 12.504 ;
     RECT  19.933 13.872 20.473 13.896 ;
     RECT  19.933 15.312 20.473 16.056 ;
     RECT  19.933 19.584 20.473 19.608 ;
     RECT  18.904 20.976 20.473 21.72 ;
     RECT  19.933 23.856 20.473 23.88 ;
     RECT  18.904 27.408 20.473 27.432 ;
     RECT  19.933 31.632 20.473 31.656 ;
     RECT  18.904 33.072 20.473 33.096 ;
     RECT  19.933 38.784 20.473 39.48 ;
     RECT  19.933 40.896 20.473 41.64 ;
     RECT  19.933 43.008 20.473 43.032 ;
     RECT  19.933 48.72 20.473 48.744 ;
     RECT  19.933 81.408 20.473 82.152 ;
     RECT  18.904 92.784 20.473 93.528 ;
     RECT  19.933 94.944 20.473 95.64 ;
     RECT  18.904 99.216 20.473 99.24 ;
     RECT  19.933 102.768 20.473 102.792 ;
     RECT  18.904 104.88 20.473 104.904 ;
     RECT  19.933 114.048 20.473 114.84 ;
     RECT  18.904 116.256 20.473 116.28 ;
     RECT  19.933 121.968 20.473 122.664 ;
     RECT  19.933 124.08 20.473 124.104 ;
     RECT  19.933 126.192 20.473 126.216 ;
     RECT  18.904 127.632 20.473 127.656 ;
     RECT  19.933 130.464 20.473 130.488 ;
     RECT  19.933 131.904 20.473 131.928 ;
     RECT  19.933 133.296 20.473 134.04 ;
     RECT  20.473 3.216 20.509 3.96 ;
     RECT  18.904 5.328 20.509 5.352 ;
     RECT  19.933 18.144 20.509 18.168 ;
     RECT  20.473 27.408 20.509 28.824 ;
     RECT  20.473 30.24 20.509 30.264 ;
     RECT  20.473 31.632 20.509 33.096 ;
     RECT  20.473 35.904 20.509 35.928 ;
     RECT  18.904 61.392 20.509 61.416 ;
     RECT  18.904 67.2 20.509 67.944 ;
     RECT  18.904 75.744 20.509 75.768 ;
     RECT  19.933 77.136 20.509 77.16 ;
     RECT  20.473 78.576 20.509 78.6 ;
     RECT  20.473 81.408 20.509 82.872 ;
     RECT  20.473 84.24 20.509 84.264 ;
     RECT  18.904 90.672 20.509 90.696 ;
     RECT  20.473 92.784 20.509 96.36 ;
     RECT  20.473 98.496 20.509 99.24 ;
     RECT  18.904 107.568 20.509 107.592 ;
     RECT  19.933 109.152 20.509 109.176 ;
     RECT  20.473 114.048 20.509 116.28 ;
     RECT  20.473 117.696 20.509 117.72 ;
     RECT  20.473 119.808 20.509 119.832 ;
     RECT  20.473 121.968 20.509 124.104 ;
     RECT  20.473 125.52 20.509 127.656 ;
     RECT  20.473 129.072 20.509 131.928 ;
     RECT  20.473 133.296 20.509 134.76 ;
     RECT  19.933 136.176 20.509 136.2 ;
     RECT  19.933 137.568 20.509 139.752 ;
     RECT  19.897 141.12 20.509 141.144 ;
     RECT  20.509 2.496 21.481 6.072 ;
     RECT  20.509 8.208 21.481 8.232 ;
     RECT  19.933 9.6 21.481 10.344 ;
     RECT  20.473 12.48 21.481 16.056 ;
     RECT  20.509 17.424 21.481 18.168 ;
     RECT  20.473 19.584 21.481 21.72 ;
     RECT  20.473 23.136 21.481 24.552 ;
     RECT  20.509 25.968 21.481 25.992 ;
     RECT  20.509 27.408 21.481 30.264 ;
     RECT  20.509 31.632 21.481 33.816 ;
     RECT  20.509 35.184 21.481 35.928 ;
     RECT  19.933 37.344 21.481 37.368 ;
     RECT  20.473 38.784 21.481 43.752 ;
     RECT  19.933 45.168 21.481 45.192 ;
     RECT  20.509 46.56 21.481 46.584 ;
     RECT  20.473 48.72 21.481 49.464 ;
     RECT  20.509 50.832 21.481 50.856 ;
     RECT  20.509 52.992 21.481 53.016 ;
     RECT  20.509 54.384 21.481 54.408 ;
     RECT  20.509 55.824 21.481 56.568 ;
     RECT  20.509 57.936 21.481 58.68 ;
     RECT  20.509 60.096 21.481 62.232 ;
     RECT  20.509 64.368 21.481 64.392 ;
     RECT  20.509 66.48 21.481 70.056 ;
     RECT  20.509 71.472 21.481 72.216 ;
     RECT  20.509 74.304 21.481 74.328 ;
     RECT  20.509 75.744 21.481 78.6 ;
     RECT  19.933 80.016 21.481 80.04 ;
     RECT  20.509 81.408 21.481 84.264 ;
     RECT  20.509 85.68 21.481 85.704 ;
     RECT  19.933 87.12 21.481 87.864 ;
     RECT  20.509 89.232 21.481 91.416 ;
     RECT  20.509 92.784 21.481 99.24 ;
     RECT  19.933 100.608 21.481 101.352 ;
     RECT  20.473 102.768 21.481 104.904 ;
     RECT  20.509 106.992 21.481 109.176 ;
     RECT  20.509 110.592 21.481 110.616 ;
     RECT  20.509 112.704 21.481 112.728 ;
     RECT  20.509 114.048 21.481 118.392 ;
     RECT  20.509 119.808 21.481 120.552 ;
     RECT  20.509 121.968 21.481 131.928 ;
     RECT  20.509 133.296 21.481 136.2 ;
     RECT  20.509 137.568 21.481 141.864 ;
     RECT  20.509 143.28 21.481 143.304 ;
     RECT  21.481 2.496 21.516 2.52 ;
     RECT  21.481 2.52 21.564 3.216 ;
     RECT  21.481 3.216 21.516 3.24 ;
     RECT  21.481 3.24 21.564 3.936 ;
     RECT  21.481 3.936 21.516 3.96 ;
     RECT  21.481 3.96 21.564 4.656 ;
     RECT  21.481 4.656 21.516 4.68 ;
     RECT  21.481 4.68 21.564 5.328 ;
     RECT  21.481 5.328 21.516 5.352 ;
     RECT  21.481 5.352 21.564 6.048 ;
     RECT  21.481 6.048 21.516 6.072 ;
     RECT  21.481 6.072 21.564 6.768 ;
     RECT  21.481 6.768 21.516 6.792 ;
     RECT  21.481 6.792 21.564 7.488 ;
     RECT  21.481 7.488 21.516 7.512 ;
     RECT  21.481 7.512 21.564 8.208 ;
     RECT  21.481 8.208 21.516 8.232 ;
     RECT  21.481 8.232 21.564 8.88 ;
     RECT  21.481 8.88 21.516 8.904 ;
     RECT  21.481 8.904 21.564 9.6 ;
     RECT  21.481 9.6 21.516 9.624 ;
     RECT  21.481 9.624 21.564 10.32 ;
     RECT  21.481 10.32 21.516 10.344 ;
     RECT  21.481 10.344 21.564 11.04 ;
     RECT  21.481 11.04 21.516 11.064 ;
     RECT  21.481 11.064 21.564 11.76 ;
     RECT  21.481 11.76 21.516 11.784 ;
     RECT  21.481 11.784 21.564 12.48 ;
     RECT  21.481 12.48 21.516 12.504 ;
     RECT  21.481 12.504 21.564 13.152 ;
     RECT  21.481 13.152 21.516 13.176 ;
     RECT  21.481 13.176 21.564 13.872 ;
     RECT  21.481 13.872 21.516 13.896 ;
     RECT  21.481 13.896 21.564 14.592 ;
     RECT  21.481 14.592 21.516 14.616 ;
     RECT  21.481 14.616 21.564 15.312 ;
     RECT  21.481 15.312 21.516 15.336 ;
     RECT  21.481 15.336 21.564 16.032 ;
     RECT  21.481 16.032 21.516 16.056 ;
     RECT  21.481 16.056 21.564 16.704 ;
     RECT  21.481 16.704 21.516 16.728 ;
     RECT  21.481 16.728 21.564 17.424 ;
     RECT  21.481 17.424 21.516 17.448 ;
     RECT  21.481 17.448 21.564 18.144 ;
     RECT  21.481 18.144 21.516 18.168 ;
     RECT  21.481 18.168 21.564 18.864 ;
     RECT  21.481 18.864 21.516 18.888 ;
     RECT  21.481 18.888 21.564 19.584 ;
     RECT  21.481 19.584 21.516 19.608 ;
     RECT  21.481 19.608 21.564 20.256 ;
     RECT  21.481 20.256 21.516 20.28 ;
     RECT  21.481 20.28 21.564 20.976 ;
     RECT  21.481 20.976 21.516 21 ;
     RECT  21.481 21 21.564 21.696 ;
     RECT  21.481 21.696 21.516 21.72 ;
     RECT  21.481 21.72 21.564 22.416 ;
     RECT  21.481 22.416 21.516 22.44 ;
     RECT  21.481 22.44 21.564 23.136 ;
     RECT  21.481 23.136 21.516 23.16 ;
     RECT  21.481 23.16 21.564 23.856 ;
     RECT  21.481 23.856 21.516 23.88 ;
     RECT  21.481 23.88 21.564 24.528 ;
     RECT  21.481 24.528 21.516 24.552 ;
     RECT  21.481 24.552 21.564 25.248 ;
     RECT  21.481 25.248 21.516 25.272 ;
     RECT  21.481 25.272 21.564 25.968 ;
     RECT  21.481 25.968 21.516 25.992 ;
     RECT  21.481 25.992 21.564 26.688 ;
     RECT  21.481 26.688 21.516 26.712 ;
     RECT  21.481 26.712 21.564 27.408 ;
     RECT  21.481 27.408 21.516 27.432 ;
     RECT  21.481 27.432 21.564 28.08 ;
     RECT  21.481 28.08 21.516 28.104 ;
     RECT  21.481 28.104 21.564 28.8 ;
     RECT  21.481 28.8 21.516 28.824 ;
     RECT  21.481 28.824 21.564 29.52 ;
     RECT  21.481 29.52 21.516 29.544 ;
     RECT  21.481 29.544 21.564 30.24 ;
     RECT  21.481 30.24 21.516 30.264 ;
     RECT  21.481 30.264 21.564 30.96 ;
     RECT  21.481 30.96 21.516 30.984 ;
     RECT  21.481 30.984 21.564 31.632 ;
     RECT  21.481 31.632 21.516 31.656 ;
     RECT  21.481 31.656 21.564 32.352 ;
     RECT  21.481 32.352 21.516 32.376 ;
     RECT  21.481 32.376 21.564 33.072 ;
     RECT  21.481 33.072 21.516 33.096 ;
     RECT  21.481 33.096 21.564 33.792 ;
     RECT  21.481 33.792 21.516 33.816 ;
     RECT  21.481 33.816 21.564 34.512 ;
     RECT  21.481 34.512 21.516 34.536 ;
     RECT  21.481 34.536 21.564 35.184 ;
     RECT  21.481 35.184 21.516 35.208 ;
     RECT  21.481 35.208 21.564 35.904 ;
     RECT  21.481 35.904 21.516 35.928 ;
     RECT  21.481 35.928 21.564 36.624 ;
     RECT  21.481 36.624 21.516 36.648 ;
     RECT  21.481 36.648 21.564 37.344 ;
     RECT  21.481 37.344 21.516 37.368 ;
     RECT  21.481 37.368 21.564 38.064 ;
     RECT  21.481 38.064 21.516 38.088 ;
     RECT  21.481 38.088 21.564 38.784 ;
     RECT  21.481 38.784 21.516 38.808 ;
     RECT  21.481 38.808 21.564 39.456 ;
     RECT  21.481 39.456 21.516 39.48 ;
     RECT  21.481 39.48 21.564 40.176 ;
     RECT  21.481 40.176 21.516 40.2 ;
     RECT  21.481 40.2 21.564 40.896 ;
     RECT  21.481 40.896 21.516 40.92 ;
     RECT  21.481 40.92 21.564 41.616 ;
     RECT  21.481 41.616 21.516 41.64 ;
     RECT  21.481 41.64 21.564 42.336 ;
     RECT  21.481 42.336 21.516 42.36 ;
     RECT  21.481 42.36 21.564 43.008 ;
     RECT  21.481 43.008 21.516 43.032 ;
     RECT  21.481 43.032 21.564 43.728 ;
     RECT  21.481 43.728 21.516 43.752 ;
     RECT  21.481 43.752 21.564 44.448 ;
     RECT  21.481 44.448 21.516 44.472 ;
     RECT  21.481 44.472 21.564 45.168 ;
     RECT  21.481 45.168 21.516 45.192 ;
     RECT  21.481 45.192 21.564 45.888 ;
     RECT  21.481 45.888 21.516 45.912 ;
     RECT  21.481 45.912 21.564 46.56 ;
     RECT  21.481 46.56 21.516 46.584 ;
     RECT  21.481 46.584 21.564 47.28 ;
     RECT  21.481 47.28 21.516 47.304 ;
     RECT  21.481 47.304 21.564 48 ;
     RECT  21.481 48 21.516 48.024 ;
     RECT  21.481 48.024 21.564 48.72 ;
     RECT  21.481 48.72 21.516 48.744 ;
     RECT  21.481 48.744 21.564 49.44 ;
     RECT  21.481 49.44 21.516 49.464 ;
     RECT  21.481 49.464 21.564 50.16 ;
     RECT  21.481 50.16 21.516 50.184 ;
     RECT  21.481 50.184 21.564 50.832 ;
     RECT  21.481 50.832 21.516 50.856 ;
     RECT  21.481 50.856 21.564 51.552 ;
     RECT  21.481 51.552 21.516 51.576 ;
     RECT  21.481 51.576 21.564 52.272 ;
     RECT  21.481 52.272 21.516 52.296 ;
     RECT  21.481 52.296 21.564 52.992 ;
     RECT  21.481 52.992 21.516 53.016 ;
     RECT  21.481 53.016 21.564 53.712 ;
     RECT  21.481 53.712 21.516 53.736 ;
     RECT  21.481 53.736 21.564 54.384 ;
     RECT  21.481 54.384 21.516 54.408 ;
     RECT  21.481 54.408 21.564 55.104 ;
     RECT  21.481 55.104 21.516 55.128 ;
     RECT  21.481 55.128 21.564 55.824 ;
     RECT  21.481 55.824 21.516 55.848 ;
     RECT  21.481 55.848 21.564 56.544 ;
     RECT  21.481 56.544 21.516 56.568 ;
     RECT  21.481 56.568 21.564 57.264 ;
     RECT  21.481 57.264 21.516 57.288 ;
     RECT  21.481 57.288 21.564 57.936 ;
     RECT  21.481 57.936 21.516 57.96 ;
     RECT  21.481 57.96 21.564 58.656 ;
     RECT  21.481 58.656 21.516 58.68 ;
     RECT  21.481 58.68 21.564 59.376 ;
     RECT  21.481 59.376 21.516 59.4 ;
     RECT  21.481 59.4 21.564 60.096 ;
     RECT  21.481 60.096 21.516 60.12 ;
     RECT  21.481 60.12 21.564 60.816 ;
     RECT  21.481 60.816 21.516 60.84 ;
     RECT  21.481 60.84 21.564 61.536 ;
     RECT  21.481 61.536 21.516 61.56 ;
     RECT  21.481 61.56 21.564 62.208 ;
     RECT  21.481 62.208 21.516 62.232 ;
     RECT  21.481 62.232 21.564 62.928 ;
     RECT  21.481 62.928 21.516 62.952 ;
     RECT  21.481 62.952 21.564 63.648 ;
     RECT  21.481 63.648 21.516 63.672 ;
     RECT  21.481 63.672 21.564 64.368 ;
     RECT  21.481 64.368 21.516 64.392 ;
     RECT  21.481 64.392 21.564 65.088 ;
     RECT  21.481 65.088 21.516 65.112 ;
     RECT  21.481 65.112 21.564 65.76 ;
     RECT  21.481 65.76 21.516 65.784 ;
     RECT  21.481 65.784 21.564 66.48 ;
     RECT  21.481 66.48 21.516 66.504 ;
     RECT  21.481 66.504 21.564 67.2 ;
     RECT  21.481 67.2 21.516 67.224 ;
     RECT  21.481 67.224 21.564 67.92 ;
     RECT  21.481 67.92 21.516 67.944 ;
     RECT  21.481 67.944 21.564 68.64 ;
     RECT  21.481 68.64 21.516 68.664 ;
     RECT  21.481 68.664 21.564 69.312 ;
     RECT  21.481 69.312 21.516 69.336 ;
     RECT  21.481 69.336 21.564 70.032 ;
     RECT  21.481 70.032 21.516 70.056 ;
     RECT  21.481 70.056 21.564 70.752 ;
     RECT  21.481 70.752 21.516 70.776 ;
     RECT  21.481 70.776 21.564 71.472 ;
     RECT  21.481 71.472 21.516 71.496 ;
     RECT  21.481 71.496 21.564 72.192 ;
     RECT  21.481 72.192 21.516 72.216 ;
     RECT  21.481 72.216 21.564 72.912 ;
     RECT  21.481 72.912 21.516 72.936 ;
     RECT  21.481 72.936 21.564 73.584 ;
     RECT  21.481 73.584 21.516 73.608 ;
     RECT  21.481 73.608 21.564 74.304 ;
     RECT  21.481 74.304 21.516 74.328 ;
     RECT  21.481 74.328 21.564 75.024 ;
     RECT  21.481 75.024 21.516 75.048 ;
     RECT  21.481 75.048 21.564 75.744 ;
     RECT  21.481 75.744 21.516 75.768 ;
     RECT  21.481 75.768 21.564 76.464 ;
     RECT  21.481 76.464 21.516 76.488 ;
     RECT  21.481 76.488 21.564 77.136 ;
     RECT  21.481 77.136 21.516 77.16 ;
     RECT  21.481 77.16 21.564 77.856 ;
     RECT  21.481 77.856 21.516 77.88 ;
     RECT  21.481 77.88 21.564 78.576 ;
     RECT  21.481 78.576 21.516 78.6 ;
     RECT  21.481 78.6 21.564 79.296 ;
     RECT  21.481 79.296 21.516 79.32 ;
     RECT  21.481 79.32 21.564 80.016 ;
     RECT  21.481 80.016 21.516 80.04 ;
     RECT  21.481 80.04 21.564 80.688 ;
     RECT  21.481 80.688 21.516 80.712 ;
     RECT  21.481 80.712 21.564 81.408 ;
     RECT  21.481 81.408 21.516 81.432 ;
     RECT  21.481 81.432 21.564 82.128 ;
     RECT  21.481 82.128 21.516 82.152 ;
     RECT  21.481 82.152 21.564 82.848 ;
     RECT  21.481 82.848 21.516 82.872 ;
     RECT  21.481 82.872 21.564 83.568 ;
     RECT  21.481 83.568 21.516 83.592 ;
     RECT  21.481 83.592 21.564 84.24 ;
     RECT  21.481 84.24 21.516 84.264 ;
     RECT  21.481 84.264 21.564 84.96 ;
     RECT  21.481 84.96 21.516 84.984 ;
     RECT  21.481 84.984 21.564 85.68 ;
     RECT  21.481 85.68 21.516 85.704 ;
     RECT  21.481 85.704 21.564 86.4 ;
     RECT  21.481 86.4 21.516 86.424 ;
     RECT  21.481 86.424 21.564 87.12 ;
     RECT  21.481 87.12 21.516 87.144 ;
     RECT  21.481 87.144 21.564 87.84 ;
     RECT  21.481 87.84 21.516 87.864 ;
     RECT  21.481 87.864 21.564 88.512 ;
     RECT  21.481 88.512 21.516 88.536 ;
     RECT  21.481 88.536 21.564 89.232 ;
     RECT  21.481 89.232 21.516 89.256 ;
     RECT  21.481 89.256 21.564 89.952 ;
     RECT  21.481 89.952 21.516 89.976 ;
     RECT  21.481 89.976 21.564 90.672 ;
     RECT  21.481 90.672 21.516 90.696 ;
     RECT  21.481 90.696 21.564 91.392 ;
     RECT  21.481 91.392 21.516 91.416 ;
     RECT  21.481 91.416 21.564 92.064 ;
     RECT  21.481 92.064 21.516 92.088 ;
     RECT  21.481 92.088 21.564 92.784 ;
     RECT  21.481 92.784 21.516 92.808 ;
     RECT  21.481 92.808 21.564 93.504 ;
     RECT  21.481 93.504 21.516 93.528 ;
     RECT  21.481 93.528 21.564 94.224 ;
     RECT  21.481 94.224 21.516 94.248 ;
     RECT  21.481 94.248 21.564 94.944 ;
     RECT  21.481 94.944 21.516 94.968 ;
     RECT  21.481 94.968 21.564 95.616 ;
     RECT  21.481 95.616 21.516 95.64 ;
     RECT  21.481 95.64 21.564 96.336 ;
     RECT  21.481 96.336 21.516 96.36 ;
     RECT  21.481 96.36 21.564 97.056 ;
     RECT  21.481 97.056 21.516 97.08 ;
     RECT  21.481 97.08 21.564 97.776 ;
     RECT  21.481 97.776 21.516 97.8 ;
     RECT  21.481 97.8 21.564 98.496 ;
     RECT  21.481 98.496 21.516 98.52 ;
     RECT  21.481 98.52 21.564 99.216 ;
     RECT  21.481 99.216 21.516 99.24 ;
     RECT  21.481 99.24 21.564 99.888 ;
     RECT  21.481 99.888 21.516 99.912 ;
     RECT  21.481 99.912 21.564 100.608 ;
     RECT  21.481 100.608 21.516 100.632 ;
     RECT  21.481 100.632 21.564 101.328 ;
     RECT  21.481 101.328 21.516 101.352 ;
     RECT  21.481 101.352 21.564 102.048 ;
     RECT  21.481 102.048 21.516 102.072 ;
     RECT  21.481 102.072 21.564 102.768 ;
     RECT  21.481 102.768 21.516 102.792 ;
     RECT  21.481 102.792 21.564 103.44 ;
     RECT  21.481 103.44 21.516 103.464 ;
     RECT  21.481 103.464 21.564 104.16 ;
     RECT  21.481 104.16 21.516 104.184 ;
     RECT  21.481 104.184 21.564 104.88 ;
     RECT  21.481 104.88 21.516 104.904 ;
     RECT  21.481 104.904 21.564 105.6 ;
     RECT  21.481 105.6 21.516 105.624 ;
     RECT  21.481 105.624 21.564 106.32 ;
     RECT  21.481 106.32 21.516 106.344 ;
     RECT  21.481 106.344 21.564 106.992 ;
     RECT  21.481 106.992 21.516 107.016 ;
     RECT  21.481 107.016 21.564 107.712 ;
     RECT  21.481 107.712 21.516 107.736 ;
     RECT  21.481 107.736 21.564 108.432 ;
     RECT  21.481 108.432 21.516 108.456 ;
     RECT  21.481 108.456 21.564 109.152 ;
     RECT  21.481 109.152 21.516 109.176 ;
     RECT  21.481 109.176 21.564 109.872 ;
     RECT  21.481 109.872 21.516 109.896 ;
     RECT  21.481 109.896 21.564 110.592 ;
     RECT  21.481 110.592 21.516 110.616 ;
     RECT  21.481 110.616 21.564 111.264 ;
     RECT  21.481 111.264 21.516 111.288 ;
     RECT  21.481 111.288 21.564 111.984 ;
     RECT  21.481 111.984 21.516 112.008 ;
     RECT  21.481 112.008 21.564 112.704 ;
     RECT  21.481 112.704 21.516 112.728 ;
     RECT  21.481 112.728 21.564 113.424 ;
     RECT  21.481 113.424 21.516 113.448 ;
     RECT  21.481 113.448 21.564 114.144 ;
     RECT  21.481 114.144 21.516 114.168 ;
     RECT  21.481 114.168 21.564 114.816 ;
     RECT  21.481 114.816 21.516 114.84 ;
     RECT  21.481 114.84 21.564 115.536 ;
     RECT  21.481 115.536 21.516 115.56 ;
     RECT  21.481 115.56 21.564 116.256 ;
     RECT  21.481 116.256 21.516 116.28 ;
     RECT  21.481 116.28 21.564 116.976 ;
     RECT  21.481 116.976 21.516 117 ;
     RECT  21.481 117 21.564 117.696 ;
     RECT  21.481 117.696 21.516 117.72 ;
     RECT  21.481 117.72 21.564 118.368 ;
     RECT  21.481 118.368 21.516 118.392 ;
     RECT  21.481 118.392 21.564 119.088 ;
     RECT  21.481 119.088 21.516 119.112 ;
     RECT  21.481 119.112 21.564 119.808 ;
     RECT  21.481 119.808 21.516 119.832 ;
     RECT  21.481 119.832 21.564 120.528 ;
     RECT  21.481 120.528 21.516 120.552 ;
     RECT  21.481 120.552 21.564 121.248 ;
     RECT  21.481 121.248 21.516 121.272 ;
     RECT  21.481 121.272 21.564 121.968 ;
     RECT  21.481 121.968 21.516 121.992 ;
     RECT  21.481 121.992 21.564 122.64 ;
     RECT  21.481 122.64 21.516 122.664 ;
     RECT  21.481 122.664 21.564 123.36 ;
     RECT  21.481 123.36 21.516 123.384 ;
     RECT  21.481 123.384 21.564 124.08 ;
     RECT  21.481 124.08 21.516 124.104 ;
     RECT  21.481 124.104 21.564 124.8 ;
     RECT  21.481 124.8 21.516 124.824 ;
     RECT  21.481 124.824 21.564 125.52 ;
     RECT  21.481 125.52 21.516 125.544 ;
     RECT  21.481 125.544 21.564 126.192 ;
     RECT  21.481 126.192 21.516 126.216 ;
     RECT  21.481 126.216 21.564 126.912 ;
     RECT  21.481 126.912 21.516 126.936 ;
     RECT  21.481 126.936 21.564 127.632 ;
     RECT  21.481 127.632 21.516 127.656 ;
     RECT  21.481 127.656 21.564 128.352 ;
     RECT  21.481 128.352 21.516 128.376 ;
     RECT  21.481 128.376 21.564 129.072 ;
     RECT  21.481 129.072 21.516 129.096 ;
     RECT  21.481 129.096 21.564 129.744 ;
     RECT  21.481 129.744 21.516 129.768 ;
     RECT  21.481 129.768 21.564 130.464 ;
     RECT  21.481 130.464 21.516 130.488 ;
     RECT  21.481 130.488 21.564 131.184 ;
     RECT  21.481 131.184 21.516 131.208 ;
     RECT  21.481 131.208 21.564 131.904 ;
     RECT  21.481 131.904 21.516 131.928 ;
     RECT  21.481 131.928 21.564 132.624 ;
     RECT  21.481 132.624 21.516 132.648 ;
     RECT  21.481 132.648 21.564 133.296 ;
     RECT  21.481 133.296 21.516 133.32 ;
     RECT  21.481 133.32 21.564 134.016 ;
     RECT  21.481 134.016 21.516 134.04 ;
     RECT  21.481 134.04 21.564 134.736 ;
     RECT  21.481 134.736 21.516 134.76 ;
     RECT  21.481 134.76 21.564 135.456 ;
     RECT  21.481 135.456 21.516 135.48 ;
     RECT  21.481 135.48 21.564 136.176 ;
     RECT  21.481 136.176 21.516 136.2 ;
     RECT  21.481 136.2 21.564 136.896 ;
     RECT  21.481 136.896 21.516 136.92 ;
     RECT  21.481 136.92 21.564 137.568 ;
     RECT  21.481 137.568 21.516 137.592 ;
     RECT  21.481 137.592 21.564 138.288 ;
     RECT  21.481 138.288 21.516 138.312 ;
     RECT  21.481 138.312 21.564 139.008 ;
     RECT  21.481 139.008 21.516 139.032 ;
     RECT  21.481 139.032 21.564 139.728 ;
     RECT  21.481 139.728 21.516 139.752 ;
     RECT  21.481 139.752 21.564 140.448 ;
     RECT  21.481 140.448 21.516 140.472 ;
     RECT  21.481 140.472 21.564 141.12 ;
     RECT  21.481 141.12 21.516 141.144 ;
     RECT  21.481 141.144 21.564 141.84 ;
     RECT  21.481 141.84 21.516 141.864 ;
     RECT  21.481 141.864 21.564 142.56 ;
     RECT  21.481 142.56 21.516 142.584 ;
     RECT  21.481 142.584 21.564 143.28 ;
     RECT  21.481 143.28 21.516 143.304 ;
    LAYER M5 ;
     RECT  2.4 2.137 2.52 2.151 ;
     RECT  5.1 2.137 5.22 2.151 ;
     RECT  7.8 2.137 7.92 2.151 ;
     RECT  10.5 2.137 10.62 2.151 ;
     RECT  13.2 2.137 13.32 2.151 ;
     RECT  15.9 2.137 16.02 2.151 ;
     RECT  18.6 2.137 18.72 2.151 ;
     RECT  5.1 2.151 5.412 2.677 ;
     RECT  4.32 2.677 5.412 5.077 ;
     RECT  4.32 5.077 5.976 9.779 ;
     RECT  4.32 9.779 5.412 10.789 ;
     RECT  4.32 10.789 5.976 11.987 ;
     RECT  7.8 2.151 8.112 12.517 ;
     RECT  4.32 11.987 5.412 17.413 ;
     RECT  7.056 12.517 8.112 18.181 ;
     RECT  4.176 17.413 5.412 18.851 ;
     RECT  6.864 18.181 8.112 19.333 ;
     RECT  6.672 19.333 8.112 19.427 ;
     RECT  4.32 18.851 5.412 19.909 ;
     RECT  6.672 19.427 6.696 21.253 ;
     RECT  7.8 19.427 8.112 21.253 ;
     RECT  4.272 19.909 5.412 21.299 ;
     RECT  6.672 21.253 8.112 21.923 ;
     RECT  7.104 21.923 8.112 22.117 ;
     RECT  4.32 21.299 5.412 23.845 ;
     RECT  7.104 22.117 8.232 24.707 ;
     RECT  4.32 23.845 5.784 25.139 ;
     RECT  4.512 25.139 5.784 28.019 ;
     RECT  5.1 28.019 5.784 29.029 ;
     RECT  7.104 24.707 8.112 33.013 ;
     RECT  4.32 29.029 5.784 33.059 ;
     RECT  6.912 33.013 8.112 34.787 ;
     RECT  4.32 33.059 5.412 36.515 ;
     RECT  7.008 34.787 8.112 37.091 ;
     RECT  5.1 36.515 5.412 38.101 ;
     RECT  5.1 38.101 5.592 38.725 ;
     RECT  7.104 37.091 8.112 38.725 ;
     RECT  4.368 38.725 8.112 39.923 ;
     RECT  4.512 39.923 8.112 41.651 ;
     RECT  7.008 41.651 8.112 46.499 ;
     RECT  4.512 41.651 5.592 48.277 ;
     RECT  4.32 48.277 5.592 52.981 ;
     RECT  7.104 46.499 8.112 52.981 ;
     RECT  4.32 52.981 8.112 53.603 ;
     RECT  5.1 53.603 8.112 54.035 ;
     RECT  5.1 54.035 5.592 54.565 ;
     RECT  6.864 54.035 8.112 56.483 ;
     RECT  4.416 54.565 5.592 56.629 ;
     RECT  7.8 56.483 8.112 58.117 ;
     RECT  4.32 56.629 5.592 60.181 ;
     RECT  6.864 58.117 8.112 61.619 ;
     RECT  4.128 60.181 5.592 62.195 ;
     RECT  7.056 61.619 8.112 63.827 ;
     RECT  7.8 63.827 8.112 64.357 ;
     RECT  4.464 62.195 5.592 65.269 ;
     RECT  3.984 65.269 5.592 65.315 ;
     RECT  3.984 65.315 4.008 68.821 ;
     RECT  5.1 65.315 5.592 68.821 ;
     RECT  3.984 68.821 5.592 68.867 ;
     RECT  4.56 68.867 5.592 70.739 ;
     RECT  5.1 70.739 5.592 72.901 ;
     RECT  7.8 64.357 8.232 72.995 ;
     RECT  5.1 72.901 5.976 73.957 ;
     RECT  4.32 73.957 5.976 74.677 ;
     RECT  4.32 74.677 6.264 77.843 ;
     RECT  4.32 77.843 6.072 83.605 ;
     RECT  4.32 83.605 6.6 89.075 ;
     RECT  4.32 89.075 6.552 90.037 ;
     RECT  7.8 72.995 8.112 90.037 ;
     RECT  4.32 90.037 8.112 91.283 ;
     RECT  4.32 91.283 6.6 93.445 ;
     RECT  7.8 91.283 8.112 93.445 ;
     RECT  4.32 93.445 8.112 97.765 ;
     RECT  4.128 97.765 8.112 99.203 ;
     RECT  4.224 99.203 8.112 104.819 ;
     RECT  4.32 104.819 8.112 106.739 ;
     RECT  4.32 106.739 6.6 107.795 ;
     RECT  4.512 107.795 6.6 108.085 ;
     RECT  7.8 106.739 8.112 108.085 ;
     RECT  4.512 108.085 8.112 108.323 ;
     RECT  7.8 108.323 8.112 109.957 ;
     RECT  4.512 108.323 6.552 110.533 ;
     RECT  3.936 110.533 6.552 112.741 ;
     RECT  7.8 109.957 8.232 112.741 ;
     RECT  3.936 112.741 8.232 112.787 ;
     RECT  3.936 112.787 8.112 116.389 ;
     RECT  3.696 116.389 8.112 118.355 ;
     RECT  3.696 118.355 6.552 119.123 ;
     RECT  5.1 119.123 6.552 120.613 ;
     RECT  3.696 119.123 3.72 122.629 ;
     RECT  4.704 120.613 6.552 122.629 ;
     RECT  3.696 122.629 6.552 122.675 ;
     RECT  4.464 122.675 6.552 125.075 ;
     RECT  4.512 125.075 6.552 125.317 ;
     RECT  7.632 118.355 8.112 125.317 ;
     RECT  4.512 125.317 8.112 127.957 ;
     RECT  4.32 127.957 8.112 130.405 ;
     RECT  4.272 130.405 8.112 131.507 ;
     RECT  6.96 131.507 8.112 131.699 ;
     RECT  7.8 131.699 8.112 132.757 ;
     RECT  4.272 131.507 5.976 133.427 ;
     RECT  7.056 132.757 8.112 135.347 ;
     RECT  2.4 2.151 2.712 139.285 ;
     RECT  4.32 133.427 5.976 139.331 ;
     RECT  7.68 135.347 8.112 140.483 ;
     RECT  2.4 139.285 3.24 141.395 ;
     RECT  4.512 139.331 5.976 142.547 ;
     RECT  2.4 141.395 2.712 144.729 ;
     RECT  7.8 140.483 8.112 144.729 ;
     RECT  10.5 2.151 10.812 144.729 ;
     RECT  13.2 2.151 13.512 144.729 ;
     RECT  15.9 2.151 16.212 144.729 ;
     RECT  18.6 2.151 18.912 144.729 ;
     RECT  2.4 144.729 2.52 144.743 ;
     RECT  5.1 142.547 5.976 144.743 ;
     RECT  7.8 144.729 7.92 144.743 ;
     RECT  10.5 144.729 10.62 144.743 ;
     RECT  13.2 144.729 13.32 144.743 ;
     RECT  15.9 144.729 16.02 144.743 ;
     RECT  18.6 144.729 18.72 144.743 ;
     RECT  5.952 144.743 5.976 146.771 ;
     RECT  5.412 9.779 5.976 10.789 ;
     RECT  2.712 17.413 4.176 18.851 ;
     RECT  5.412 18.181 6.864 19.333 ;
     RECT  4.272 18.851 4.32 19.909 ;
     RECT  5.412 19.333 6.672 21.923 ;
     RECT  6.696 19.427 7.8 21.253 ;
     RECT  5.784 23.845 7.104 33.013 ;
     RECT  4.512 28.019 5.1 29.029 ;
     RECT  5.784 33.013 6.912 33.059 ;
     RECT  5.412 33.059 6.912 34.787 ;
     RECT  7.008 37.091 7.104 38.101 ;
     RECT  5.592 38.101 7.104 38.725 ;
     RECT  5.592 41.651 7.008 46.499 ;
     RECT  5.592 46.499 7.104 52.981 ;
     RECT  4.416 53.603 5.1 54.565 ;
     RECT  5.592 54.035 6.864 56.483 ;
     RECT  5.592 58.117 6.864 61.619 ;
     RECT  2.712 60.181 4.128 62.195 ;
     RECT  5.592 61.619 7.056 63.827 ;
     RECT  2.712 65.269 3.984 68.867 ;
     RECT  4.008 65.315 5.1 68.821 ;
     RECT  6.6 83.605 7.8 89.075 ;
     RECT  6.552 89.075 7.8 90.037 ;
     RECT  6.6 91.283 7.8 93.445 ;
     RECT  2.712 97.765 4.128 99.203 ;
     RECT  2.712 99.203 4.224 104.819 ;
     RECT  6.6 106.739 7.8 108.085 ;
     RECT  6.552 108.323 7.8 112.741 ;
     RECT  2.712 110.533 3.936 116.389 ;
     RECT  2.712 116.389 3.696 122.675 ;
     RECT  6.552 118.355 7.632 125.317 ;
     RECT  3.72 119.123 5.1 120.613 ;
     RECT  3.72 120.613 4.704 122.629 ;
     RECT  5.976 131.507 6.96 131.699 ;
     RECT  5.976 131.699 7.8 132.757 ;
     RECT  5.976 132.757 7.056 135.347 ;
     RECT  3.24 139.285 4.32 139.331 ;
     RECT  3.24 139.331 4.512 141.395 ;
  END
END qfd_coll_eslice199
END LIBRARY
